VERSION 5.8 ;
BUSBITCHARS "[]" ;
DIVIDERCHAR "/" ;
UNITS
    DATABASE MICRONS 1000 ;
END UNITS

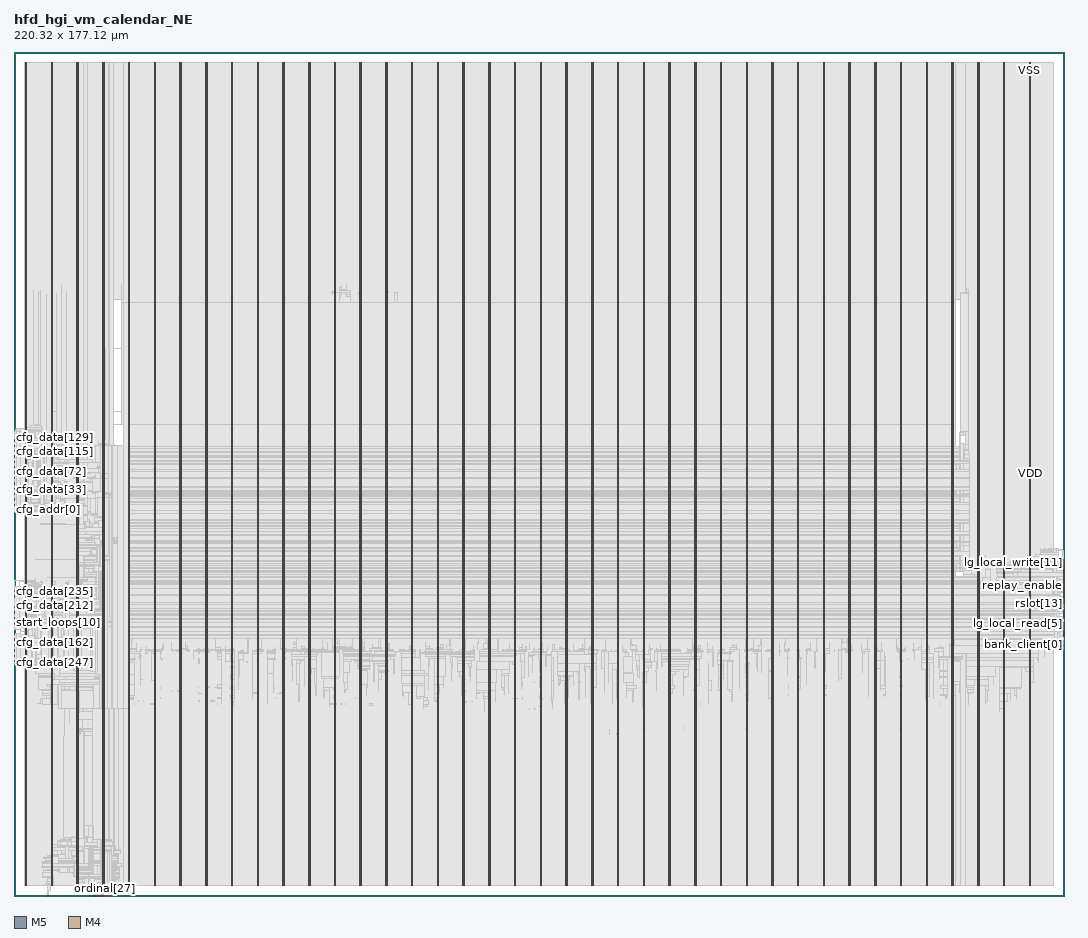
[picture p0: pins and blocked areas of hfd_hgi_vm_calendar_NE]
MACRO hfd_hgi_vm_calendar_NE
  FOREIGN hfd_hgi_vm_calendar_NE 0 0 ;
  CLASS BLOCK ;
  SIZE 220.32 BY 177.12 ;
  PIN active
    DIRECTION OUTPUT ;
    USE SIGNAL ;
    PORT
      LAYER M5 ;
        RECT  16.08 0 16.104 0.084 ;
    END
  END active
  PIN bank_client[0]
    DIRECTION OUTPUT ;
    USE SIGNAL ;
    PORT
      LAYER M4 ;
        RECT  220.236 54.48 220.32 54.504 ;
    END
  END bank_client[0]
  PIN bank_client[1]
    DIRECTION OUTPUT ;
    USE SIGNAL ;
    PORT
      LAYER M4 ;
        RECT  220.236 54.576 220.32 54.6 ;
    END
  END bank_client[1]
  PIN bank_client[2]
    DIRECTION OUTPUT ;
    USE SIGNAL ;
    PORT
      LAYER M4 ;
        RECT  220.236 54.672 220.32 54.696 ;
    END
  END bank_client[2]
  PIN bank_client[3]
    DIRECTION OUTPUT ;
    USE SIGNAL ;
    PORT
      LAYER M4 ;
        RECT  220.236 54.768 220.32 54.792 ;
    END
  END bank_client[3]
  PIN bank_client[4]
    DIRECTION OUTPUT ;
    USE SIGNAL ;
    PORT
      LAYER M4 ;
        RECT  220.236 54.864 220.32 54.888 ;
    END
  END bank_client[4]
  PIN bank_client[5]
    DIRECTION OUTPUT ;
    USE SIGNAL ;
    PORT
      LAYER M4 ;
        RECT  220.236 54.96 220.32 54.984 ;
    END
  END bank_client[5]
  PIN bank_client[6]
    DIRECTION OUTPUT ;
    USE SIGNAL ;
    PORT
      LAYER M4 ;
        RECT  220.236 55.056 220.32 55.08 ;
    END
  END bank_client[6]
  PIN bank_client[7]
    DIRECTION OUTPUT ;
    USE SIGNAL ;
    PORT
      LAYER M4 ;
        RECT  220.236 55.152 220.32 55.176 ;
    END
  END bank_client[7]
  PIN bank_enable[0]
    DIRECTION OUTPUT ;
    USE SIGNAL ;
    PORT
      LAYER M4 ;
        RECT  220.236 55.248 220.32 55.272 ;
    END
  END bank_enable[0]
  PIN bank_enable[1]
    DIRECTION OUTPUT ;
    USE SIGNAL ;
    PORT
      LAYER M4 ;
        RECT  220.236 55.344 220.32 55.368 ;
    END
  END bank_enable[1]
  PIN bank_enable[2]
    DIRECTION OUTPUT ;
    USE SIGNAL ;
    PORT
      LAYER M4 ;
        RECT  220.236 55.44 220.32 55.464 ;
    END
  END bank_enable[2]
  PIN bank_enable[3]
    DIRECTION OUTPUT ;
    USE SIGNAL ;
    PORT
      LAYER M4 ;
        RECT  220.236 55.536 220.32 55.56 ;
    END
  END bank_enable[3]
  PIN bank_enable[4]
    DIRECTION OUTPUT ;
    USE SIGNAL ;
    PORT
      LAYER M4 ;
        RECT  220.236 55.632 220.32 55.656 ;
    END
  END bank_enable[4]
  PIN bank_enable[5]
    DIRECTION OUTPUT ;
    USE SIGNAL ;
    PORT
      LAYER M4 ;
        RECT  220.236 55.728 220.32 55.752 ;
    END
  END bank_enable[5]
  PIN bank_enable[6]
    DIRECTION OUTPUT ;
    USE SIGNAL ;
    PORT
      LAYER M4 ;
        RECT  220.236 55.824 220.32 55.848 ;
    END
  END bank_enable[6]
  PIN bank_enable[7]
    DIRECTION OUTPUT ;
    USE SIGNAL ;
    PORT
      LAYER M4 ;
        RECT  220.236 55.92 220.32 55.944 ;
    END
  END bank_enable[7]
  PIN calendar_v
    DIRECTION OUTPUT ;
    USE SIGNAL ;
    PORT
      LAYER M5 ;
        RECT  16.176 0 16.2 0.084 ;
    END
  END calendar_v
  PIN cfg_addr[0]
    DIRECTION INPUT ;
    USE SIGNAL ;
    PORT
      LAYER M4 ;
        RECT  0 81.168 0.084 81.192 ;
    END
  END cfg_addr[0]
  PIN cfg_addr[1]
    DIRECTION INPUT ;
    USE SIGNAL ;
    PORT
      LAYER M4 ;
        RECT  0 81.264 0.084 81.288 ;
    END
  END cfg_addr[1]
  PIN cfg_addr[2]
    DIRECTION INPUT ;
    USE SIGNAL ;
    PORT
      LAYER M4 ;
        RECT  0 81.36 0.084 81.384 ;
    END
  END cfg_addr[2]
  PIN cfg_addr[3]
    DIRECTION INPUT ;
    USE SIGNAL ;
    PORT
      LAYER M4 ;
        RECT  0 81.456 0.084 81.48 ;
    END
  END cfg_addr[3]
  PIN cfg_addr[4]
    DIRECTION INPUT ;
    USE SIGNAL ;
    PORT
      LAYER M4 ;
        RECT  0 81.552 0.084 81.576 ;
    END
  END cfg_addr[4]
  PIN cfg_addr[5]
    DIRECTION INPUT ;
    USE SIGNAL ;
    PORT
      LAYER M4 ;
        RECT  0 81.648 0.084 81.672 ;
    END
  END cfg_addr[5]
  PIN cfg_addr[6]
    DIRECTION INPUT ;
    USE SIGNAL ;
    PORT
      LAYER M4 ;
        RECT  0 81.744 0.084 81.768 ;
    END
  END cfg_addr[6]
  PIN cfg_addr[7]
    DIRECTION INPUT ;
    USE SIGNAL ;
    PORT
      LAYER M4 ;
        RECT  0 81.84 0.084 81.864 ;
    END
  END cfg_addr[7]
  PIN cfg_addr[8]
    DIRECTION INPUT ;
    USE SIGNAL ;
    PORT
      LAYER M4 ;
        RECT  0 81.936 0.084 81.96 ;
    END
  END cfg_addr[8]
  PIN cfg_addr[9]
    DIRECTION INPUT ;
    USE SIGNAL ;
    PORT
      LAYER M4 ;
        RECT  0 82.032 0.084 82.056 ;
    END
  END cfg_addr[9]
  PIN cfg_data[0]
    DIRECTION INPUT ;
    USE SIGNAL ;
    PORT
      LAYER M4 ;
        RECT  0 82.128 0.084 82.152 ;
    END
  END cfg_data[0]
  PIN cfg_data[100]
    DIRECTION INPUT ;
    USE SIGNAL ;
    PORT
      LAYER M4 ;
        RECT  0 91.728 0.084 91.752 ;
    END
  END cfg_data[100]
  PIN cfg_data[101]
    DIRECTION INPUT ;
    USE SIGNAL ;
    PORT
      LAYER M4 ;
        RECT  0 91.824 0.084 91.848 ;
    END
  END cfg_data[101]
  PIN cfg_data[102]
    DIRECTION INPUT ;
    USE SIGNAL ;
    PORT
      LAYER M4 ;
        RECT  0 91.92 0.084 91.944 ;
    END
  END cfg_data[102]
  PIN cfg_data[103]
    DIRECTION INPUT ;
    USE SIGNAL ;
    PORT
      LAYER M4 ;
        RECT  0 92.016 0.084 92.04 ;
    END
  END cfg_data[103]
  PIN cfg_data[104]
    DIRECTION INPUT ;
    USE SIGNAL ;
    PORT
      LAYER M4 ;
        RECT  0 92.112 0.084 92.136 ;
    END
  END cfg_data[104]
  PIN cfg_data[105]
    DIRECTION INPUT ;
    USE SIGNAL ;
    PORT
      LAYER M4 ;
        RECT  0 92.208 0.084 92.232 ;
    END
  END cfg_data[105]
  PIN cfg_data[106]
    DIRECTION INPUT ;
    USE SIGNAL ;
    PORT
      LAYER M4 ;
        RECT  0 92.304 0.084 92.328 ;
    END
  END cfg_data[106]
  PIN cfg_data[107]
    DIRECTION INPUT ;
    USE SIGNAL ;
    PORT
      LAYER M4 ;
        RECT  0 92.4 0.084 92.424 ;
    END
  END cfg_data[107]
  PIN cfg_data[108]
    DIRECTION INPUT ;
    USE SIGNAL ;
    PORT
      LAYER M4 ;
        RECT  0 92.496 0.084 92.52 ;
    END
  END cfg_data[108]
  PIN cfg_data[109]
    DIRECTION INPUT ;
    USE SIGNAL ;
    PORT
      LAYER M4 ;
        RECT  0 92.592 0.084 92.616 ;
    END
  END cfg_data[109]
  PIN cfg_data[10]
    DIRECTION INPUT ;
    USE SIGNAL ;
    PORT
      LAYER M4 ;
        RECT  0 83.088 0.084 83.112 ;
    END
  END cfg_data[10]
  PIN cfg_data[110]
    DIRECTION INPUT ;
    USE SIGNAL ;
    PORT
      LAYER M4 ;
        RECT  0 92.688 0.084 92.712 ;
    END
  END cfg_data[110]
  PIN cfg_data[111]
    DIRECTION INPUT ;
    USE SIGNAL ;
    PORT
      LAYER M4 ;
        RECT  0 92.784 0.084 92.808 ;
    END
  END cfg_data[111]
  PIN cfg_data[112]
    DIRECTION INPUT ;
    USE SIGNAL ;
    PORT
      LAYER M4 ;
        RECT  0 92.88 0.084 92.904 ;
    END
  END cfg_data[112]
  PIN cfg_data[113]
    DIRECTION INPUT ;
    USE SIGNAL ;
    PORT
      LAYER M4 ;
        RECT  0 92.976 0.084 93 ;
    END
  END cfg_data[113]
  PIN cfg_data[114]
    DIRECTION INPUT ;
    USE SIGNAL ;
    PORT
      LAYER M4 ;
        RECT  0 93.072 0.084 93.096 ;
    END
  END cfg_data[114]
  PIN cfg_data[115]
    DIRECTION INPUT ;
    USE SIGNAL ;
    PORT
      LAYER M4 ;
        RECT  0 93.168 0.084 93.192 ;
    END
  END cfg_data[115]
  PIN cfg_data[116]
    DIRECTION INPUT ;
    USE SIGNAL ;
    PORT
      LAYER M4 ;
        RECT  0 93.264 0.084 93.288 ;
    END
  END cfg_data[116]
  PIN cfg_data[117]
    DIRECTION INPUT ;
    USE SIGNAL ;
    PORT
      LAYER M4 ;
        RECT  0 93.36 0.084 93.384 ;
    END
  END cfg_data[117]
  PIN cfg_data[118]
    DIRECTION INPUT ;
    USE SIGNAL ;
    PORT
      LAYER M4 ;
        RECT  0 93.456 0.084 93.48 ;
    END
  END cfg_data[118]
  PIN cfg_data[119]
    DIRECTION INPUT ;
    USE SIGNAL ;
    PORT
      LAYER M4 ;
        RECT  0 93.552 0.084 93.576 ;
    END
  END cfg_data[119]
  PIN cfg_data[11]
    DIRECTION INPUT ;
    USE SIGNAL ;
    PORT
      LAYER M4 ;
        RECT  0 83.184 0.084 83.208 ;
    END
  END cfg_data[11]
  PIN cfg_data[120]
    DIRECTION INPUT ;
    USE SIGNAL ;
    PORT
      LAYER M4 ;
        RECT  0 93.648 0.084 93.672 ;
    END
  END cfg_data[120]
  PIN cfg_data[121]
    DIRECTION INPUT ;
    USE SIGNAL ;
    PORT
      LAYER M4 ;
        RECT  0 93.744 0.084 93.768 ;
    END
  END cfg_data[121]
  PIN cfg_data[122]
    DIRECTION INPUT ;
    USE SIGNAL ;
    PORT
      LAYER M4 ;
        RECT  0 93.84 0.084 93.864 ;
    END
  END cfg_data[122]
  PIN cfg_data[123]
    DIRECTION INPUT ;
    USE SIGNAL ;
    PORT
      LAYER M4 ;
        RECT  0 93.936 0.084 93.96 ;
    END
  END cfg_data[123]
  PIN cfg_data[124]
    DIRECTION INPUT ;
    USE SIGNAL ;
    PORT
      LAYER M4 ;
        RECT  0 94.032 0.084 94.056 ;
    END
  END cfg_data[124]
  PIN cfg_data[125]
    DIRECTION INPUT ;
    USE SIGNAL ;
    PORT
      LAYER M4 ;
        RECT  0 94.128 0.084 94.152 ;
    END
  END cfg_data[125]
  PIN cfg_data[126]
    DIRECTION INPUT ;
    USE SIGNAL ;
    PORT
      LAYER M4 ;
        RECT  0 94.224 0.084 94.248 ;
    END
  END cfg_data[126]
  PIN cfg_data[127]
    DIRECTION INPUT ;
    USE SIGNAL ;
    PORT
      LAYER M4 ;
        RECT  0 94.32 0.084 94.344 ;
    END
  END cfg_data[127]
  PIN cfg_data[128]
    DIRECTION INPUT ;
    USE SIGNAL ;
    PORT
      LAYER M4 ;
        RECT  0 94.416 0.084 94.44 ;
    END
  END cfg_data[128]
  PIN cfg_data[129]
    DIRECTION INPUT ;
    USE SIGNAL ;
    PORT
      LAYER M4 ;
        RECT  0 94.512 0.084 94.536 ;
    END
  END cfg_data[129]
  PIN cfg_data[12]
    DIRECTION INPUT ;
    USE SIGNAL ;
    PORT
      LAYER M4 ;
        RECT  0 83.28 0.084 83.304 ;
    END
  END cfg_data[12]
  PIN cfg_data[130]
    DIRECTION INPUT ;
    USE SIGNAL ;
    PORT
      LAYER M4 ;
        RECT  0 94.608 0.084 94.632 ;
    END
  END cfg_data[130]
  PIN cfg_data[131]
    DIRECTION INPUT ;
    USE SIGNAL ;
    PORT
      LAYER M4 ;
        RECT  0 94.704 0.084 94.728 ;
    END
  END cfg_data[131]
  PIN cfg_data[132]
    DIRECTION INPUT ;
    USE SIGNAL ;
    PORT
      LAYER M4 ;
        RECT  0 94.8 0.084 94.824 ;
    END
  END cfg_data[132]
  PIN cfg_data[133]
    DIRECTION INPUT ;
    USE SIGNAL ;
    PORT
      LAYER M4 ;
        RECT  0 94.896 0.084 94.92 ;
    END
  END cfg_data[133]
  PIN cfg_data[134]
    DIRECTION INPUT ;
    USE SIGNAL ;
    PORT
      LAYER M4 ;
        RECT  0 94.992 0.084 95.016 ;
    END
  END cfg_data[134]
  PIN cfg_data[135]
    DIRECTION INPUT ;
    USE SIGNAL ;
    PORT
      LAYER M4 ;
        RECT  0 95.088 0.084 95.112 ;
    END
  END cfg_data[135]
  PIN cfg_data[136]
    DIRECTION INPUT ;
    USE SIGNAL ;
    PORT
      LAYER M4 ;
        RECT  0 95.184 0.084 95.208 ;
    END
  END cfg_data[136]
  PIN cfg_data[137]
    DIRECTION INPUT ;
    USE SIGNAL ;
    PORT
      LAYER M4 ;
        RECT  0 95.28 0.084 95.304 ;
    END
  END cfg_data[137]
  PIN cfg_data[138]
    DIRECTION INPUT ;
    USE SIGNAL ;
    PORT
      LAYER M4 ;
        RECT  0 95.376 0.084 95.4 ;
    END
  END cfg_data[138]
  PIN cfg_data[139]
    DIRECTION INPUT ;
    USE SIGNAL ;
    PORT
      LAYER M4 ;
        RECT  0 95.472 0.084 95.496 ;
    END
  END cfg_data[139]
  PIN cfg_data[13]
    DIRECTION INPUT ;
    USE SIGNAL ;
    PORT
      LAYER M4 ;
        RECT  0 83.376 0.084 83.4 ;
    END
  END cfg_data[13]
  PIN cfg_data[140]
    DIRECTION INPUT ;
    USE SIGNAL ;
    PORT
      LAYER M4 ;
        RECT  0 95.568 0.084 95.592 ;
    END
  END cfg_data[140]
  PIN cfg_data[141]
    DIRECTION INPUT ;
    USE SIGNAL ;
    PORT
      LAYER M4 ;
        RECT  0 95.664 0.084 95.688 ;
    END
  END cfg_data[141]
  PIN cfg_data[142]
    DIRECTION INPUT ;
    USE SIGNAL ;
    PORT
      LAYER M4 ;
        RECT  0 95.76 0.084 95.784 ;
    END
  END cfg_data[142]
  PIN cfg_data[143]
    DIRECTION INPUT ;
    USE SIGNAL ;
    PORT
      LAYER M4 ;
        RECT  0 95.856 0.084 95.88 ;
    END
  END cfg_data[143]
  PIN cfg_data[144]
    DIRECTION INPUT ;
    USE SIGNAL ;
    PORT
      LAYER M4 ;
        RECT  0 95.952 0.084 95.976 ;
    END
  END cfg_data[144]
  PIN cfg_data[145]
    DIRECTION INPUT ;
    USE SIGNAL ;
    PORT
      LAYER M4 ;
        RECT  0 96.048 0.084 96.072 ;
    END
  END cfg_data[145]
  PIN cfg_data[146]
    DIRECTION INPUT ;
    USE SIGNAL ;
    PORT
      LAYER M4 ;
        RECT  0 96.144 0.084 96.168 ;
    END
  END cfg_data[146]
  PIN cfg_data[147]
    DIRECTION INPUT ;
    USE SIGNAL ;
    PORT
      LAYER M4 ;
        RECT  0 96.24 0.084 96.264 ;
    END
  END cfg_data[147]
  PIN cfg_data[148]
    DIRECTION INPUT ;
    USE SIGNAL ;
    PORT
      LAYER M4 ;
        RECT  0 96.336 0.084 96.36 ;
    END
  END cfg_data[148]
  PIN cfg_data[149]
    DIRECTION INPUT ;
    USE SIGNAL ;
    PORT
      LAYER M4 ;
        RECT  0 96.432 0.084 96.456 ;
    END
  END cfg_data[149]
  PIN cfg_data[14]
    DIRECTION INPUT ;
    USE SIGNAL ;
    PORT
      LAYER M4 ;
        RECT  0 83.472 0.084 83.496 ;
    END
  END cfg_data[14]
  PIN cfg_data[150]
    DIRECTION INPUT ;
    USE SIGNAL ;
    PORT
      LAYER M4 ;
        RECT  0 51.984 0.084 52.008 ;
    END
  END cfg_data[150]
  PIN cfg_data[151]
    DIRECTION INPUT ;
    USE SIGNAL ;
    PORT
      LAYER M4 ;
        RECT  0 52.08 0.084 52.104 ;
    END
  END cfg_data[151]
  PIN cfg_data[152]
    DIRECTION INPUT ;
    USE SIGNAL ;
    PORT
      LAYER M4 ;
        RECT  0 52.176 0.084 52.2 ;
    END
  END cfg_data[152]
  PIN cfg_data[153]
    DIRECTION INPUT ;
    USE SIGNAL ;
    PORT
      LAYER M4 ;
        RECT  0 52.272 0.084 52.296 ;
    END
  END cfg_data[153]
  PIN cfg_data[154]
    DIRECTION INPUT ;
    USE SIGNAL ;
    PORT
      LAYER M4 ;
        RECT  0 52.368 0.084 52.392 ;
    END
  END cfg_data[154]
  PIN cfg_data[155]
    DIRECTION INPUT ;
    USE SIGNAL ;
    PORT
      LAYER M4 ;
        RECT  0 52.464 0.084 52.488 ;
    END
  END cfg_data[155]
  PIN cfg_data[156]
    DIRECTION INPUT ;
    USE SIGNAL ;
    PORT
      LAYER M4 ;
        RECT  0 52.56 0.084 52.584 ;
    END
  END cfg_data[156]
  PIN cfg_data[157]
    DIRECTION INPUT ;
    USE SIGNAL ;
    PORT
      LAYER M4 ;
        RECT  0 52.656 0.084 52.68 ;
    END
  END cfg_data[157]
  PIN cfg_data[158]
    DIRECTION INPUT ;
    USE SIGNAL ;
    PORT
      LAYER M4 ;
        RECT  0 52.752 0.084 52.776 ;
    END
  END cfg_data[158]
  PIN cfg_data[159]
    DIRECTION INPUT ;
    USE SIGNAL ;
    PORT
      LAYER M4 ;
        RECT  0 52.848 0.084 52.872 ;
    END
  END cfg_data[159]
  PIN cfg_data[15]
    DIRECTION INPUT ;
    USE SIGNAL ;
    PORT
      LAYER M4 ;
        RECT  0 83.568 0.084 83.592 ;
    END
  END cfg_data[15]
  PIN cfg_data[160]
    DIRECTION INPUT ;
    USE SIGNAL ;
    PORT
      LAYER M4 ;
        RECT  0 52.944 0.084 52.968 ;
    END
  END cfg_data[160]
  PIN cfg_data[161]
    DIRECTION INPUT ;
    USE SIGNAL ;
    PORT
      LAYER M4 ;
        RECT  0 53.04 0.084 53.064 ;
    END
  END cfg_data[161]
  PIN cfg_data[162]
    DIRECTION INPUT ;
    USE SIGNAL ;
    PORT
      LAYER M4 ;
        RECT  0 53.136 0.084 53.16 ;
    END
  END cfg_data[162]
  PIN cfg_data[163]
    DIRECTION INPUT ;
    USE SIGNAL ;
    PORT
      LAYER M4 ;
        RECT  0 53.232 0.084 53.256 ;
    END
  END cfg_data[163]
  PIN cfg_data[164]
    DIRECTION INPUT ;
    USE SIGNAL ;
    PORT
      LAYER M4 ;
        RECT  0 53.328 0.084 53.352 ;
    END
  END cfg_data[164]
  PIN cfg_data[165]
    DIRECTION INPUT ;
    USE SIGNAL ;
    PORT
      LAYER M4 ;
        RECT  0 53.424 0.084 53.448 ;
    END
  END cfg_data[165]
  PIN cfg_data[166]
    DIRECTION INPUT ;
    USE SIGNAL ;
    PORT
      LAYER M4 ;
        RECT  0 53.52 0.084 53.544 ;
    END
  END cfg_data[166]
  PIN cfg_data[167]
    DIRECTION INPUT ;
    USE SIGNAL ;
    PORT
      LAYER M4 ;
        RECT  0 53.616 0.084 53.64 ;
    END
  END cfg_data[167]
  PIN cfg_data[168]
    DIRECTION INPUT ;
    USE SIGNAL ;
    PORT
      LAYER M4 ;
        RECT  0 53.712 0.084 53.736 ;
    END
  END cfg_data[168]
  PIN cfg_data[169]
    DIRECTION INPUT ;
    USE SIGNAL ;
    PORT
      LAYER M4 ;
        RECT  0 53.808 0.084 53.832 ;
    END
  END cfg_data[169]
  PIN cfg_data[16]
    DIRECTION INPUT ;
    USE SIGNAL ;
    PORT
      LAYER M4 ;
        RECT  0 83.664 0.084 83.688 ;
    END
  END cfg_data[16]
  PIN cfg_data[170]
    DIRECTION INPUT ;
    USE SIGNAL ;
    PORT
      LAYER M4 ;
        RECT  0 53.904 0.084 53.928 ;
    END
  END cfg_data[170]
  PIN cfg_data[171]
    DIRECTION INPUT ;
    USE SIGNAL ;
    PORT
      LAYER M4 ;
        RECT  0 54 0.084 54.024 ;
    END
  END cfg_data[171]
  PIN cfg_data[172]
    DIRECTION INPUT ;
    USE SIGNAL ;
    PORT
      LAYER M4 ;
        RECT  0 54.096 0.084 54.12 ;
    END
  END cfg_data[172]
  PIN cfg_data[173]
    DIRECTION INPUT ;
    USE SIGNAL ;
    PORT
      LAYER M4 ;
        RECT  0 54.192 0.084 54.216 ;
    END
  END cfg_data[173]
  PIN cfg_data[174]
    DIRECTION INPUT ;
    USE SIGNAL ;
    PORT
      LAYER M4 ;
        RECT  0 54.288 0.084 54.312 ;
    END
  END cfg_data[174]
  PIN cfg_data[175]
    DIRECTION INPUT ;
    USE SIGNAL ;
    PORT
      LAYER M4 ;
        RECT  0 54.384 0.084 54.408 ;
    END
  END cfg_data[175]
  PIN cfg_data[176]
    DIRECTION INPUT ;
    USE SIGNAL ;
    PORT
      LAYER M4 ;
        RECT  0 54.48 0.084 54.504 ;
    END
  END cfg_data[176]
  PIN cfg_data[177]
    DIRECTION INPUT ;
    USE SIGNAL ;
    PORT
      LAYER M4 ;
        RECT  0 54.576 0.084 54.6 ;
    END
  END cfg_data[177]
  PIN cfg_data[178]
    DIRECTION INPUT ;
    USE SIGNAL ;
    PORT
      LAYER M4 ;
        RECT  0 54.672 0.084 54.696 ;
    END
  END cfg_data[178]
  PIN cfg_data[179]
    DIRECTION INPUT ;
    USE SIGNAL ;
    PORT
      LAYER M4 ;
        RECT  0 54.768 0.084 54.792 ;
    END
  END cfg_data[179]
  PIN cfg_data[17]
    DIRECTION INPUT ;
    USE SIGNAL ;
    PORT
      LAYER M4 ;
        RECT  0 83.76 0.084 83.784 ;
    END
  END cfg_data[17]
  PIN cfg_data[180]
    DIRECTION INPUT ;
    USE SIGNAL ;
    PORT
      LAYER M4 ;
        RECT  0 54.864 0.084 54.888 ;
    END
  END cfg_data[180]
  PIN cfg_data[181]
    DIRECTION INPUT ;
    USE SIGNAL ;
    PORT
      LAYER M4 ;
        RECT  0 54.96 0.084 54.984 ;
    END
  END cfg_data[181]
  PIN cfg_data[182]
    DIRECTION INPUT ;
    USE SIGNAL ;
    PORT
      LAYER M4 ;
        RECT  0 58.128 0.084 58.152 ;
    END
  END cfg_data[182]
  PIN cfg_data[183]
    DIRECTION INPUT ;
    USE SIGNAL ;
    PORT
      LAYER M4 ;
        RECT  0 58.224 0.084 58.248 ;
    END
  END cfg_data[183]
  PIN cfg_data[184]
    DIRECTION INPUT ;
    USE SIGNAL ;
    PORT
      LAYER M4 ;
        RECT  0 58.32 0.084 58.344 ;
    END
  END cfg_data[184]
  PIN cfg_data[185]
    DIRECTION INPUT ;
    USE SIGNAL ;
    PORT
      LAYER M4 ;
        RECT  0 58.416 0.084 58.44 ;
    END
  END cfg_data[185]
  PIN cfg_data[186]
    DIRECTION INPUT ;
    USE SIGNAL ;
    PORT
      LAYER M4 ;
        RECT  0 58.512 0.084 58.536 ;
    END
  END cfg_data[186]
  PIN cfg_data[187]
    DIRECTION INPUT ;
    USE SIGNAL ;
    PORT
      LAYER M4 ;
        RECT  0 58.608 0.084 58.632 ;
    END
  END cfg_data[187]
  PIN cfg_data[188]
    DIRECTION INPUT ;
    USE SIGNAL ;
    PORT
      LAYER M4 ;
        RECT  0 58.704 0.084 58.728 ;
    END
  END cfg_data[188]
  PIN cfg_data[189]
    DIRECTION INPUT ;
    USE SIGNAL ;
    PORT
      LAYER M4 ;
        RECT  0 58.8 0.084 58.824 ;
    END
  END cfg_data[189]
  PIN cfg_data[18]
    DIRECTION INPUT ;
    USE SIGNAL ;
    PORT
      LAYER M4 ;
        RECT  0 83.856 0.084 83.88 ;
    END
  END cfg_data[18]
  PIN cfg_data[190]
    DIRECTION INPUT ;
    USE SIGNAL ;
    PORT
      LAYER M4 ;
        RECT  0 58.896 0.084 58.92 ;
    END
  END cfg_data[190]
  PIN cfg_data[191]
    DIRECTION INPUT ;
    USE SIGNAL ;
    PORT
      LAYER M4 ;
        RECT  0 58.992 0.084 59.016 ;
    END
  END cfg_data[191]
  PIN cfg_data[192]
    DIRECTION INPUT ;
    USE SIGNAL ;
    PORT
      LAYER M4 ;
        RECT  0 59.088 0.084 59.112 ;
    END
  END cfg_data[192]
  PIN cfg_data[193]
    DIRECTION INPUT ;
    USE SIGNAL ;
    PORT
      LAYER M4 ;
        RECT  0 59.184 0.084 59.208 ;
    END
  END cfg_data[193]
  PIN cfg_data[194]
    DIRECTION INPUT ;
    USE SIGNAL ;
    PORT
      LAYER M4 ;
        RECT  0 59.28 0.084 59.304 ;
    END
  END cfg_data[194]
  PIN cfg_data[195]
    DIRECTION INPUT ;
    USE SIGNAL ;
    PORT
      LAYER M4 ;
        RECT  0 59.376 0.084 59.4 ;
    END
  END cfg_data[195]
  PIN cfg_data[196]
    DIRECTION INPUT ;
    USE SIGNAL ;
    PORT
      LAYER M4 ;
        RECT  0 59.472 0.084 59.496 ;
    END
  END cfg_data[196]
  PIN cfg_data[197]
    DIRECTION INPUT ;
    USE SIGNAL ;
    PORT
      LAYER M4 ;
        RECT  0 59.568 0.084 59.592 ;
    END
  END cfg_data[197]
  PIN cfg_data[198]
    DIRECTION INPUT ;
    USE SIGNAL ;
    PORT
      LAYER M4 ;
        RECT  0 59.664 0.084 59.688 ;
    END
  END cfg_data[198]
  PIN cfg_data[199]
    DIRECTION INPUT ;
    USE SIGNAL ;
    PORT
      LAYER M4 ;
        RECT  0 59.76 0.084 59.784 ;
    END
  END cfg_data[199]
  PIN cfg_data[19]
    DIRECTION INPUT ;
    USE SIGNAL ;
    PORT
      LAYER M4 ;
        RECT  0 83.952 0.084 83.976 ;
    END
  END cfg_data[19]
  PIN cfg_data[1]
    DIRECTION INPUT ;
    USE SIGNAL ;
    PORT
      LAYER M4 ;
        RECT  0 82.224 0.084 82.248 ;
    END
  END cfg_data[1]
  PIN cfg_data[200]
    DIRECTION INPUT ;
    USE SIGNAL ;
    PORT
      LAYER M4 ;
        RECT  0 59.856 0.084 59.88 ;
    END
  END cfg_data[200]
  PIN cfg_data[201]
    DIRECTION INPUT ;
    USE SIGNAL ;
    PORT
      LAYER M4 ;
        RECT  0 59.952 0.084 59.976 ;
    END
  END cfg_data[201]
  PIN cfg_data[202]
    DIRECTION INPUT ;
    USE SIGNAL ;
    PORT
      LAYER M4 ;
        RECT  0 60.048 0.084 60.072 ;
    END
  END cfg_data[202]
  PIN cfg_data[203]
    DIRECTION INPUT ;
    USE SIGNAL ;
    PORT
      LAYER M4 ;
        RECT  0 60.144 0.084 60.168 ;
    END
  END cfg_data[203]
  PIN cfg_data[204]
    DIRECTION INPUT ;
    USE SIGNAL ;
    PORT
      LAYER M4 ;
        RECT  0 60.24 0.084 60.264 ;
    END
  END cfg_data[204]
  PIN cfg_data[205]
    DIRECTION INPUT ;
    USE SIGNAL ;
    PORT
      LAYER M4 ;
        RECT  0 60.336 0.084 60.36 ;
    END
  END cfg_data[205]
  PIN cfg_data[206]
    DIRECTION INPUT ;
    USE SIGNAL ;
    PORT
      LAYER M4 ;
        RECT  0 60.432 0.084 60.456 ;
    END
  END cfg_data[206]
  PIN cfg_data[207]
    DIRECTION INPUT ;
    USE SIGNAL ;
    PORT
      LAYER M4 ;
        RECT  0 60.528 0.084 60.552 ;
    END
  END cfg_data[207]
  PIN cfg_data[208]
    DIRECTION INPUT ;
    USE SIGNAL ;
    PORT
      LAYER M4 ;
        RECT  0 60.624 0.084 60.648 ;
    END
  END cfg_data[208]
  PIN cfg_data[209]
    DIRECTION INPUT ;
    USE SIGNAL ;
    PORT
      LAYER M4 ;
        RECT  0 60.72 0.084 60.744 ;
    END
  END cfg_data[209]
  PIN cfg_data[20]
    DIRECTION INPUT ;
    USE SIGNAL ;
    PORT
      LAYER M4 ;
        RECT  0 84.048 0.084 84.072 ;
    END
  END cfg_data[20]
  PIN cfg_data[210]
    DIRECTION INPUT ;
    USE SIGNAL ;
    PORT
      LAYER M4 ;
        RECT  0 60.816 0.084 60.84 ;
    END
  END cfg_data[210]
  PIN cfg_data[211]
    DIRECTION INPUT ;
    USE SIGNAL ;
    PORT
      LAYER M4 ;
        RECT  0 60.912 0.084 60.936 ;
    END
  END cfg_data[211]
  PIN cfg_data[212]
    DIRECTION INPUT ;
    USE SIGNAL ;
    PORT
      LAYER M4 ;
        RECT  0 61.008 0.084 61.032 ;
    END
  END cfg_data[212]
  PIN cfg_data[213]
    DIRECTION INPUT ;
    USE SIGNAL ;
    PORT
      LAYER M4 ;
        RECT  0 61.104 0.084 61.128 ;
    END
  END cfg_data[213]
  PIN cfg_data[214]
    DIRECTION INPUT ;
    USE SIGNAL ;
    PORT
      LAYER M4 ;
        RECT  0 61.968 0.084 61.992 ;
    END
  END cfg_data[214]
  PIN cfg_data[215]
    DIRECTION INPUT ;
    USE SIGNAL ;
    PORT
      LAYER M4 ;
        RECT  0 62.064 0.084 62.088 ;
    END
  END cfg_data[215]
  PIN cfg_data[216]
    DIRECTION INPUT ;
    USE SIGNAL ;
    PORT
      LAYER M4 ;
        RECT  0 62.16 0.084 62.184 ;
    END
  END cfg_data[216]
  PIN cfg_data[217]
    DIRECTION INPUT ;
    USE SIGNAL ;
    PORT
      LAYER M4 ;
        RECT  0 62.256 0.084 62.28 ;
    END
  END cfg_data[217]
  PIN cfg_data[218]
    DIRECTION INPUT ;
    USE SIGNAL ;
    PORT
      LAYER M4 ;
        RECT  0 62.352 0.084 62.376 ;
    END
  END cfg_data[218]
  PIN cfg_data[219]
    DIRECTION INPUT ;
    USE SIGNAL ;
    PORT
      LAYER M4 ;
        RECT  0 62.448 0.084 62.472 ;
    END
  END cfg_data[219]
  PIN cfg_data[21]
    DIRECTION INPUT ;
    USE SIGNAL ;
    PORT
      LAYER M4 ;
        RECT  0 84.144 0.084 84.168 ;
    END
  END cfg_data[21]
  PIN cfg_data[220]
    DIRECTION INPUT ;
    USE SIGNAL ;
    PORT
      LAYER M4 ;
        RECT  0 62.544 0.084 62.568 ;
    END
  END cfg_data[220]
  PIN cfg_data[221]
    DIRECTION INPUT ;
    USE SIGNAL ;
    PORT
      LAYER M4 ;
        RECT  0 62.64 0.084 62.664 ;
    END
  END cfg_data[221]
  PIN cfg_data[222]
    DIRECTION INPUT ;
    USE SIGNAL ;
    PORT
      LAYER M4 ;
        RECT  0 62.736 0.084 62.76 ;
    END
  END cfg_data[222]
  PIN cfg_data[223]
    DIRECTION INPUT ;
    USE SIGNAL ;
    PORT
      LAYER M4 ;
        RECT  0 62.832 0.084 62.856 ;
    END
  END cfg_data[223]
  PIN cfg_data[224]
    DIRECTION INPUT ;
    USE SIGNAL ;
    PORT
      LAYER M4 ;
        RECT  0 62.928 0.084 62.952 ;
    END
  END cfg_data[224]
  PIN cfg_data[225]
    DIRECTION INPUT ;
    USE SIGNAL ;
    PORT
      LAYER M4 ;
        RECT  0 63.024 0.084 63.048 ;
    END
  END cfg_data[225]
  PIN cfg_data[226]
    DIRECTION INPUT ;
    USE SIGNAL ;
    PORT
      LAYER M4 ;
        RECT  0 63.12 0.084 63.144 ;
    END
  END cfg_data[226]
  PIN cfg_data[227]
    DIRECTION INPUT ;
    USE SIGNAL ;
    PORT
      LAYER M4 ;
        RECT  0 63.216 0.084 63.24 ;
    END
  END cfg_data[227]
  PIN cfg_data[228]
    DIRECTION INPUT ;
    USE SIGNAL ;
    PORT
      LAYER M4 ;
        RECT  0 63.312 0.084 63.336 ;
    END
  END cfg_data[228]
  PIN cfg_data[229]
    DIRECTION INPUT ;
    USE SIGNAL ;
    PORT
      LAYER M4 ;
        RECT  0 63.408 0.084 63.432 ;
    END
  END cfg_data[229]
  PIN cfg_data[22]
    DIRECTION INPUT ;
    USE SIGNAL ;
    PORT
      LAYER M4 ;
        RECT  0 84.24 0.084 84.264 ;
    END
  END cfg_data[22]
  PIN cfg_data[230]
    DIRECTION INPUT ;
    USE SIGNAL ;
    PORT
      LAYER M4 ;
        RECT  0 63.504 0.084 63.528 ;
    END
  END cfg_data[230]
  PIN cfg_data[231]
    DIRECTION INPUT ;
    USE SIGNAL ;
    PORT
      LAYER M4 ;
        RECT  0 63.6 0.084 63.624 ;
    END
  END cfg_data[231]
  PIN cfg_data[232]
    DIRECTION INPUT ;
    USE SIGNAL ;
    PORT
      LAYER M4 ;
        RECT  0 63.696 0.084 63.72 ;
    END
  END cfg_data[232]
  PIN cfg_data[233]
    DIRECTION INPUT ;
    USE SIGNAL ;
    PORT
      LAYER M4 ;
        RECT  0 63.792 0.084 63.816 ;
    END
  END cfg_data[233]
  PIN cfg_data[234]
    DIRECTION INPUT ;
    USE SIGNAL ;
    PORT
      LAYER M4 ;
        RECT  0 63.888 0.084 63.912 ;
    END
  END cfg_data[234]
  PIN cfg_data[235]
    DIRECTION INPUT ;
    USE SIGNAL ;
    PORT
      LAYER M4 ;
        RECT  0 63.984 0.084 64.008 ;
    END
  END cfg_data[235]
  PIN cfg_data[236]
    DIRECTION INPUT ;
    USE SIGNAL ;
    PORT
      LAYER M4 ;
        RECT  0 64.08 0.084 64.104 ;
    END
  END cfg_data[236]
  PIN cfg_data[237]
    DIRECTION INPUT ;
    USE SIGNAL ;
    PORT
      LAYER M4 ;
        RECT  0 64.176 0.084 64.2 ;
    END
  END cfg_data[237]
  PIN cfg_data[238]
    DIRECTION INPUT ;
    USE SIGNAL ;
    PORT
      LAYER M4 ;
        RECT  0 64.272 0.084 64.296 ;
    END
  END cfg_data[238]
  PIN cfg_data[239]
    DIRECTION INPUT ;
    USE SIGNAL ;
    PORT
      LAYER M4 ;
        RECT  0 64.368 0.084 64.392 ;
    END
  END cfg_data[239]
  PIN cfg_data[23]
    DIRECTION INPUT ;
    USE SIGNAL ;
    PORT
      LAYER M4 ;
        RECT  0 84.336 0.084 84.36 ;
    END
  END cfg_data[23]
  PIN cfg_data[240]
    DIRECTION INPUT ;
    USE SIGNAL ;
    PORT
      LAYER M4 ;
        RECT  0 64.464 0.084 64.488 ;
    END
  END cfg_data[240]
  PIN cfg_data[241]
    DIRECTION INPUT ;
    USE SIGNAL ;
    PORT
      LAYER M4 ;
        RECT  0 64.56 0.084 64.584 ;
    END
  END cfg_data[241]
  PIN cfg_data[242]
    DIRECTION INPUT ;
    USE SIGNAL ;
    PORT
      LAYER M4 ;
        RECT  0 64.656 0.084 64.68 ;
    END
  END cfg_data[242]
  PIN cfg_data[243]
    DIRECTION INPUT ;
    USE SIGNAL ;
    PORT
      LAYER M4 ;
        RECT  0 64.752 0.084 64.776 ;
    END
  END cfg_data[243]
  PIN cfg_data[244]
    DIRECTION INPUT ;
    USE SIGNAL ;
    PORT
      LAYER M4 ;
        RECT  0 64.848 0.084 64.872 ;
    END
  END cfg_data[244]
  PIN cfg_data[245]
    DIRECTION INPUT ;
    USE SIGNAL ;
    PORT
      LAYER M4 ;
        RECT  0 64.944 0.084 64.968 ;
    END
  END cfg_data[245]
  PIN cfg_data[246]
    DIRECTION INPUT ;
    USE SIGNAL ;
    PORT
      LAYER M4 ;
        RECT  0 48.912 0.084 48.936 ;
    END
  END cfg_data[246]
  PIN cfg_data[247]
    DIRECTION INPUT ;
    USE SIGNAL ;
    PORT
      LAYER M4 ;
        RECT  0 49.008 0.084 49.032 ;
    END
  END cfg_data[247]
  PIN cfg_data[248]
    DIRECTION INPUT ;
    USE SIGNAL ;
    PORT
      LAYER M4 ;
        RECT  0 49.104 0.084 49.128 ;
    END
  END cfg_data[248]
  PIN cfg_data[249]
    DIRECTION INPUT ;
    USE SIGNAL ;
    PORT
      LAYER M4 ;
        RECT  0 49.2 0.084 49.224 ;
    END
  END cfg_data[249]
  PIN cfg_data[24]
    DIRECTION INPUT ;
    USE SIGNAL ;
    PORT
      LAYER M4 ;
        RECT  0 84.432 0.084 84.456 ;
    END
  END cfg_data[24]
  PIN cfg_data[250]
    DIRECTION INPUT ;
    USE SIGNAL ;
    PORT
      LAYER M4 ;
        RECT  0 49.296 0.084 49.32 ;
    END
  END cfg_data[250]
  PIN cfg_data[251]
    DIRECTION INPUT ;
    USE SIGNAL ;
    PORT
      LAYER M4 ;
        RECT  0 49.392 0.084 49.416 ;
    END
  END cfg_data[251]
  PIN cfg_data[252]
    DIRECTION INPUT ;
    USE SIGNAL ;
    PORT
      LAYER M4 ;
        RECT  0 49.488 0.084 49.512 ;
    END
  END cfg_data[252]
  PIN cfg_data[253]
    DIRECTION INPUT ;
    USE SIGNAL ;
    PORT
      LAYER M4 ;
        RECT  0 49.584 0.084 49.608 ;
    END
  END cfg_data[253]
  PIN cfg_data[254]
    DIRECTION INPUT ;
    USE SIGNAL ;
    PORT
      LAYER M4 ;
        RECT  0 49.68 0.084 49.704 ;
    END
  END cfg_data[254]
  PIN cfg_data[255]
    DIRECTION INPUT ;
    USE SIGNAL ;
    PORT
      LAYER M4 ;
        RECT  0 49.776 0.084 49.8 ;
    END
  END cfg_data[255]
  PIN cfg_data[25]
    DIRECTION INPUT ;
    USE SIGNAL ;
    PORT
      LAYER M4 ;
        RECT  0 84.528 0.084 84.552 ;
    END
  END cfg_data[25]
  PIN cfg_data[26]
    DIRECTION INPUT ;
    USE SIGNAL ;
    PORT
      LAYER M4 ;
        RECT  0 84.624 0.084 84.648 ;
    END
  END cfg_data[26]
  PIN cfg_data[27]
    DIRECTION INPUT ;
    USE SIGNAL ;
    PORT
      LAYER M4 ;
        RECT  0 84.72 0.084 84.744 ;
    END
  END cfg_data[27]
  PIN cfg_data[28]
    DIRECTION INPUT ;
    USE SIGNAL ;
    PORT
      LAYER M4 ;
        RECT  0 84.816 0.084 84.84 ;
    END
  END cfg_data[28]
  PIN cfg_data[29]
    DIRECTION INPUT ;
    USE SIGNAL ;
    PORT
      LAYER M4 ;
        RECT  0 84.912 0.084 84.936 ;
    END
  END cfg_data[29]
  PIN cfg_data[2]
    DIRECTION INPUT ;
    USE SIGNAL ;
    PORT
      LAYER M4 ;
        RECT  0 82.32 0.084 82.344 ;
    END
  END cfg_data[2]
  PIN cfg_data[30]
    DIRECTION INPUT ;
    USE SIGNAL ;
    PORT
      LAYER M4 ;
        RECT  0 85.008 0.084 85.032 ;
    END
  END cfg_data[30]
  PIN cfg_data[31]
    DIRECTION INPUT ;
    USE SIGNAL ;
    PORT
      LAYER M4 ;
        RECT  0 85.104 0.084 85.128 ;
    END
  END cfg_data[31]
  PIN cfg_data[32]
    DIRECTION INPUT ;
    USE SIGNAL ;
    PORT
      LAYER M4 ;
        RECT  0 85.2 0.084 85.224 ;
    END
  END cfg_data[32]
  PIN cfg_data[33]
    DIRECTION INPUT ;
    USE SIGNAL ;
    PORT
      LAYER M4 ;
        RECT  0 85.296 0.084 85.32 ;
    END
  END cfg_data[33]
  PIN cfg_data[34]
    DIRECTION INPUT ;
    USE SIGNAL ;
    PORT
      LAYER M4 ;
        RECT  0 85.392 0.084 85.416 ;
    END
  END cfg_data[34]
  PIN cfg_data[35]
    DIRECTION INPUT ;
    USE SIGNAL ;
    PORT
      LAYER M4 ;
        RECT  0 85.488 0.084 85.512 ;
    END
  END cfg_data[35]
  PIN cfg_data[36]
    DIRECTION INPUT ;
    USE SIGNAL ;
    PORT
      LAYER M4 ;
        RECT  0 85.584 0.084 85.608 ;
    END
  END cfg_data[36]
  PIN cfg_data[37]
    DIRECTION INPUT ;
    USE SIGNAL ;
    PORT
      LAYER M4 ;
        RECT  0 85.68 0.084 85.704 ;
    END
  END cfg_data[37]
  PIN cfg_data[38]
    DIRECTION INPUT ;
    USE SIGNAL ;
    PORT
      LAYER M4 ;
        RECT  0 85.776 0.084 85.8 ;
    END
  END cfg_data[38]
  PIN cfg_data[39]
    DIRECTION INPUT ;
    USE SIGNAL ;
    PORT
      LAYER M4 ;
        RECT  0 85.872 0.084 85.896 ;
    END
  END cfg_data[39]
  PIN cfg_data[3]
    DIRECTION INPUT ;
    USE SIGNAL ;
    PORT
      LAYER M4 ;
        RECT  0 82.416 0.084 82.44 ;
    END
  END cfg_data[3]
  PIN cfg_data[40]
    DIRECTION INPUT ;
    USE SIGNAL ;
    PORT
      LAYER M4 ;
        RECT  0 85.968 0.084 85.992 ;
    END
  END cfg_data[40]
  PIN cfg_data[41]
    DIRECTION INPUT ;
    USE SIGNAL ;
    PORT
      LAYER M4 ;
        RECT  0 86.064 0.084 86.088 ;
    END
  END cfg_data[41]
  PIN cfg_data[42]
    DIRECTION INPUT ;
    USE SIGNAL ;
    PORT
      LAYER M4 ;
        RECT  0 86.16 0.084 86.184 ;
    END
  END cfg_data[42]
  PIN cfg_data[43]
    DIRECTION INPUT ;
    USE SIGNAL ;
    PORT
      LAYER M4 ;
        RECT  0 86.256 0.084 86.28 ;
    END
  END cfg_data[43]
  PIN cfg_data[44]
    DIRECTION INPUT ;
    USE SIGNAL ;
    PORT
      LAYER M4 ;
        RECT  0 86.352 0.084 86.376 ;
    END
  END cfg_data[44]
  PIN cfg_data[45]
    DIRECTION INPUT ;
    USE SIGNAL ;
    PORT
      LAYER M4 ;
        RECT  0 86.448 0.084 86.472 ;
    END
  END cfg_data[45]
  PIN cfg_data[46]
    DIRECTION INPUT ;
    USE SIGNAL ;
    PORT
      LAYER M4 ;
        RECT  0 86.544 0.084 86.568 ;
    END
  END cfg_data[46]
  PIN cfg_data[47]
    DIRECTION INPUT ;
    USE SIGNAL ;
    PORT
      LAYER M4 ;
        RECT  0 86.64 0.084 86.664 ;
    END
  END cfg_data[47]
  PIN cfg_data[48]
    DIRECTION INPUT ;
    USE SIGNAL ;
    PORT
      LAYER M4 ;
        RECT  0 86.736 0.084 86.76 ;
    END
  END cfg_data[48]
  PIN cfg_data[49]
    DIRECTION INPUT ;
    USE SIGNAL ;
    PORT
      LAYER M4 ;
        RECT  0 86.832 0.084 86.856 ;
    END
  END cfg_data[49]
  PIN cfg_data[4]
    DIRECTION INPUT ;
    USE SIGNAL ;
    PORT
      LAYER M4 ;
        RECT  0 82.512 0.084 82.536 ;
    END
  END cfg_data[4]
  PIN cfg_data[50]
    DIRECTION INPUT ;
    USE SIGNAL ;
    PORT
      LAYER M4 ;
        RECT  0 86.928 0.084 86.952 ;
    END
  END cfg_data[50]
  PIN cfg_data[51]
    DIRECTION INPUT ;
    USE SIGNAL ;
    PORT
      LAYER M4 ;
        RECT  0 87.024 0.084 87.048 ;
    END
  END cfg_data[51]
  PIN cfg_data[52]
    DIRECTION INPUT ;
    USE SIGNAL ;
    PORT
      LAYER M4 ;
        RECT  0 87.12 0.084 87.144 ;
    END
  END cfg_data[52]
  PIN cfg_data[53]
    DIRECTION INPUT ;
    USE SIGNAL ;
    PORT
      LAYER M4 ;
        RECT  0 87.216 0.084 87.24 ;
    END
  END cfg_data[53]
  PIN cfg_data[54]
    DIRECTION INPUT ;
    USE SIGNAL ;
    PORT
      LAYER M4 ;
        RECT  0 87.312 0.084 87.336 ;
    END
  END cfg_data[54]
  PIN cfg_data[55]
    DIRECTION INPUT ;
    USE SIGNAL ;
    PORT
      LAYER M4 ;
        RECT  0 87.408 0.084 87.432 ;
    END
  END cfg_data[55]
  PIN cfg_data[56]
    DIRECTION INPUT ;
    USE SIGNAL ;
    PORT
      LAYER M4 ;
        RECT  0 87.504 0.084 87.528 ;
    END
  END cfg_data[56]
  PIN cfg_data[57]
    DIRECTION INPUT ;
    USE SIGNAL ;
    PORT
      LAYER M4 ;
        RECT  0 87.6 0.084 87.624 ;
    END
  END cfg_data[57]
  PIN cfg_data[58]
    DIRECTION INPUT ;
    USE SIGNAL ;
    PORT
      LAYER M4 ;
        RECT  0 87.696 0.084 87.72 ;
    END
  END cfg_data[58]
  PIN cfg_data[59]
    DIRECTION INPUT ;
    USE SIGNAL ;
    PORT
      LAYER M4 ;
        RECT  0 87.792 0.084 87.816 ;
    END
  END cfg_data[59]
  PIN cfg_data[5]
    DIRECTION INPUT ;
    USE SIGNAL ;
    PORT
      LAYER M4 ;
        RECT  0 82.608 0.084 82.632 ;
    END
  END cfg_data[5]
  PIN cfg_data[60]
    DIRECTION INPUT ;
    USE SIGNAL ;
    PORT
      LAYER M4 ;
        RECT  0 87.888 0.084 87.912 ;
    END
  END cfg_data[60]
  PIN cfg_data[61]
    DIRECTION INPUT ;
    USE SIGNAL ;
    PORT
      LAYER M4 ;
        RECT  0 87.984 0.084 88.008 ;
    END
  END cfg_data[61]
  PIN cfg_data[62]
    DIRECTION INPUT ;
    USE SIGNAL ;
    PORT
      LAYER M4 ;
        RECT  0 88.08 0.084 88.104 ;
    END
  END cfg_data[62]
  PIN cfg_data[63]
    DIRECTION INPUT ;
    USE SIGNAL ;
    PORT
      LAYER M4 ;
        RECT  0 88.176 0.084 88.2 ;
    END
  END cfg_data[63]
  PIN cfg_data[64]
    DIRECTION INPUT ;
    USE SIGNAL ;
    PORT
      LAYER M4 ;
        RECT  0 88.272 0.084 88.296 ;
    END
  END cfg_data[64]
  PIN cfg_data[65]
    DIRECTION INPUT ;
    USE SIGNAL ;
    PORT
      LAYER M4 ;
        RECT  0 88.368 0.084 88.392 ;
    END
  END cfg_data[65]
  PIN cfg_data[66]
    DIRECTION INPUT ;
    USE SIGNAL ;
    PORT
      LAYER M4 ;
        RECT  0 88.464 0.084 88.488 ;
    END
  END cfg_data[66]
  PIN cfg_data[67]
    DIRECTION INPUT ;
    USE SIGNAL ;
    PORT
      LAYER M4 ;
        RECT  0 88.56 0.084 88.584 ;
    END
  END cfg_data[67]
  PIN cfg_data[68]
    DIRECTION INPUT ;
    USE SIGNAL ;
    PORT
      LAYER M4 ;
        RECT  0 88.656 0.084 88.68 ;
    END
  END cfg_data[68]
  PIN cfg_data[69]
    DIRECTION INPUT ;
    USE SIGNAL ;
    PORT
      LAYER M4 ;
        RECT  0 88.752 0.084 88.776 ;
    END
  END cfg_data[69]
  PIN cfg_data[6]
    DIRECTION INPUT ;
    USE SIGNAL ;
    PORT
      LAYER M4 ;
        RECT  0 82.704 0.084 82.728 ;
    END
  END cfg_data[6]
  PIN cfg_data[70]
    DIRECTION INPUT ;
    USE SIGNAL ;
    PORT
      LAYER M4 ;
        RECT  0 88.848 0.084 88.872 ;
    END
  END cfg_data[70]
  PIN cfg_data[71]
    DIRECTION INPUT ;
    USE SIGNAL ;
    PORT
      LAYER M4 ;
        RECT  0 88.944 0.084 88.968 ;
    END
  END cfg_data[71]
  PIN cfg_data[72]
    DIRECTION INPUT ;
    USE SIGNAL ;
    PORT
      LAYER M4 ;
        RECT  0 89.04 0.084 89.064 ;
    END
  END cfg_data[72]
  PIN cfg_data[73]
    DIRECTION INPUT ;
    USE SIGNAL ;
    PORT
      LAYER M4 ;
        RECT  0 89.136 0.084 89.16 ;
    END
  END cfg_data[73]
  PIN cfg_data[74]
    DIRECTION INPUT ;
    USE SIGNAL ;
    PORT
      LAYER M4 ;
        RECT  0 89.232 0.084 89.256 ;
    END
  END cfg_data[74]
  PIN cfg_data[75]
    DIRECTION INPUT ;
    USE SIGNAL ;
    PORT
      LAYER M4 ;
        RECT  0 89.328 0.084 89.352 ;
    END
  END cfg_data[75]
  PIN cfg_data[76]
    DIRECTION INPUT ;
    USE SIGNAL ;
    PORT
      LAYER M4 ;
        RECT  0 89.424 0.084 89.448 ;
    END
  END cfg_data[76]
  PIN cfg_data[77]
    DIRECTION INPUT ;
    USE SIGNAL ;
    PORT
      LAYER M4 ;
        RECT  0 89.52 0.084 89.544 ;
    END
  END cfg_data[77]
  PIN cfg_data[78]
    DIRECTION INPUT ;
    USE SIGNAL ;
    PORT
      LAYER M4 ;
        RECT  0 89.616 0.084 89.64 ;
    END
  END cfg_data[78]
  PIN cfg_data[79]
    DIRECTION INPUT ;
    USE SIGNAL ;
    PORT
      LAYER M4 ;
        RECT  0 89.712 0.084 89.736 ;
    END
  END cfg_data[79]
  PIN cfg_data[7]
    DIRECTION INPUT ;
    USE SIGNAL ;
    PORT
      LAYER M4 ;
        RECT  0 82.8 0.084 82.824 ;
    END
  END cfg_data[7]
  PIN cfg_data[80]
    DIRECTION INPUT ;
    USE SIGNAL ;
    PORT
      LAYER M4 ;
        RECT  0 89.808 0.084 89.832 ;
    END
  END cfg_data[80]
  PIN cfg_data[81]
    DIRECTION INPUT ;
    USE SIGNAL ;
    PORT
      LAYER M4 ;
        RECT  0 89.904 0.084 89.928 ;
    END
  END cfg_data[81]
  PIN cfg_data[82]
    DIRECTION INPUT ;
    USE SIGNAL ;
    PORT
      LAYER M4 ;
        RECT  0 90 0.084 90.024 ;
    END
  END cfg_data[82]
  PIN cfg_data[83]
    DIRECTION INPUT ;
    USE SIGNAL ;
    PORT
      LAYER M4 ;
        RECT  0 90.096 0.084 90.12 ;
    END
  END cfg_data[83]
  PIN cfg_data[84]
    DIRECTION INPUT ;
    USE SIGNAL ;
    PORT
      LAYER M4 ;
        RECT  0 90.192 0.084 90.216 ;
    END
  END cfg_data[84]
  PIN cfg_data[85]
    DIRECTION INPUT ;
    USE SIGNAL ;
    PORT
      LAYER M4 ;
        RECT  0 90.288 0.084 90.312 ;
    END
  END cfg_data[85]
  PIN cfg_data[86]
    DIRECTION INPUT ;
    USE SIGNAL ;
    PORT
      LAYER M4 ;
        RECT  0 90.384 0.084 90.408 ;
    END
  END cfg_data[86]
  PIN cfg_data[87]
    DIRECTION INPUT ;
    USE SIGNAL ;
    PORT
      LAYER M4 ;
        RECT  0 90.48 0.084 90.504 ;
    END
  END cfg_data[87]
  PIN cfg_data[88]
    DIRECTION INPUT ;
    USE SIGNAL ;
    PORT
      LAYER M4 ;
        RECT  0 90.576 0.084 90.6 ;
    END
  END cfg_data[88]
  PIN cfg_data[89]
    DIRECTION INPUT ;
    USE SIGNAL ;
    PORT
      LAYER M4 ;
        RECT  0 90.672 0.084 90.696 ;
    END
  END cfg_data[89]
  PIN cfg_data[8]
    DIRECTION INPUT ;
    USE SIGNAL ;
    PORT
      LAYER M4 ;
        RECT  0 82.896 0.084 82.92 ;
    END
  END cfg_data[8]
  PIN cfg_data[90]
    DIRECTION INPUT ;
    USE SIGNAL ;
    PORT
      LAYER M4 ;
        RECT  0 90.768 0.084 90.792 ;
    END
  END cfg_data[90]
  PIN cfg_data[91]
    DIRECTION INPUT ;
    USE SIGNAL ;
    PORT
      LAYER M4 ;
        RECT  0 90.864 0.084 90.888 ;
    END
  END cfg_data[91]
  PIN cfg_data[92]
    DIRECTION INPUT ;
    USE SIGNAL ;
    PORT
      LAYER M4 ;
        RECT  0 90.96 0.084 90.984 ;
    END
  END cfg_data[92]
  PIN cfg_data[93]
    DIRECTION INPUT ;
    USE SIGNAL ;
    PORT
      LAYER M4 ;
        RECT  0 91.056 0.084 91.08 ;
    END
  END cfg_data[93]
  PIN cfg_data[94]
    DIRECTION INPUT ;
    USE SIGNAL ;
    PORT
      LAYER M4 ;
        RECT  0 91.152 0.084 91.176 ;
    END
  END cfg_data[94]
  PIN cfg_data[95]
    DIRECTION INPUT ;
    USE SIGNAL ;
    PORT
      LAYER M4 ;
        RECT  0 91.248 0.084 91.272 ;
    END
  END cfg_data[95]
  PIN cfg_data[96]
    DIRECTION INPUT ;
    USE SIGNAL ;
    PORT
      LAYER M4 ;
        RECT  0 91.344 0.084 91.368 ;
    END
  END cfg_data[96]
  PIN cfg_data[97]
    DIRECTION INPUT ;
    USE SIGNAL ;
    PORT
      LAYER M4 ;
        RECT  0 91.44 0.084 91.464 ;
    END
  END cfg_data[97]
  PIN cfg_data[98]
    DIRECTION INPUT ;
    USE SIGNAL ;
    PORT
      LAYER M4 ;
        RECT  0 91.536 0.084 91.56 ;
    END
  END cfg_data[98]
  PIN cfg_data[99]
    DIRECTION INPUT ;
    USE SIGNAL ;
    PORT
      LAYER M4 ;
        RECT  0 91.632 0.084 91.656 ;
    END
  END cfg_data[99]
  PIN cfg_data[9]
    DIRECTION INPUT ;
    USE SIGNAL ;
    PORT
      LAYER M4 ;
        RECT  0 82.992 0.084 83.016 ;
    END
  END cfg_data[9]
  PIN cfg_we
    DIRECTION INPUT ;
    USE SIGNAL ;
    PORT
      LAYER M4 ;
        RECT  0 49.872 0.084 49.896 ;
    END
  END cfg_we
  PIN client_seq[0]
    DIRECTION OUTPUT ;
    USE SIGNAL ;
    PORT
      LAYER M4 ;
        RECT  220.236 56.016 220.32 56.04 ;
    END
  END client_seq[0]
  PIN client_seq[1]
    DIRECTION OUTPUT ;
    USE SIGNAL ;
    PORT
      LAYER M4 ;
        RECT  220.236 56.112 220.32 56.136 ;
    END
  END client_seq[1]
  PIN clk
    DIRECTION INPUT ;
    USE SIGNAL ;
    PORT
      LAYER M4 ;
        RECT  0 49.968 0.084 49.992 ;
    END
  END clk
  PIN done
    DIRECTION OUTPUT ;
    USE SIGNAL ;
    PORT
      LAYER M5 ;
        RECT  16.272 0 16.296 0.084 ;
    END
  END done
  PIN fault
    DIRECTION OUTPUT ;
    USE SIGNAL ;
    PORT
      LAYER M5 ;
        RECT  16.368 0 16.392 0.084 ;
    END
  END fault
  PIN hub_ring_client[0]
    DIRECTION OUTPUT ;
    USE SIGNAL ;
    PORT
      LAYER M4 ;
        RECT  220.236 56.208 220.32 56.232 ;
    END
  END hub_ring_client[0]
  PIN hub_ring_client[1]
    DIRECTION OUTPUT ;
    USE SIGNAL ;
    PORT
      LAYER M4 ;
        RECT  220.236 56.304 220.32 56.328 ;
    END
  END hub_ring_client[1]
  PIN hub_ring_enable[0]
    DIRECTION OUTPUT ;
    USE SIGNAL ;
    PORT
      LAYER M4 ;
        RECT  220.236 56.4 220.32 56.424 ;
    END
  END hub_ring_enable[0]
  PIN hub_ring_enable[1]
    DIRECTION OUTPUT ;
    USE SIGNAL ;
    PORT
      LAYER M4 ;
        RECT  220.236 56.496 220.32 56.52 ;
    END
  END hub_ring_enable[1]
  PIN lg_local_read[0]
    DIRECTION OUTPUT ;
    USE SIGNAL ;
    PORT
      LAYER M4 ;
        RECT  220.236 56.592 220.32 56.616 ;
    END
  END lg_local_read[0]
  PIN lg_local_read[10]
    DIRECTION OUTPUT ;
    USE SIGNAL ;
    PORT
      LAYER M4 ;
        RECT  220.236 67.536 220.32 67.56 ;
    END
  END lg_local_read[10]
  PIN lg_local_read[11]
    DIRECTION OUTPUT ;
    USE SIGNAL ;
    PORT
      LAYER M4 ;
        RECT  220.236 67.632 220.32 67.656 ;
    END
  END lg_local_read[11]
  PIN lg_local_read[12]
    DIRECTION OUTPUT ;
    USE SIGNAL ;
    PORT
      LAYER M4 ;
        RECT  220.236 67.728 220.32 67.752 ;
    END
  END lg_local_read[12]
  PIN lg_local_read[13]
    DIRECTION OUTPUT ;
    USE SIGNAL ;
    PORT
      LAYER M4 ;
        RECT  220.236 67.824 220.32 67.848 ;
    END
  END lg_local_read[13]
  PIN lg_local_read[14]
    DIRECTION OUTPUT ;
    USE SIGNAL ;
    PORT
      LAYER M4 ;
        RECT  220.236 67.92 220.32 67.944 ;
    END
  END lg_local_read[14]
  PIN lg_local_read[15]
    DIRECTION OUTPUT ;
    USE SIGNAL ;
    PORT
      LAYER M4 ;
        RECT  220.236 68.016 220.32 68.04 ;
    END
  END lg_local_read[15]
  PIN lg_local_read[16]
    DIRECTION OUTPUT ;
    USE SIGNAL ;
    PORT
      LAYER M4 ;
        RECT  220.236 68.112 220.32 68.136 ;
    END
  END lg_local_read[16]
  PIN lg_local_read[17]
    DIRECTION OUTPUT ;
    USE SIGNAL ;
    PORT
      LAYER M4 ;
        RECT  220.236 68.208 220.32 68.232 ;
    END
  END lg_local_read[17]
  PIN lg_local_read[18]
    DIRECTION OUTPUT ;
    USE SIGNAL ;
    PORT
      LAYER M4 ;
        RECT  220.236 68.304 220.32 68.328 ;
    END
  END lg_local_read[18]
  PIN lg_local_read[19]
    DIRECTION OUTPUT ;
    USE SIGNAL ;
    PORT
      LAYER M4 ;
        RECT  220.236 68.4 220.32 68.424 ;
    END
  END lg_local_read[19]
  PIN lg_local_read[1]
    DIRECTION OUTPUT ;
    USE SIGNAL ;
    PORT
      LAYER M4 ;
        RECT  220.236 56.688 220.32 56.712 ;
    END
  END lg_local_read[1]
  PIN lg_local_read[20]
    DIRECTION OUTPUT ;
    USE SIGNAL ;
    PORT
      LAYER M4 ;
        RECT  220.236 68.496 220.32 68.52 ;
    END
  END lg_local_read[20]
  PIN lg_local_read[21]
    DIRECTION OUTPUT ;
    USE SIGNAL ;
    PORT
      LAYER M4 ;
        RECT  220.236 68.592 220.32 68.616 ;
    END
  END lg_local_read[21]
  PIN lg_local_read[22]
    DIRECTION OUTPUT ;
    USE SIGNAL ;
    PORT
      LAYER M4 ;
        RECT  220.236 68.688 220.32 68.712 ;
    END
  END lg_local_read[22]
  PIN lg_local_read[23]
    DIRECTION OUTPUT ;
    USE SIGNAL ;
    PORT
      LAYER M4 ;
        RECT  220.236 68.784 220.32 68.808 ;
    END
  END lg_local_read[23]
  PIN lg_local_read[2]
    DIRECTION OUTPUT ;
    USE SIGNAL ;
    PORT
      LAYER M4 ;
        RECT  220.236 56.784 220.32 56.808 ;
    END
  END lg_local_read[2]
  PIN lg_local_read[3]
    DIRECTION OUTPUT ;
    USE SIGNAL ;
    PORT
      LAYER M4 ;
        RECT  220.236 56.88 220.32 56.904 ;
    END
  END lg_local_read[3]
  PIN lg_local_read[4]
    DIRECTION OUTPUT ;
    USE SIGNAL ;
    PORT
      LAYER M4 ;
        RECT  220.236 56.976 220.32 57 ;
    END
  END lg_local_read[4]
  PIN lg_local_read[5]
    DIRECTION OUTPUT ;
    USE SIGNAL ;
    PORT
      LAYER M4 ;
        RECT  220.236 57.072 220.32 57.096 ;
    END
  END lg_local_read[5]
  PIN lg_local_read[6]
    DIRECTION OUTPUT ;
    USE SIGNAL ;
    PORT
      LAYER M4 ;
        RECT  220.236 57.168 220.32 57.192 ;
    END
  END lg_local_read[6]
  PIN lg_local_read[7]
    DIRECTION OUTPUT ;
    USE SIGNAL ;
    PORT
      LAYER M4 ;
        RECT  220.236 57.264 220.32 57.288 ;
    END
  END lg_local_read[7]
  PIN lg_local_read[8]
    DIRECTION OUTPUT ;
    USE SIGNAL ;
    PORT
      LAYER M4 ;
        RECT  220.236 57.36 220.32 57.384 ;
    END
  END lg_local_read[8]
  PIN lg_local_read[9]
    DIRECTION OUTPUT ;
    USE SIGNAL ;
    PORT
      LAYER M4 ;
        RECT  220.236 57.456 220.32 57.48 ;
    END
  END lg_local_read[9]
  PIN lg_local_write[0]
    DIRECTION OUTPUT ;
    USE SIGNAL ;
    PORT
      LAYER M4 ;
        RECT  220.236 68.88 220.32 68.904 ;
    END
  END lg_local_write[0]
  PIN lg_local_write[10]
    DIRECTION OUTPUT ;
    USE SIGNAL ;
    PORT
      LAYER M4 ;
        RECT  220.236 69.84 220.32 69.864 ;
    END
  END lg_local_write[10]
  PIN lg_local_write[11]
    DIRECTION OUTPUT ;
    USE SIGNAL ;
    PORT
      LAYER M4 ;
        RECT  220.236 69.936 220.32 69.96 ;
    END
  END lg_local_write[11]
  PIN lg_local_write[12]
    DIRECTION OUTPUT ;
    USE SIGNAL ;
    PORT
      LAYER M4 ;
        RECT  220.236 70.032 220.32 70.056 ;
    END
  END lg_local_write[12]
  PIN lg_local_write[13]
    DIRECTION OUTPUT ;
    USE SIGNAL ;
    PORT
      LAYER M4 ;
        RECT  220.236 70.128 220.32 70.152 ;
    END
  END lg_local_write[13]
  PIN lg_local_write[14]
    DIRECTION OUTPUT ;
    USE SIGNAL ;
    PORT
      LAYER M4 ;
        RECT  220.236 70.224 220.32 70.248 ;
    END
  END lg_local_write[14]
  PIN lg_local_write[15]
    DIRECTION OUTPUT ;
    USE SIGNAL ;
    PORT
      LAYER M4 ;
        RECT  220.236 70.32 220.32 70.344 ;
    END
  END lg_local_write[15]
  PIN lg_local_write[16]
    DIRECTION OUTPUT ;
    USE SIGNAL ;
    PORT
      LAYER M4 ;
        RECT  220.236 70.416 220.32 70.44 ;
    END
  END lg_local_write[16]
  PIN lg_local_write[17]
    DIRECTION OUTPUT ;
    USE SIGNAL ;
    PORT
      LAYER M4 ;
        RECT  220.236 70.512 220.32 70.536 ;
    END
  END lg_local_write[17]
  PIN lg_local_write[18]
    DIRECTION OUTPUT ;
    USE SIGNAL ;
    PORT
      LAYER M4 ;
        RECT  220.236 64.464 220.32 64.488 ;
    END
  END lg_local_write[18]
  PIN lg_local_write[19]
    DIRECTION OUTPUT ;
    USE SIGNAL ;
    PORT
      LAYER M4 ;
        RECT  220.236 64.56 220.32 64.584 ;
    END
  END lg_local_write[19]
  PIN lg_local_write[1]
    DIRECTION OUTPUT ;
    USE SIGNAL ;
    PORT
      LAYER M4 ;
        RECT  220.236 68.976 220.32 69 ;
    END
  END lg_local_write[1]
  PIN lg_local_write[20]
    DIRECTION OUTPUT ;
    USE SIGNAL ;
    PORT
      LAYER M4 ;
        RECT  220.236 64.656 220.32 64.68 ;
    END
  END lg_local_write[20]
  PIN lg_local_write[21]
    DIRECTION OUTPUT ;
    USE SIGNAL ;
    PORT
      LAYER M4 ;
        RECT  220.236 64.752 220.32 64.776 ;
    END
  END lg_local_write[21]
  PIN lg_local_write[22]
    DIRECTION OUTPUT ;
    USE SIGNAL ;
    PORT
      LAYER M4 ;
        RECT  220.236 64.848 220.32 64.872 ;
    END
  END lg_local_write[22]
  PIN lg_local_write[23]
    DIRECTION OUTPUT ;
    USE SIGNAL ;
    PORT
      LAYER M4 ;
        RECT  220.236 64.944 220.32 64.968 ;
    END
  END lg_local_write[23]
  PIN lg_local_write[2]
    DIRECTION OUTPUT ;
    USE SIGNAL ;
    PORT
      LAYER M4 ;
        RECT  220.236 69.072 220.32 69.096 ;
    END
  END lg_local_write[2]
  PIN lg_local_write[3]
    DIRECTION OUTPUT ;
    USE SIGNAL ;
    PORT
      LAYER M4 ;
        RECT  220.236 69.168 220.32 69.192 ;
    END
  END lg_local_write[3]
  PIN lg_local_write[4]
    DIRECTION OUTPUT ;
    USE SIGNAL ;
    PORT
      LAYER M4 ;
        RECT  220.236 69.264 220.32 69.288 ;
    END
  END lg_local_write[4]
  PIN lg_local_write[5]
    DIRECTION OUTPUT ;
    USE SIGNAL ;
    PORT
      LAYER M4 ;
        RECT  220.236 69.36 220.32 69.384 ;
    END
  END lg_local_write[5]
  PIN lg_local_write[6]
    DIRECTION OUTPUT ;
    USE SIGNAL ;
    PORT
      LAYER M4 ;
        RECT  220.236 69.456 220.32 69.48 ;
    END
  END lg_local_write[6]
  PIN lg_local_write[7]
    DIRECTION OUTPUT ;
    USE SIGNAL ;
    PORT
      LAYER M4 ;
        RECT  220.236 69.552 220.32 69.576 ;
    END
  END lg_local_write[7]
  PIN lg_local_write[8]
    DIRECTION OUTPUT ;
    USE SIGNAL ;
    PORT
      LAYER M4 ;
        RECT  220.236 69.648 220.32 69.672 ;
    END
  END lg_local_write[8]
  PIN lg_local_write[9]
    DIRECTION OUTPUT ;
    USE SIGNAL ;
    PORT
      LAYER M4 ;
        RECT  220.236 69.744 220.32 69.768 ;
    END
  END lg_local_write[9]
  PIN ordinal[0]
    DIRECTION OUTPUT ;
    USE SIGNAL ;
    PORT
      LAYER M5 ;
        RECT  16.464 0 16.488 0.084 ;
    END
  END ordinal[0]
  PIN ordinal[10]
    DIRECTION OUTPUT ;
    USE SIGNAL ;
    PORT
      LAYER M5 ;
        RECT  17.424 0 17.448 0.084 ;
    END
  END ordinal[10]
  PIN ordinal[11]
    DIRECTION OUTPUT ;
    USE SIGNAL ;
    PORT
      LAYER M5 ;
        RECT  17.52 0 17.544 0.084 ;
    END
  END ordinal[11]
  PIN ordinal[12]
    DIRECTION OUTPUT ;
    USE SIGNAL ;
    PORT
      LAYER M5 ;
        RECT  17.616 0 17.64 0.084 ;
    END
  END ordinal[12]
  PIN ordinal[13]
    DIRECTION OUTPUT ;
    USE SIGNAL ;
    PORT
      LAYER M5 ;
        RECT  17.712 0 17.736 0.084 ;
    END
  END ordinal[13]
  PIN ordinal[14]
    DIRECTION OUTPUT ;
    USE SIGNAL ;
    PORT
      LAYER M5 ;
        RECT  17.808 0 17.832 0.084 ;
    END
  END ordinal[14]
  PIN ordinal[15]
    DIRECTION OUTPUT ;
    USE SIGNAL ;
    PORT
      LAYER M5 ;
        RECT  17.904 0 17.928 0.084 ;
    END
  END ordinal[15]
  PIN ordinal[16]
    DIRECTION OUTPUT ;
    USE SIGNAL ;
    PORT
      LAYER M5 ;
        RECT  18 0 18.024 0.084 ;
    END
  END ordinal[16]
  PIN ordinal[17]
    DIRECTION OUTPUT ;
    USE SIGNAL ;
    PORT
      LAYER M5 ;
        RECT  18.096 0 18.12 0.084 ;
    END
  END ordinal[17]
  PIN ordinal[18]
    DIRECTION OUTPUT ;
    USE SIGNAL ;
    PORT
      LAYER M5 ;
        RECT  18.192 0 18.216 0.084 ;
    END
  END ordinal[18]
  PIN ordinal[19]
    DIRECTION OUTPUT ;
    USE SIGNAL ;
    PORT
      LAYER M5 ;
        RECT  18.288 0 18.312 0.084 ;
    END
  END ordinal[19]
  PIN ordinal[1]
    DIRECTION OUTPUT ;
    USE SIGNAL ;
    PORT
      LAYER M5 ;
        RECT  16.56 0 16.584 0.084 ;
    END
  END ordinal[1]
  PIN ordinal[20]
    DIRECTION OUTPUT ;
    USE SIGNAL ;
    PORT
      LAYER M5 ;
        RECT  18.384 0 18.408 0.084 ;
    END
  END ordinal[20]
  PIN ordinal[21]
    DIRECTION OUTPUT ;
    USE SIGNAL ;
    PORT
      LAYER M5 ;
        RECT  18.48 0 18.504 0.084 ;
    END
  END ordinal[21]
  PIN ordinal[22]
    DIRECTION OUTPUT ;
    USE SIGNAL ;
    PORT
      LAYER M5 ;
        RECT  18.576 0 18.6 0.084 ;
    END
  END ordinal[22]
  PIN ordinal[23]
    DIRECTION OUTPUT ;
    USE SIGNAL ;
    PORT
      LAYER M5 ;
        RECT  18.672 0 18.696 0.084 ;
    END
  END ordinal[23]
  PIN ordinal[24]
    DIRECTION OUTPUT ;
    USE SIGNAL ;
    PORT
      LAYER M5 ;
        RECT  18.768 0 18.792 0.084 ;
    END
  END ordinal[24]
  PIN ordinal[25]
    DIRECTION OUTPUT ;
    USE SIGNAL ;
    PORT
      LAYER M5 ;
        RECT  18.864 0 18.888 0.084 ;
    END
  END ordinal[25]
  PIN ordinal[26]
    DIRECTION OUTPUT ;
    USE SIGNAL ;
    PORT
      LAYER M5 ;
        RECT  18.96 0 18.984 0.084 ;
    END
  END ordinal[26]
  PIN ordinal[27]
    DIRECTION OUTPUT ;
    USE SIGNAL ;
    PORT
      LAYER M5 ;
        RECT  19.056 0 19.08 0.084 ;
    END
  END ordinal[27]
  PIN ordinal[28]
    DIRECTION OUTPUT ;
    USE SIGNAL ;
    PORT
      LAYER M5 ;
        RECT  6.864 0 6.888 0.084 ;
    END
  END ordinal[28]
  PIN ordinal[29]
    DIRECTION OUTPUT ;
    USE SIGNAL ;
    PORT
      LAYER M5 ;
        RECT  6.96 0 6.984 0.084 ;
    END
  END ordinal[29]
  PIN ordinal[2]
    DIRECTION OUTPUT ;
    USE SIGNAL ;
    PORT
      LAYER M5 ;
        RECT  16.656 0 16.68 0.084 ;
    END
  END ordinal[2]
  PIN ordinal[30]
    DIRECTION OUTPUT ;
    USE SIGNAL ;
    PORT
      LAYER M5 ;
        RECT  7.056 0 7.08 0.084 ;
    END
  END ordinal[30]
  PIN ordinal[31]
    DIRECTION OUTPUT ;
    USE SIGNAL ;
    PORT
      LAYER M5 ;
        RECT  7.152 0 7.176 0.084 ;
    END
  END ordinal[31]
  PIN ordinal[3]
    DIRECTION OUTPUT ;
    USE SIGNAL ;
    PORT
      LAYER M5 ;
        RECT  16.752 0 16.776 0.084 ;
    END
  END ordinal[3]
  PIN ordinal[4]
    DIRECTION OUTPUT ;
    USE SIGNAL ;
    PORT
      LAYER M5 ;
        RECT  16.848 0 16.872 0.084 ;
    END
  END ordinal[4]
  PIN ordinal[5]
    DIRECTION OUTPUT ;
    USE SIGNAL ;
    PORT
      LAYER M5 ;
        RECT  16.944 0 16.968 0.084 ;
    END
  END ordinal[5]
  PIN ordinal[6]
    DIRECTION OUTPUT ;
    USE SIGNAL ;
    PORT
      LAYER M5 ;
        RECT  17.04 0 17.064 0.084 ;
    END
  END ordinal[6]
  PIN ordinal[7]
    DIRECTION OUTPUT ;
    USE SIGNAL ;
    PORT
      LAYER M5 ;
        RECT  17.136 0 17.16 0.084 ;
    END
  END ordinal[7]
  PIN ordinal[8]
    DIRECTION OUTPUT ;
    USE SIGNAL ;
    PORT
      LAYER M5 ;
        RECT  17.232 0 17.256 0.084 ;
    END
  END ordinal[8]
  PIN ordinal[9]
    DIRECTION OUTPUT ;
    USE SIGNAL ;
    PORT
      LAYER M5 ;
        RECT  17.328 0 17.352 0.084 ;
    END
  END ordinal[9]
  PIN replay_enable
    DIRECTION OUTPUT ;
    USE SIGNAL ;
    PORT
      LAYER M4 ;
        RECT  220.236 65.04 220.32 65.064 ;
    END
  END replay_enable
  PIN replay_source
    DIRECTION OUTPUT ;
    USE SIGNAL ;
    PORT
      LAYER M4 ;
        RECT  220.236 65.136 220.32 65.16 ;
    END
  END replay_source
  PIN response_enable
    DIRECTION OUTPUT ;
    USE SIGNAL ;
    PORT
      LAYER M4 ;
        RECT  220.236 65.232 220.32 65.256 ;
    END
  END response_enable
  PIN response_seq[0]
    DIRECTION OUTPUT ;
    USE SIGNAL ;
    PORT
      LAYER M4 ;
        RECT  220.236 65.328 220.32 65.352 ;
    END
  END response_seq[0]
  PIN response_seq[1]
    DIRECTION OUTPUT ;
    USE SIGNAL ;
    PORT
      LAYER M4 ;
        RECT  220.236 65.424 220.32 65.448 ;
    END
  END response_seq[1]
  PIN ring_tx_enable[0]
    DIRECTION OUTPUT ;
    USE SIGNAL ;
    PORT
      LAYER M4 ;
        RECT  220.236 65.52 220.32 65.544 ;
    END
  END ring_tx_enable[0]
  PIN ring_tx_enable[1]
    DIRECTION OUTPUT ;
    USE SIGNAL ;
    PORT
      LAYER M4 ;
        RECT  220.236 65.616 220.32 65.64 ;
    END
  END ring_tx_enable[1]
  PIN ring_tx_source[0]
    DIRECTION OUTPUT ;
    USE SIGNAL ;
    PORT
      LAYER M4 ;
        RECT  220.236 65.712 220.32 65.736 ;
    END
  END ring_tx_source[0]
  PIN ring_tx_source[1]
    DIRECTION OUTPUT ;
    USE SIGNAL ;
    PORT
      LAYER M4 ;
        RECT  220.236 65.808 220.32 65.832 ;
    END
  END ring_tx_source[1]
  PIN ring_tx_source[2]
    DIRECTION OUTPUT ;
    USE SIGNAL ;
    PORT
      LAYER M4 ;
        RECT  220.236 65.904 220.32 65.928 ;
    END
  END ring_tx_source[2]
  PIN ring_tx_source[3]
    DIRECTION OUTPUT ;
    USE SIGNAL ;
    PORT
      LAYER M4 ;
        RECT  220.236 66 220.32 66.024 ;
    END
  END ring_tx_source[3]
  PIN ring_tx_source[4]
    DIRECTION OUTPUT ;
    USE SIGNAL ;
    PORT
      LAYER M4 ;
        RECT  220.236 66.096 220.32 66.12 ;
    END
  END ring_tx_source[4]
  PIN ring_tx_source[5]
    DIRECTION OUTPUT ;
    USE SIGNAL ;
    PORT
      LAYER M4 ;
        RECT  220.236 66.192 220.32 66.216 ;
    END
  END ring_tx_source[5]
  PIN rslot[0]
    DIRECTION OUTPUT ;
    USE SIGNAL ;
    PORT
      LAYER M4 ;
        RECT  220.236 66.288 220.32 66.312 ;
    END
  END rslot[0]
  PIN rslot[10]
    DIRECTION OUTPUT ;
    USE SIGNAL ;
    PORT
      LAYER M4 ;
        RECT  220.236 67.248 220.32 67.272 ;
    END
  END rslot[10]
  PIN rslot[11]
    DIRECTION OUTPUT ;
    USE SIGNAL ;
    PORT
      LAYER M4 ;
        RECT  220.236 67.344 220.32 67.368 ;
    END
  END rslot[11]
  PIN rslot[12]
    DIRECTION OUTPUT ;
    USE SIGNAL ;
    PORT
      LAYER M4 ;
        RECT  220.236 67.44 220.32 67.464 ;
    END
  END rslot[12]
  PIN rslot[13]
    DIRECTION OUTPUT ;
    USE SIGNAL ;
    PORT
      LAYER M4 ;
        RECT  220.236 61.392 220.32 61.416 ;
    END
  END rslot[13]
  PIN rslot[14]
    DIRECTION OUTPUT ;
    USE SIGNAL ;
    PORT
      LAYER M4 ;
        RECT  220.236 61.488 220.32 61.512 ;
    END
  END rslot[14]
  PIN rslot[15]
    DIRECTION OUTPUT ;
    USE SIGNAL ;
    PORT
      LAYER M4 ;
        RECT  220.236 61.584 220.32 61.608 ;
    END
  END rslot[15]
  PIN rslot[16]
    DIRECTION OUTPUT ;
    USE SIGNAL ;
    PORT
      LAYER M4 ;
        RECT  220.236 61.68 220.32 61.704 ;
    END
  END rslot[16]
  PIN rslot[17]
    DIRECTION OUTPUT ;
    USE SIGNAL ;
    PORT
      LAYER M4 ;
        RECT  220.236 61.776 220.32 61.8 ;
    END
  END rslot[17]
  PIN rslot[18]
    DIRECTION OUTPUT ;
    USE SIGNAL ;
    PORT
      LAYER M4 ;
        RECT  220.236 61.872 220.32 61.896 ;
    END
  END rslot[18]
  PIN rslot[19]
    DIRECTION OUTPUT ;
    USE SIGNAL ;
    PORT
      LAYER M4 ;
        RECT  220.236 61.968 220.32 61.992 ;
    END
  END rslot[19]
  PIN rslot[1]
    DIRECTION OUTPUT ;
    USE SIGNAL ;
    PORT
      LAYER M4 ;
        RECT  220.236 66.384 220.32 66.408 ;
    END
  END rslot[1]
  PIN rslot[20]
    DIRECTION OUTPUT ;
    USE SIGNAL ;
    PORT
      LAYER M4 ;
        RECT  220.236 62.064 220.32 62.088 ;
    END
  END rslot[20]
  PIN rslot[21]
    DIRECTION OUTPUT ;
    USE SIGNAL ;
    PORT
      LAYER M4 ;
        RECT  220.236 62.16 220.32 62.184 ;
    END
  END rslot[21]
  PIN rslot[22]
    DIRECTION OUTPUT ;
    USE SIGNAL ;
    PORT
      LAYER M4 ;
        RECT  220.236 62.256 220.32 62.28 ;
    END
  END rslot[22]
  PIN rslot[23]
    DIRECTION OUTPUT ;
    USE SIGNAL ;
    PORT
      LAYER M4 ;
        RECT  220.236 62.352 220.32 62.376 ;
    END
  END rslot[23]
  PIN rslot[2]
    DIRECTION OUTPUT ;
    USE SIGNAL ;
    PORT
      LAYER M4 ;
        RECT  220.236 66.48 220.32 66.504 ;
    END
  END rslot[2]
  PIN rslot[3]
    DIRECTION OUTPUT ;
    USE SIGNAL ;
    PORT
      LAYER M4 ;
        RECT  220.236 66.576 220.32 66.6 ;
    END
  END rslot[3]
  PIN rslot[4]
    DIRECTION OUTPUT ;
    USE SIGNAL ;
    PORT
      LAYER M4 ;
        RECT  220.236 66.672 220.32 66.696 ;
    END
  END rslot[4]
  PIN rslot[5]
    DIRECTION OUTPUT ;
    USE SIGNAL ;
    PORT
      LAYER M4 ;
        RECT  220.236 66.768 220.32 66.792 ;
    END
  END rslot[5]
  PIN rslot[6]
    DIRECTION OUTPUT ;
    USE SIGNAL ;
    PORT
      LAYER M4 ;
        RECT  220.236 66.864 220.32 66.888 ;
    END
  END rslot[6]
  PIN rslot[7]
    DIRECTION OUTPUT ;
    USE SIGNAL ;
    PORT
      LAYER M4 ;
        RECT  220.236 66.96 220.32 66.984 ;
    END
  END rslot[7]
  PIN rslot[8]
    DIRECTION OUTPUT ;
    USE SIGNAL ;
    PORT
      LAYER M4 ;
        RECT  220.236 67.056 220.32 67.08 ;
    END
  END rslot[8]
  PIN rslot[9]
    DIRECTION OUTPUT ;
    USE SIGNAL ;
    PORT
      LAYER M4 ;
        RECT  220.236 67.152 220.32 67.176 ;
    END
  END rslot[9]
  PIN rslot_v[0]
    DIRECTION OUTPUT ;
    USE SIGNAL ;
    PORT
      LAYER M4 ;
        RECT  220.236 62.448 220.32 62.472 ;
    END
  END rslot_v[0]
  PIN rslot_v[1]
    DIRECTION OUTPUT ;
    USE SIGNAL ;
    PORT
      LAYER M4 ;
        RECT  220.236 62.544 220.32 62.568 ;
    END
  END rslot_v[1]
  PIN rslot_v[2]
    DIRECTION OUTPUT ;
    USE SIGNAL ;
    PORT
      LAYER M4 ;
        RECT  220.236 62.64 220.32 62.664 ;
    END
  END rslot_v[2]
  PIN rslot_v[3]
    DIRECTION OUTPUT ;
    USE SIGNAL ;
    PORT
      LAYER M4 ;
        RECT  220.236 62.736 220.32 62.76 ;
    END
  END rslot_v[3]
  PIN rslot_v[4]
    DIRECTION OUTPUT ;
    USE SIGNAL ;
    PORT
      LAYER M4 ;
        RECT  220.236 62.832 220.32 62.856 ;
    END
  END rslot_v[4]
  PIN rslot_v[5]
    DIRECTION OUTPUT ;
    USE SIGNAL ;
    PORT
      LAYER M4 ;
        RECT  220.236 62.928 220.32 62.952 ;
    END
  END rslot_v[5]
  PIN rslot_v[6]
    DIRECTION OUTPUT ;
    USE SIGNAL ;
    PORT
      LAYER M4 ;
        RECT  220.236 63.024 220.32 63.048 ;
    END
  END rslot_v[6]
  PIN rslot_v[7]
    DIRECTION OUTPUT ;
    USE SIGNAL ;
    PORT
      LAYER M4 ;
        RECT  220.236 63.12 220.32 63.144 ;
    END
  END rslot_v[7]
  PIN rst_n
    DIRECTION INPUT ;
    USE SIGNAL ;
    PORT
      LAYER M4 ;
        RECT  0 50.064 0.084 50.088 ;
    END
  END rst_n
  PIN start_base[0]
    DIRECTION INPUT ;
    USE SIGNAL ;
    PORT
      LAYER M4 ;
        RECT  0 50.16 0.084 50.184 ;
    END
  END start_base[0]
  PIN start_base[1]
    DIRECTION INPUT ;
    USE SIGNAL ;
    PORT
      LAYER M4 ;
        RECT  0 50.256 0.084 50.28 ;
    END
  END start_base[1]
  PIN start_base[2]
    DIRECTION INPUT ;
    USE SIGNAL ;
    PORT
      LAYER M4 ;
        RECT  0 50.352 0.084 50.376 ;
    END
  END start_base[2]
  PIN start_base[3]
    DIRECTION INPUT ;
    USE SIGNAL ;
    PORT
      LAYER M4 ;
        RECT  0 50.448 0.084 50.472 ;
    END
  END start_base[3]
  PIN start_base[4]
    DIRECTION INPUT ;
    USE SIGNAL ;
    PORT
      LAYER M4 ;
        RECT  0 50.544 0.084 50.568 ;
    END
  END start_base[4]
  PIN start_base[5]
    DIRECTION INPUT ;
    USE SIGNAL ;
    PORT
      LAYER M4 ;
        RECT  0 50.64 0.084 50.664 ;
    END
  END start_base[5]
  PIN start_base[6]
    DIRECTION INPUT ;
    USE SIGNAL ;
    PORT
      LAYER M4 ;
        RECT  0 50.736 0.084 50.76 ;
    END
  END start_base[6]
  PIN start_base[7]
    DIRECTION INPUT ;
    USE SIGNAL ;
    PORT
      LAYER M4 ;
        RECT  0 50.832 0.084 50.856 ;
    END
  END start_base[7]
  PIN start_base[8]
    DIRECTION INPUT ;
    USE SIGNAL ;
    PORT
      LAYER M4 ;
        RECT  0 50.928 0.084 50.952 ;
    END
  END start_base[8]
  PIN start_base[9]
    DIRECTION INPUT ;
    USE SIGNAL ;
    PORT
      LAYER M4 ;
        RECT  0 51.024 0.084 51.048 ;
    END
  END start_base[9]
  PIN start_limit[0]
    DIRECTION INPUT ;
    USE SIGNAL ;
    PORT
      LAYER M4 ;
        RECT  0 51.12 0.084 51.144 ;
    END
  END start_limit[0]
  PIN start_limit[10]
    DIRECTION INPUT ;
    USE SIGNAL ;
    PORT
      LAYER M4 ;
        RECT  0 56.4 0.084 56.424 ;
    END
  END start_limit[10]
  PIN start_limit[1]
    DIRECTION INPUT ;
    USE SIGNAL ;
    PORT
      LAYER M4 ;
        RECT  0 51.216 0.084 51.24 ;
    END
  END start_limit[1]
  PIN start_limit[2]
    DIRECTION INPUT ;
    USE SIGNAL ;
    PORT
      LAYER M4 ;
        RECT  0 51.312 0.084 51.336 ;
    END
  END start_limit[2]
  PIN start_limit[3]
    DIRECTION INPUT ;
    USE SIGNAL ;
    PORT
      LAYER M4 ;
        RECT  0 51.408 0.084 51.432 ;
    END
  END start_limit[3]
  PIN start_limit[4]
    DIRECTION INPUT ;
    USE SIGNAL ;
    PORT
      LAYER M4 ;
        RECT  0 51.504 0.084 51.528 ;
    END
  END start_limit[4]
  PIN start_limit[5]
    DIRECTION INPUT ;
    USE SIGNAL ;
    PORT
      LAYER M4 ;
        RECT  0 51.6 0.084 51.624 ;
    END
  END start_limit[5]
  PIN start_limit[6]
    DIRECTION INPUT ;
    USE SIGNAL ;
    PORT
      LAYER M4 ;
        RECT  0 51.696 0.084 51.72 ;
    END
  END start_limit[6]
  PIN start_limit[7]
    DIRECTION INPUT ;
    USE SIGNAL ;
    PORT
      LAYER M4 ;
        RECT  0 51.792 0.084 51.816 ;
    END
  END start_limit[7]
  PIN start_limit[8]
    DIRECTION INPUT ;
    USE SIGNAL ;
    PORT
      LAYER M4 ;
        RECT  0 51.888 0.084 51.912 ;
    END
  END start_limit[8]
  PIN start_limit[9]
    DIRECTION INPUT ;
    USE SIGNAL ;
    PORT
      LAYER M4 ;
        RECT  0 56.304 0.084 56.328 ;
    END
  END start_limit[9]
  PIN start_loops[0]
    DIRECTION INPUT ;
    USE SIGNAL ;
    PORT
      LAYER M4 ;
        RECT  0 56.496 0.084 56.52 ;
    END
  END start_loops[0]
  PIN start_loops[10]
    DIRECTION INPUT ;
    USE SIGNAL ;
    PORT
      LAYER M4 ;
        RECT  0 57.456 0.084 57.48 ;
    END
  END start_loops[10]
  PIN start_loops[11]
    DIRECTION INPUT ;
    USE SIGNAL ;
    PORT
      LAYER M4 ;
        RECT  0 57.552 0.084 57.576 ;
    END
  END start_loops[11]
  PIN start_loops[12]
    DIRECTION INPUT ;
    USE SIGNAL ;
    PORT
      LAYER M4 ;
        RECT  0 57.648 0.084 57.672 ;
    END
  END start_loops[12]
  PIN start_loops[13]
    DIRECTION INPUT ;
    USE SIGNAL ;
    PORT
      LAYER M4 ;
        RECT  0 57.744 0.084 57.768 ;
    END
  END start_loops[13]
  PIN start_loops[14]
    DIRECTION INPUT ;
    USE SIGNAL ;
    PORT
      LAYER M4 ;
        RECT  0 57.84 0.084 57.864 ;
    END
  END start_loops[14]
  PIN start_loops[15]
    DIRECTION INPUT ;
    USE SIGNAL ;
    PORT
      LAYER M4 ;
        RECT  0 57.936 0.084 57.96 ;
    END
  END start_loops[15]
  PIN start_loops[1]
    DIRECTION INPUT ;
    USE SIGNAL ;
    PORT
      LAYER M4 ;
        RECT  0 56.592 0.084 56.616 ;
    END
  END start_loops[1]
  PIN start_loops[2]
    DIRECTION INPUT ;
    USE SIGNAL ;
    PORT
      LAYER M4 ;
        RECT  0 56.688 0.084 56.712 ;
    END
  END start_loops[2]
  PIN start_loops[3]
    DIRECTION INPUT ;
    USE SIGNAL ;
    PORT
      LAYER M4 ;
        RECT  0 56.784 0.084 56.808 ;
    END
  END start_loops[3]
  PIN start_loops[4]
    DIRECTION INPUT ;
    USE SIGNAL ;
    PORT
      LAYER M4 ;
        RECT  0 56.88 0.084 56.904 ;
    END
  END start_loops[4]
  PIN start_loops[5]
    DIRECTION INPUT ;
    USE SIGNAL ;
    PORT
      LAYER M4 ;
        RECT  0 56.976 0.084 57 ;
    END
  END start_loops[5]
  PIN start_loops[6]
    DIRECTION INPUT ;
    USE SIGNAL ;
    PORT
      LAYER M4 ;
        RECT  0 57.072 0.084 57.096 ;
    END
  END start_loops[6]
  PIN start_loops[7]
    DIRECTION INPUT ;
    USE SIGNAL ;
    PORT
      LAYER M4 ;
        RECT  0 57.168 0.084 57.192 ;
    END
  END start_loops[7]
  PIN start_loops[8]
    DIRECTION INPUT ;
    USE SIGNAL ;
    PORT
      LAYER M4 ;
        RECT  0 57.264 0.084 57.288 ;
    END
  END start_loops[8]
  PIN start_loops[9]
    DIRECTION INPUT ;
    USE SIGNAL ;
    PORT
      LAYER M4 ;
        RECT  0 57.36 0.084 57.384 ;
    END
  END start_loops[9]
  PIN start_v
    DIRECTION INPUT ;
    USE SIGNAL ;
    PORT
      LAYER M4 ;
        RECT  0 58.032 0.084 58.056 ;
    END
  END start_v
  PIN wslot[0]
    DIRECTION OUTPUT ;
    USE SIGNAL ;
    PORT
      LAYER M4 ;
        RECT  220.236 63.216 220.32 63.24 ;
    END
  END wslot[0]
  PIN wslot[10]
    DIRECTION OUTPUT ;
    USE SIGNAL ;
    PORT
      LAYER M4 ;
        RECT  220.236 64.176 220.32 64.2 ;
    END
  END wslot[10]
  PIN wslot[11]
    DIRECTION OUTPUT ;
    USE SIGNAL ;
    PORT
      LAYER M4 ;
        RECT  220.236 64.272 220.32 64.296 ;
    END
  END wslot[11]
  PIN wslot[12]
    DIRECTION OUTPUT ;
    USE SIGNAL ;
    PORT
      LAYER M4 ;
        RECT  220.236 64.368 220.32 64.392 ;
    END
  END wslot[12]
  PIN wslot[13]
    DIRECTION OUTPUT ;
    USE SIGNAL ;
    PORT
      LAYER M4 ;
        RECT  220.236 58.32 220.32 58.344 ;
    END
  END wslot[13]
  PIN wslot[14]
    DIRECTION OUTPUT ;
    USE SIGNAL ;
    PORT
      LAYER M4 ;
        RECT  220.236 58.416 220.32 58.44 ;
    END
  END wslot[14]
  PIN wslot[15]
    DIRECTION OUTPUT ;
    USE SIGNAL ;
    PORT
      LAYER M4 ;
        RECT  220.236 58.512 220.32 58.536 ;
    END
  END wslot[15]
  PIN wslot[16]
    DIRECTION OUTPUT ;
    USE SIGNAL ;
    PORT
      LAYER M4 ;
        RECT  220.236 58.608 220.32 58.632 ;
    END
  END wslot[16]
  PIN wslot[17]
    DIRECTION OUTPUT ;
    USE SIGNAL ;
    PORT
      LAYER M4 ;
        RECT  220.236 58.704 220.32 58.728 ;
    END
  END wslot[17]
  PIN wslot[18]
    DIRECTION OUTPUT ;
    USE SIGNAL ;
    PORT
      LAYER M4 ;
        RECT  220.236 58.8 220.32 58.824 ;
    END
  END wslot[18]
  PIN wslot[19]
    DIRECTION OUTPUT ;
    USE SIGNAL ;
    PORT
      LAYER M4 ;
        RECT  220.236 58.896 220.32 58.92 ;
    END
  END wslot[19]
  PIN wslot[1]
    DIRECTION OUTPUT ;
    USE SIGNAL ;
    PORT
      LAYER M4 ;
        RECT  220.236 63.312 220.32 63.336 ;
    END
  END wslot[1]
  PIN wslot[20]
    DIRECTION OUTPUT ;
    USE SIGNAL ;
    PORT
      LAYER M4 ;
        RECT  220.236 58.992 220.32 59.016 ;
    END
  END wslot[20]
  PIN wslot[21]
    DIRECTION OUTPUT ;
    USE SIGNAL ;
    PORT
      LAYER M4 ;
        RECT  220.236 59.088 220.32 59.112 ;
    END
  END wslot[21]
  PIN wslot[22]
    DIRECTION OUTPUT ;
    USE SIGNAL ;
    PORT
      LAYER M4 ;
        RECT  220.236 59.184 220.32 59.208 ;
    END
  END wslot[22]
  PIN wslot[23]
    DIRECTION OUTPUT ;
    USE SIGNAL ;
    PORT
      LAYER M4 ;
        RECT  220.236 59.28 220.32 59.304 ;
    END
  END wslot[23]
  PIN wslot[2]
    DIRECTION OUTPUT ;
    USE SIGNAL ;
    PORT
      LAYER M4 ;
        RECT  220.236 63.408 220.32 63.432 ;
    END
  END wslot[2]
  PIN wslot[3]
    DIRECTION OUTPUT ;
    USE SIGNAL ;
    PORT
      LAYER M4 ;
        RECT  220.236 63.504 220.32 63.528 ;
    END
  END wslot[3]
  PIN wslot[4]
    DIRECTION OUTPUT ;
    USE SIGNAL ;
    PORT
      LAYER M4 ;
        RECT  220.236 63.6 220.32 63.624 ;
    END
  END wslot[4]
  PIN wslot[5]
    DIRECTION OUTPUT ;
    USE SIGNAL ;
    PORT
      LAYER M4 ;
        RECT  220.236 63.696 220.32 63.72 ;
    END
  END wslot[5]
  PIN wslot[6]
    DIRECTION OUTPUT ;
    USE SIGNAL ;
    PORT
      LAYER M4 ;
        RECT  220.236 63.792 220.32 63.816 ;
    END
  END wslot[6]
  PIN wslot[7]
    DIRECTION OUTPUT ;
    USE SIGNAL ;
    PORT
      LAYER M4 ;
        RECT  220.236 63.888 220.32 63.912 ;
    END
  END wslot[7]
  PIN wslot[8]
    DIRECTION OUTPUT ;
    USE SIGNAL ;
    PORT
      LAYER M4 ;
        RECT  220.236 63.984 220.32 64.008 ;
    END
  END wslot[8]
  PIN wslot[9]
    DIRECTION OUTPUT ;
    USE SIGNAL ;
    PORT
      LAYER M4 ;
        RECT  220.236 64.08 220.32 64.104 ;
    END
  END wslot[9]
  PIN wslot_v[0]
    DIRECTION OUTPUT ;
    USE SIGNAL ;
    PORT
      LAYER M4 ;
        RECT  220.236 59.376 220.32 59.4 ;
    END
  END wslot_v[0]
  PIN wslot_v[1]
    DIRECTION OUTPUT ;
    USE SIGNAL ;
    PORT
      LAYER M4 ;
        RECT  220.236 59.472 220.32 59.496 ;
    END
  END wslot_v[1]
  PIN wslot_v[2]
    DIRECTION OUTPUT ;
    USE SIGNAL ;
    PORT
      LAYER M4 ;
        RECT  220.236 59.568 220.32 59.592 ;
    END
  END wslot_v[2]
  PIN wslot_v[3]
    DIRECTION OUTPUT ;
    USE SIGNAL ;
    PORT
      LAYER M4 ;
        RECT  220.236 59.664 220.32 59.688 ;
    END
  END wslot_v[3]
  PIN wslot_v[4]
    DIRECTION OUTPUT ;
    USE SIGNAL ;
    PORT
      LAYER M4 ;
        RECT  220.236 59.76 220.32 59.784 ;
    END
  END wslot_v[4]
  PIN wslot_v[5]
    DIRECTION OUTPUT ;
    USE SIGNAL ;
    PORT
      LAYER M4 ;
        RECT  220.236 59.856 220.32 59.88 ;
    END
  END wslot_v[5]
  PIN wslot_v[6]
    DIRECTION OUTPUT ;
    USE SIGNAL ;
    PORT
      LAYER M4 ;
        RECT  220.236 59.952 220.32 59.976 ;
    END
  END wslot_v[6]
  PIN wslot_v[7]
    DIRECTION OUTPUT ;
    USE SIGNAL ;
    PORT
      LAYER M4 ;
        RECT  220.236 60.048 220.32 60.072 ;
    END
  END wslot_v[7]
  PIN VDD
    DIRECTION INOUT ;
    USE POWER ;
    PORT
      LAYER M5 ;
        RECT  213.192 2.151 213.312 174.969 ;
        RECT  207.792 2.151 207.912 174.969 ;
        RECT  202.392 2.151 202.512 174.969 ;
        RECT  196.992 2.151 197.112 174.969 ;
        RECT  191.592 2.151 191.712 174.969 ;
        RECT  186.192 2.151 186.312 174.969 ;
        RECT  180.792 2.151 180.912 174.969 ;
        RECT  175.392 2.151 175.512 174.969 ;
        RECT  169.992 2.151 170.112 174.969 ;
        RECT  164.592 2.151 164.712 174.969 ;
        RECT  159.192 2.151 159.312 174.969 ;
        RECT  153.792 2.151 153.912 174.969 ;
        RECT  148.392 2.151 148.512 174.969 ;
        RECT  142.992 2.151 143.112 174.969 ;
        RECT  137.592 2.151 137.712 174.969 ;
        RECT  132.192 2.151 132.312 174.969 ;
        RECT  126.792 2.151 126.912 174.969 ;
        RECT  121.392 2.151 121.512 174.969 ;
        RECT  115.992 2.151 116.112 174.969 ;
        RECT  110.592 2.151 110.712 174.969 ;
        RECT  105.192 2.151 105.312 174.969 ;
        RECT  99.792 2.151 99.912 174.969 ;
        RECT  94.392 2.151 94.512 174.969 ;
        RECT  88.992 2.151 89.112 174.969 ;
        RECT  83.592 2.151 83.712 174.969 ;
        RECT  78.192 2.151 78.312 174.969 ;
        RECT  72.792 2.151 72.912 174.969 ;
        RECT  67.392 2.151 67.512 174.969 ;
        RECT  61.992 2.151 62.112 174.969 ;
        RECT  56.592 2.151 56.712 174.969 ;
        RECT  51.192 2.151 51.312 174.969 ;
        RECT  45.792 2.151 45.912 174.969 ;
        RECT  40.392 2.151 40.512 174.969 ;
        RECT  34.992 2.151 35.112 174.969 ;
        RECT  29.592 2.151 29.712 174.969 ;
        RECT  24.192 2.151 24.312 174.969 ;
        RECT  18.792 2.151 18.912 174.969 ;
        RECT  13.392 2.151 13.512 174.969 ;
        RECT  7.992 2.151 8.112 174.969 ;
        RECT  2.592 2.151 2.712 174.969 ;
    END
  END VDD
  PIN VSS
    DIRECTION INOUT ;
    USE GROUND ;
    PORT
      LAYER M5 ;
        RECT  213 2.137 213.12 174.983 ;
        RECT  207.6 2.137 207.72 174.983 ;
        RECT  202.2 2.137 202.32 174.983 ;
        RECT  196.8 2.137 196.92 174.983 ;
        RECT  191.4 2.137 191.52 174.983 ;
        RECT  186 2.137 186.12 174.983 ;
        RECT  180.6 2.137 180.72 174.983 ;
        RECT  175.2 2.137 175.32 174.983 ;
        RECT  169.8 2.137 169.92 174.983 ;
        RECT  164.4 2.137 164.52 174.983 ;
        RECT  159 2.137 159.12 174.983 ;
        RECT  153.6 2.137 153.72 174.983 ;
        RECT  148.2 2.137 148.32 174.983 ;
        RECT  142.8 2.137 142.92 174.983 ;
        RECT  137.4 2.137 137.52 174.983 ;
        RECT  132 2.137 132.12 174.983 ;
        RECT  126.6 2.137 126.72 174.983 ;
        RECT  121.2 2.137 121.32 174.983 ;
        RECT  115.8 2.137 115.92 174.983 ;
        RECT  110.4 2.137 110.52 174.983 ;
        RECT  105 2.137 105.12 174.983 ;
        RECT  99.6 2.137 99.72 174.983 ;
        RECT  94.2 2.137 94.32 174.983 ;
        RECT  88.8 2.137 88.92 174.983 ;
        RECT  83.4 2.137 83.52 174.983 ;
        RECT  78 2.137 78.12 174.983 ;
        RECT  72.6 2.137 72.72 174.983 ;
        RECT  67.2 2.137 67.32 174.983 ;
        RECT  61.8 2.137 61.92 174.983 ;
        RECT  56.4 2.137 56.52 174.983 ;
        RECT  51 2.137 51.12 174.983 ;
        RECT  45.6 2.137 45.72 174.983 ;
        RECT  40.2 2.137 40.32 174.983 ;
        RECT  34.8 2.137 34.92 174.983 ;
        RECT  29.4 2.137 29.52 174.983 ;
        RECT  24 2.137 24.12 174.983 ;
        RECT  18.6 2.137 18.72 174.983 ;
        RECT  13.2 2.137 13.32 174.983 ;
        RECT  7.8 2.137 7.92 174.983 ;
        RECT  2.4 2.137 2.52 174.983 ;
    END
  END VSS
  # OT_OBS_CLOSED layer=M5 d_um=1.536 added=114
  OBS
    LAYER RVTN ;
     RECT  2.16 2.16 218.16 2.295 ;
     RECT  2.16 2.565 218.16 2.835 ;
     RECT  2.16 3.105 218.16 3.375 ;
     RECT  2.16 3.645 218.16 3.915 ;
     RECT  2.16 4.185 218.16 4.455 ;
     RECT  2.16 4.725 218.16 4.995 ;
     RECT  2.16 5.265 218.16 5.535 ;
     RECT  2.16 5.805 218.16 6.075 ;
     RECT  2.16 6.345 218.16 6.615 ;
     RECT  2.16 6.885 218.16 7.155 ;
     RECT  2.16 7.425 218.16 7.695 ;
     RECT  2.16 7.965 218.16 8.235 ;
     RECT  2.16 8.505 218.16 8.775 ;
     RECT  2.16 9.045 218.16 9.315 ;
     RECT  2.16 9.585 218.16 9.855 ;
     RECT  2.16 10.125 218.16 10.395 ;
     RECT  2.16 10.665 218.16 10.935 ;
     RECT  2.16 11.205 218.16 11.475 ;
     RECT  2.16 11.745 218.16 12.015 ;
     RECT  2.16 12.285 218.16 12.555 ;
     RECT  2.16 12.825 218.16 13.095 ;
     RECT  2.16 13.365 218.16 13.635 ;
     RECT  2.16 13.905 218.16 14.175 ;
     RECT  2.16 14.445 218.16 14.715 ;
     RECT  2.16 14.985 218.16 15.255 ;
     RECT  2.16 15.525 218.16 15.795 ;
     RECT  2.16 16.065 218.16 16.335 ;
     RECT  2.16 16.605 218.16 16.875 ;
     RECT  2.16 17.145 218.16 17.415 ;
     RECT  2.16 17.685 218.16 17.955 ;
     RECT  2.16 18.225 218.16 18.495 ;
     RECT  2.16 18.765 218.16 19.035 ;
     RECT  2.16 19.305 218.16 19.575 ;
     RECT  2.16 19.845 218.16 20.115 ;
     RECT  2.16 20.385 218.16 20.655 ;
     RECT  2.16 20.925 218.16 21.195 ;
     RECT  2.16 21.465 218.16 21.735 ;
     RECT  2.16 22.005 218.16 22.275 ;
     RECT  2.16 22.545 218.16 22.815 ;
     RECT  2.16 23.085 218.16 23.355 ;
     RECT  2.16 23.625 218.16 23.895 ;
     RECT  2.16 24.165 218.16 24.435 ;
     RECT  2.16 24.705 218.16 24.975 ;
     RECT  2.16 25.245 218.16 25.515 ;
     RECT  2.16 25.785 218.16 26.055 ;
     RECT  2.16 26.325 218.16 26.595 ;
     RECT  2.16 26.865 218.16 27.135 ;
     RECT  2.16 27.405 218.16 27.675 ;
     RECT  2.16 27.945 218.16 28.215 ;
     RECT  2.16 28.485 218.16 28.755 ;
     RECT  2.16 29.025 218.16 29.295 ;
     RECT  2.16 29.565 218.16 29.835 ;
     RECT  2.16 30.105 218.16 30.375 ;
     RECT  2.16 30.645 218.16 30.915 ;
     RECT  2.16 31.185 218.16 31.455 ;
     RECT  2.16 31.725 218.16 31.995 ;
     RECT  2.16 32.265 218.16 32.535 ;
     RECT  2.16 32.805 218.16 33.075 ;
     RECT  2.16 33.345 218.16 33.615 ;
     RECT  2.16 33.885 218.16 34.155 ;
     RECT  2.16 34.425 218.16 34.695 ;
     RECT  2.16 34.965 218.16 35.235 ;
     RECT  2.16 35.505 218.16 35.775 ;
     RECT  2.16 36.045 218.16 36.315 ;
     RECT  2.16 36.585 218.16 36.855 ;
     RECT  2.16 37.125 218.16 37.395 ;
     RECT  2.16 37.665 218.16 37.935 ;
     RECT  2.16 38.205 218.16 38.475 ;
     RECT  2.16 38.745 218.16 39.015 ;
     RECT  2.16 39.285 218.16 39.555 ;
     RECT  2.16 39.825 218.16 40.095 ;
     RECT  2.16 40.365 218.16 40.635 ;
     RECT  2.16 40.905 218.16 41.175 ;
     RECT  2.16 41.445 218.16 41.715 ;
     RECT  2.16 41.985 218.16 42.255 ;
     RECT  2.16 42.525 218.16 42.795 ;
     RECT  2.16 43.065 218.16 43.335 ;
     RECT  2.16 43.605 218.16 43.875 ;
     RECT  2.16 44.145 218.16 44.415 ;
     RECT  2.16 44.685 218.16 44.955 ;
     RECT  2.16 45.225 218.16 45.495 ;
     RECT  2.16 45.765 218.16 46.035 ;
     RECT  2.16 46.305 218.16 46.575 ;
     RECT  2.16 46.845 218.16 47.115 ;
     RECT  2.16 47.385 218.16 47.655 ;
     RECT  2.16 47.925 218.16 48.195 ;
     RECT  2.16 48.465 218.16 48.735 ;
     RECT  2.16 49.005 218.16 49.275 ;
     RECT  2.16 49.545 218.16 49.815 ;
     RECT  2.16 50.085 218.16 50.355 ;
     RECT  2.16 50.625 218.16 50.895 ;
     RECT  2.16 51.165 218.16 51.435 ;
     RECT  2.16 51.705 218.16 51.84 ;
     RECT  2.16 51.84 20.844 51.975 ;
     RECT  199.692 51.84 218.16 51.975 ;
     RECT  2.16 52.245 20.844 52.515 ;
     RECT  199.692 52.245 218.16 52.515 ;
     RECT  2.16 52.785 20.844 53.055 ;
     RECT  199.692 52.785 218.16 53.055 ;
     RECT  2.16 53.325 20.844 53.595 ;
     RECT  199.692 53.325 218.16 53.595 ;
     RECT  2.16 53.865 20.844 54.135 ;
     RECT  199.692 53.865 218.16 54.135 ;
     RECT  2.16 54.405 20.844 54.675 ;
     RECT  199.692 54.405 218.16 54.675 ;
     RECT  2.16 54.945 20.844 55.215 ;
     RECT  199.692 54.945 218.16 55.215 ;
     RECT  2.16 55.485 20.844 55.755 ;
     RECT  199.692 55.485 218.16 55.755 ;
     RECT  2.16 56.025 20.844 56.295 ;
     RECT  199.692 56.025 218.16 56.295 ;
     RECT  2.16 56.565 20.844 56.835 ;
     RECT  199.692 56.565 218.16 56.835 ;
     RECT  2.16 57.105 20.844 57.375 ;
     RECT  199.692 57.105 218.16 57.375 ;
     RECT  2.16 57.645 20.844 57.915 ;
     RECT  199.692 57.645 218.16 57.915 ;
     RECT  2.16 58.185 20.844 58.455 ;
     RECT  199.692 58.185 218.16 58.455 ;
     RECT  2.16 58.725 20.844 58.995 ;
     RECT  199.692 58.725 218.16 58.995 ;
     RECT  2.16 59.265 20.844 59.535 ;
     RECT  199.692 59.265 218.16 59.535 ;
     RECT  2.16 59.805 20.844 60.075 ;
     RECT  199.692 59.805 218.16 60.075 ;
     RECT  2.16 60.345 20.844 60.615 ;
     RECT  199.692 60.345 218.16 60.615 ;
     RECT  2.16 60.885 20.844 61.155 ;
     RECT  199.692 60.885 218.16 61.155 ;
     RECT  2.16 61.425 20.844 61.695 ;
     RECT  199.692 61.425 218.16 61.695 ;
     RECT  2.16 61.965 20.844 62.235 ;
     RECT  199.692 61.965 218.16 62.235 ;
     RECT  2.16 62.505 20.844 62.775 ;
     RECT  199.692 62.505 218.16 62.775 ;
     RECT  2.16 63.045 20.844 63.315 ;
     RECT  199.692 63.045 218.16 63.315 ;
     RECT  2.16 63.585 20.844 63.855 ;
     RECT  199.692 63.585 218.16 63.855 ;
     RECT  2.16 64.125 20.844 64.395 ;
     RECT  199.692 64.125 218.16 64.395 ;
     RECT  2.16 64.665 20.844 64.935 ;
     RECT  199.692 64.665 218.16 64.935 ;
     RECT  2.16 65.205 20.844 65.475 ;
     RECT  199.692 65.205 218.16 65.475 ;
     RECT  2.16 65.745 20.844 66.015 ;
     RECT  199.692 65.745 218.16 66.015 ;
     RECT  2.16 66.285 20.844 66.555 ;
     RECT  199.692 66.285 218.16 66.555 ;
     RECT  2.16 66.825 20.844 67.095 ;
     RECT  199.692 66.825 218.16 67.095 ;
     RECT  2.16 67.365 20.844 67.635 ;
     RECT  199.692 67.365 218.16 67.635 ;
     RECT  2.16 67.905 20.844 68.175 ;
     RECT  199.692 67.905 218.16 68.175 ;
     RECT  2.16 68.445 20.844 68.715 ;
     RECT  199.692 68.445 218.16 68.715 ;
     RECT  2.16 68.985 20.844 69.255 ;
     RECT  199.692 68.985 218.16 69.255 ;
     RECT  2.16 69.525 20.844 69.795 ;
     RECT  199.692 69.525 218.16 69.795 ;
     RECT  2.16 70.065 20.844 70.335 ;
     RECT  199.692 70.065 218.16 70.335 ;
     RECT  2.16 70.605 20.844 70.875 ;
     RECT  199.692 70.605 218.16 70.875 ;
     RECT  2.16 71.145 20.844 71.415 ;
     RECT  199.692 71.145 218.16 71.415 ;
     RECT  2.16 71.685 20.844 71.955 ;
     RECT  199.692 71.685 218.16 71.955 ;
     RECT  2.16 72.225 20.844 72.495 ;
     RECT  199.692 72.225 218.16 72.495 ;
     RECT  2.16 72.765 20.844 73.035 ;
     RECT  199.692 72.765 218.16 73.035 ;
     RECT  2.16 73.305 20.844 73.575 ;
     RECT  199.692 73.305 218.16 73.575 ;
     RECT  2.16 73.845 20.844 74.115 ;
     RECT  199.692 73.845 218.16 74.115 ;
     RECT  2.16 74.385 20.844 74.655 ;
     RECT  199.692 74.385 218.16 74.655 ;
     RECT  2.16 74.925 20.844 75.195 ;
     RECT  199.692 74.925 218.16 75.195 ;
     RECT  2.16 75.465 20.844 75.735 ;
     RECT  199.692 75.465 218.16 75.735 ;
     RECT  2.16 76.005 20.844 76.275 ;
     RECT  199.692 76.005 218.16 76.275 ;
     RECT  2.16 76.545 20.844 76.815 ;
     RECT  199.692 76.545 218.16 76.815 ;
     RECT  2.16 77.085 20.844 77.355 ;
     RECT  199.692 77.085 218.16 77.355 ;
     RECT  2.16 77.625 20.844 77.895 ;
     RECT  199.692 77.625 218.16 77.895 ;
     RECT  2.16 78.165 20.844 78.435 ;
     RECT  199.692 78.165 218.16 78.435 ;
     RECT  2.16 78.705 20.844 78.975 ;
     RECT  199.692 78.705 218.16 78.975 ;
     RECT  2.16 79.245 20.844 79.515 ;
     RECT  199.692 79.245 218.16 79.515 ;
     RECT  2.16 79.785 20.844 80.055 ;
     RECT  199.692 79.785 218.16 80.055 ;
     RECT  2.16 80.325 20.844 80.595 ;
     RECT  199.692 80.325 218.16 80.595 ;
     RECT  2.16 80.865 20.844 81.135 ;
     RECT  199.692 80.865 218.16 81.135 ;
     RECT  2.16 81.405 20.844 81.675 ;
     RECT  199.692 81.405 218.16 81.675 ;
     RECT  2.16 81.945 20.844 82.215 ;
     RECT  199.692 81.945 218.16 82.215 ;
     RECT  2.16 82.485 20.844 82.755 ;
     RECT  199.692 82.485 218.16 82.755 ;
     RECT  2.16 83.025 20.844 83.295 ;
     RECT  199.692 83.025 218.16 83.295 ;
     RECT  2.16 83.565 20.844 83.835 ;
     RECT  199.692 83.565 218.16 83.835 ;
     RECT  2.16 84.105 20.844 84.375 ;
     RECT  199.692 84.105 218.16 84.375 ;
     RECT  2.16 84.645 20.844 84.915 ;
     RECT  199.692 84.645 218.16 84.915 ;
     RECT  2.16 85.185 20.844 85.455 ;
     RECT  199.692 85.185 218.16 85.455 ;
     RECT  2.16 85.725 20.844 85.995 ;
     RECT  199.692 85.725 218.16 85.995 ;
     RECT  2.16 86.265 20.844 86.535 ;
     RECT  199.692 86.265 218.16 86.535 ;
     RECT  2.16 86.805 20.844 87.075 ;
     RECT  199.692 86.805 218.16 87.075 ;
     RECT  2.16 87.345 20.844 87.615 ;
     RECT  199.692 87.345 218.16 87.615 ;
     RECT  2.16 87.885 20.844 88.155 ;
     RECT  199.692 87.885 218.16 88.155 ;
     RECT  2.16 88.425 20.844 88.695 ;
     RECT  199.692 88.425 218.16 88.695 ;
     RECT  2.16 88.965 20.844 89.235 ;
     RECT  199.692 88.965 218.16 89.235 ;
     RECT  2.16 89.505 20.844 89.775 ;
     RECT  199.692 89.505 218.16 89.775 ;
     RECT  2.16 90.045 20.844 90.315 ;
     RECT  199.692 90.045 218.16 90.315 ;
     RECT  2.16 90.585 20.844 90.855 ;
     RECT  199.692 90.585 218.16 90.855 ;
     RECT  2.16 91.125 20.844 91.395 ;
     RECT  199.692 91.125 218.16 91.395 ;
     RECT  2.16 91.665 20.844 91.935 ;
     RECT  199.692 91.665 218.16 91.935 ;
     RECT  2.16 92.205 20.844 92.475 ;
     RECT  199.692 92.205 218.16 92.475 ;
     RECT  2.16 92.745 20.844 93.015 ;
     RECT  199.692 92.745 218.16 93.015 ;
     RECT  2.16 93.285 20.844 93.555 ;
     RECT  199.692 93.285 218.16 93.555 ;
     RECT  2.16 93.825 20.844 94.095 ;
     RECT  199.692 93.825 218.16 94.095 ;
     RECT  2.16 94.365 20.844 94.635 ;
     RECT  199.692 94.365 218.16 94.635 ;
     RECT  2.16 94.905 20.844 95.175 ;
     RECT  199.692 94.905 218.16 95.175 ;
     RECT  2.16 95.445 20.844 95.715 ;
     RECT  199.692 95.445 218.16 95.715 ;
     RECT  2.16 95.985 20.844 96.255 ;
     RECT  199.692 95.985 218.16 96.255 ;
     RECT  2.16 96.525 20.844 96.795 ;
     RECT  199.692 96.525 218.16 96.795 ;
     RECT  2.16 97.065 20.844 97.335 ;
     RECT  199.692 97.065 218.16 97.335 ;
     RECT  2.16 97.605 20.844 97.875 ;
     RECT  199.692 97.605 218.16 97.875 ;
     RECT  2.16 98.145 20.844 98.415 ;
     RECT  199.692 98.145 218.16 98.415 ;
     RECT  2.16 98.685 20.844 98.955 ;
     RECT  199.692 98.685 218.16 98.955 ;
     RECT  2.16 99.225 20.844 99.495 ;
     RECT  199.692 99.225 218.16 99.495 ;
     RECT  2.16 99.765 20.844 100.035 ;
     RECT  199.692 99.765 218.16 100.035 ;
     RECT  2.16 100.305 20.844 100.575 ;
     RECT  199.692 100.305 218.16 100.575 ;
     RECT  2.16 100.845 20.844 101.115 ;
     RECT  199.692 100.845 218.16 101.115 ;
     RECT  2.16 101.385 20.844 101.655 ;
     RECT  199.692 101.385 218.16 101.655 ;
     RECT  2.16 101.925 20.844 102.195 ;
     RECT  199.692 101.925 218.16 102.195 ;
     RECT  2.16 102.465 20.844 102.735 ;
     RECT  199.692 102.465 218.16 102.735 ;
     RECT  2.16 103.005 20.844 103.275 ;
     RECT  199.692 103.005 218.16 103.275 ;
     RECT  2.16 103.545 20.844 103.815 ;
     RECT  199.692 103.545 218.16 103.815 ;
     RECT  2.16 104.085 20.844 104.355 ;
     RECT  199.692 104.085 218.16 104.355 ;
     RECT  2.16 104.625 20.844 104.895 ;
     RECT  199.692 104.625 218.16 104.895 ;
     RECT  2.16 105.165 20.844 105.435 ;
     RECT  199.692 105.165 218.16 105.435 ;
     RECT  2.16 105.705 20.844 105.975 ;
     RECT  199.692 105.705 218.16 105.975 ;
     RECT  2.16 106.245 20.844 106.515 ;
     RECT  199.692 106.245 218.16 106.515 ;
     RECT  2.16 106.785 20.844 107.055 ;
     RECT  199.692 106.785 218.16 107.055 ;
     RECT  2.16 107.325 20.844 107.595 ;
     RECT  199.692 107.325 218.16 107.595 ;
     RECT  2.16 107.865 20.844 108.135 ;
     RECT  199.692 107.865 218.16 108.135 ;
     RECT  2.16 108.405 20.844 108.675 ;
     RECT  199.692 108.405 218.16 108.675 ;
     RECT  2.16 108.945 20.844 109.215 ;
     RECT  199.692 108.945 218.16 109.215 ;
     RECT  2.16 109.485 20.844 109.755 ;
     RECT  199.692 109.485 218.16 109.755 ;
     RECT  2.16 110.025 20.844 110.295 ;
     RECT  199.692 110.025 218.16 110.295 ;
     RECT  2.16 110.565 20.844 110.835 ;
     RECT  199.692 110.565 218.16 110.835 ;
     RECT  2.16 111.105 20.844 111.375 ;
     RECT  199.692 111.105 218.16 111.375 ;
     RECT  2.16 111.645 20.844 111.915 ;
     RECT  199.692 111.645 218.16 111.915 ;
     RECT  2.16 112.185 20.844 112.455 ;
     RECT  199.692 112.185 218.16 112.455 ;
     RECT  2.16 112.725 20.844 112.995 ;
     RECT  199.692 112.725 218.16 112.995 ;
     RECT  2.16 113.265 20.844 113.535 ;
     RECT  199.692 113.265 218.16 113.535 ;
     RECT  2.16 113.805 20.844 114.075 ;
     RECT  199.692 113.805 218.16 114.075 ;
     RECT  2.16 114.345 20.844 114.615 ;
     RECT  199.692 114.345 218.16 114.615 ;
     RECT  2.16 114.885 20.844 115.155 ;
     RECT  199.692 114.885 218.16 115.155 ;
     RECT  2.16 115.425 20.844 115.695 ;
     RECT  199.692 115.425 218.16 115.695 ;
     RECT  2.16 115.965 20.844 116.235 ;
     RECT  199.692 115.965 218.16 116.235 ;
     RECT  2.16 116.505 20.844 116.775 ;
     RECT  199.692 116.505 218.16 116.775 ;
     RECT  2.16 117.045 20.844 117.315 ;
     RECT  199.692 117.045 218.16 117.315 ;
     RECT  2.16 117.585 20.844 117.855 ;
     RECT  199.692 117.585 218.16 117.855 ;
     RECT  2.16 118.125 20.844 118.395 ;
     RECT  199.692 118.125 218.16 118.395 ;
     RECT  2.16 118.665 20.844 118.935 ;
     RECT  199.692 118.665 218.16 118.935 ;
     RECT  2.16 119.205 20.844 119.475 ;
     RECT  199.692 119.205 218.16 119.475 ;
     RECT  2.16 119.745 20.844 120.015 ;
     RECT  199.692 119.745 218.16 120.015 ;
     RECT  2.16 120.285 20.844 120.555 ;
     RECT  199.692 120.285 218.16 120.555 ;
     RECT  2.16 120.825 20.844 121.095 ;
     RECT  199.692 120.825 218.16 121.095 ;
     RECT  2.16 121.365 20.844 121.635 ;
     RECT  199.692 121.365 218.16 121.635 ;
     RECT  2.16 121.905 20.844 122.175 ;
     RECT  199.692 121.905 218.16 122.175 ;
     RECT  2.16 122.445 20.844 122.715 ;
     RECT  199.692 122.445 218.16 122.715 ;
     RECT  2.16 122.985 20.844 123.255 ;
     RECT  199.692 122.985 218.16 123.255 ;
     RECT  2.16 123.525 20.844 123.795 ;
     RECT  199.692 123.525 218.16 123.795 ;
     RECT  2.16 124.065 20.844 124.335 ;
     RECT  199.692 124.065 218.16 124.335 ;
     RECT  2.16 124.605 20.844 124.875 ;
     RECT  199.692 124.605 218.16 124.875 ;
     RECT  2.16 125.145 20.844 125.415 ;
     RECT  199.692 125.145 218.16 125.415 ;
     RECT  2.16 125.685 20.844 125.955 ;
     RECT  199.692 125.685 218.16 125.955 ;
     RECT  2.16 126.225 20.844 126.495 ;
     RECT  199.692 126.225 218.16 126.495 ;
     RECT  2.16 126.765 218.16 127.035 ;
     RECT  2.16 127.305 218.16 127.575 ;
     RECT  2.16 127.845 218.16 128.115 ;
     RECT  2.16 128.385 218.16 128.655 ;
     RECT  2.16 128.925 218.16 129.195 ;
     RECT  2.16 129.465 218.16 129.735 ;
     RECT  2.16 130.005 218.16 130.275 ;
     RECT  2.16 130.545 218.16 130.815 ;
     RECT  2.16 131.085 218.16 131.355 ;
     RECT  2.16 131.625 218.16 131.895 ;
     RECT  2.16 132.165 218.16 132.435 ;
     RECT  2.16 132.705 218.16 132.975 ;
     RECT  2.16 133.245 218.16 133.515 ;
     RECT  2.16 133.785 218.16 134.055 ;
     RECT  2.16 134.325 218.16 134.595 ;
     RECT  2.16 134.865 218.16 135.135 ;
     RECT  2.16 135.405 218.16 135.675 ;
     RECT  2.16 135.945 218.16 136.215 ;
     RECT  2.16 136.485 218.16 136.755 ;
     RECT  2.16 137.025 218.16 137.295 ;
     RECT  2.16 137.565 218.16 137.835 ;
     RECT  2.16 138.105 218.16 138.375 ;
     RECT  2.16 138.645 218.16 138.915 ;
     RECT  2.16 139.185 218.16 139.455 ;
     RECT  2.16 139.725 218.16 139.995 ;
     RECT  2.16 140.265 218.16 140.535 ;
     RECT  2.16 140.805 218.16 141.075 ;
     RECT  2.16 141.345 218.16 141.615 ;
     RECT  2.16 141.885 218.16 142.155 ;
     RECT  2.16 142.425 218.16 142.695 ;
     RECT  2.16 142.965 218.16 143.235 ;
     RECT  2.16 143.505 218.16 143.775 ;
     RECT  2.16 144.045 218.16 144.315 ;
     RECT  2.16 144.585 218.16 144.855 ;
     RECT  2.16 145.125 218.16 145.395 ;
     RECT  2.16 145.665 218.16 145.935 ;
     RECT  2.16 146.205 218.16 146.475 ;
     RECT  2.16 146.745 218.16 147.015 ;
     RECT  2.16 147.285 218.16 147.555 ;
     RECT  2.16 147.825 218.16 148.095 ;
     RECT  2.16 148.365 218.16 148.635 ;
     RECT  2.16 148.905 218.16 149.175 ;
     RECT  2.16 149.445 218.16 149.715 ;
     RECT  2.16 149.985 218.16 150.255 ;
     RECT  2.16 150.525 218.16 150.795 ;
     RECT  2.16 151.065 218.16 151.335 ;
     RECT  2.16 151.605 218.16 151.875 ;
     RECT  2.16 152.145 218.16 152.415 ;
     RECT  2.16 152.685 218.16 152.955 ;
     RECT  2.16 153.225 218.16 153.495 ;
     RECT  2.16 153.765 218.16 154.035 ;
     RECT  2.16 154.305 218.16 154.575 ;
     RECT  2.16 154.845 218.16 155.115 ;
     RECT  2.16 155.385 218.16 155.655 ;
     RECT  2.16 155.925 218.16 156.195 ;
     RECT  2.16 156.465 218.16 156.735 ;
     RECT  2.16 157.005 218.16 157.275 ;
     RECT  2.16 157.545 218.16 157.815 ;
     RECT  2.16 158.085 218.16 158.355 ;
     RECT  2.16 158.625 218.16 158.895 ;
     RECT  2.16 159.165 218.16 159.435 ;
     RECT  2.16 159.705 218.16 159.975 ;
     RECT  2.16 160.245 218.16 160.515 ;
     RECT  2.16 160.785 218.16 161.055 ;
     RECT  2.16 161.325 218.16 161.595 ;
     RECT  2.16 161.865 218.16 162.135 ;
     RECT  2.16 162.405 218.16 162.675 ;
     RECT  2.16 162.945 218.16 163.215 ;
     RECT  2.16 163.485 218.16 163.755 ;
     RECT  2.16 164.025 218.16 164.295 ;
     RECT  2.16 164.565 218.16 164.835 ;
     RECT  2.16 165.105 218.16 165.375 ;
     RECT  2.16 165.645 218.16 165.915 ;
     RECT  2.16 166.185 218.16 166.455 ;
     RECT  2.16 166.725 218.16 166.995 ;
     RECT  2.16 167.265 218.16 167.535 ;
     RECT  2.16 167.805 218.16 168.075 ;
     RECT  2.16 168.345 218.16 168.615 ;
     RECT  2.16 168.885 218.16 169.155 ;
     RECT  2.16 169.425 218.16 169.695 ;
     RECT  2.16 169.965 218.16 170.235 ;
     RECT  2.16 170.505 218.16 170.775 ;
     RECT  2.16 171.045 218.16 171.315 ;
     RECT  2.16 171.585 218.16 171.855 ;
     RECT  2.16 172.125 218.16 172.395 ;
     RECT  2.16 172.665 218.16 172.935 ;
     RECT  2.16 173.205 218.16 173.475 ;
     RECT  2.16 173.745 218.16 174.015 ;
     RECT  2.16 174.285 218.16 174.555 ;
     RECT  2.16 174.825 218.16 174.96 ;
    LAYER RVTP ;
     RECT  2.16 2.295 218.16 2.565 ;
     RECT  2.16 2.835 218.16 3.105 ;
     RECT  2.16 3.375 218.16 3.645 ;
     RECT  2.16 3.915 218.16 4.185 ;
     RECT  2.16 4.455 218.16 4.725 ;
     RECT  2.16 4.995 218.16 5.265 ;
     RECT  2.16 5.535 218.16 5.805 ;
     RECT  2.16 6.075 218.16 6.345 ;
     RECT  2.16 6.615 218.16 6.885 ;
     RECT  2.16 7.155 218.16 7.425 ;
     RECT  2.16 7.695 218.16 7.965 ;
     RECT  2.16 8.235 218.16 8.505 ;
     RECT  2.16 8.775 218.16 9.045 ;
     RECT  2.16 9.315 218.16 9.585 ;
     RECT  2.16 9.855 218.16 10.125 ;
     RECT  2.16 10.395 218.16 10.665 ;
     RECT  2.16 10.935 218.16 11.205 ;
     RECT  2.16 11.475 218.16 11.745 ;
     RECT  2.16 12.015 218.16 12.285 ;
     RECT  2.16 12.555 218.16 12.825 ;
     RECT  2.16 13.095 218.16 13.365 ;
     RECT  2.16 13.635 218.16 13.905 ;
     RECT  2.16 14.175 218.16 14.445 ;
     RECT  2.16 14.715 218.16 14.985 ;
     RECT  2.16 15.255 218.16 15.525 ;
     RECT  2.16 15.795 218.16 16.065 ;
     RECT  2.16 16.335 218.16 16.605 ;
     RECT  2.16 16.875 218.16 17.145 ;
     RECT  2.16 17.415 218.16 17.685 ;
     RECT  2.16 17.955 218.16 18.225 ;
     RECT  2.16 18.495 218.16 18.765 ;
     RECT  2.16 19.035 218.16 19.305 ;
     RECT  2.16 19.575 218.16 19.845 ;
     RECT  2.16 20.115 218.16 20.385 ;
     RECT  2.16 20.655 218.16 20.925 ;
     RECT  2.16 21.195 218.16 21.465 ;
     RECT  2.16 21.735 218.16 22.005 ;
     RECT  2.16 22.275 218.16 22.545 ;
     RECT  2.16 22.815 218.16 23.085 ;
     RECT  2.16 23.355 218.16 23.625 ;
     RECT  2.16 23.895 218.16 24.165 ;
     RECT  2.16 24.435 218.16 24.705 ;
     RECT  2.16 24.975 218.16 25.245 ;
     RECT  2.16 25.515 218.16 25.785 ;
     RECT  2.16 26.055 218.16 26.325 ;
     RECT  2.16 26.595 218.16 26.865 ;
     RECT  2.16 27.135 218.16 27.405 ;
     RECT  2.16 27.675 218.16 27.945 ;
     RECT  2.16 28.215 218.16 28.485 ;
     RECT  2.16 28.755 218.16 29.025 ;
     RECT  2.16 29.295 218.16 29.565 ;
     RECT  2.16 29.835 218.16 30.105 ;
     RECT  2.16 30.375 218.16 30.645 ;
     RECT  2.16 30.915 218.16 31.185 ;
     RECT  2.16 31.455 218.16 31.725 ;
     RECT  2.16 31.995 218.16 32.265 ;
     RECT  2.16 32.535 218.16 32.805 ;
     RECT  2.16 33.075 218.16 33.345 ;
     RECT  2.16 33.615 218.16 33.885 ;
     RECT  2.16 34.155 218.16 34.425 ;
     RECT  2.16 34.695 218.16 34.965 ;
     RECT  2.16 35.235 218.16 35.505 ;
     RECT  2.16 35.775 218.16 36.045 ;
     RECT  2.16 36.315 218.16 36.585 ;
     RECT  2.16 36.855 218.16 37.125 ;
     RECT  2.16 37.395 218.16 37.665 ;
     RECT  2.16 37.935 218.16 38.205 ;
     RECT  2.16 38.475 218.16 38.745 ;
     RECT  2.16 39.015 218.16 39.285 ;
     RECT  2.16 39.555 218.16 39.825 ;
     RECT  2.16 40.095 218.16 40.365 ;
     RECT  2.16 40.635 218.16 40.905 ;
     RECT  2.16 41.175 218.16 41.445 ;
     RECT  2.16 41.715 218.16 41.985 ;
     RECT  2.16 42.255 218.16 42.525 ;
     RECT  2.16 42.795 218.16 43.065 ;
     RECT  2.16 43.335 218.16 43.605 ;
     RECT  2.16 43.875 218.16 44.145 ;
     RECT  2.16 44.415 218.16 44.685 ;
     RECT  2.16 44.955 218.16 45.225 ;
     RECT  2.16 45.495 218.16 45.765 ;
     RECT  2.16 46.035 218.16 46.305 ;
     RECT  2.16 46.575 218.16 46.845 ;
     RECT  2.16 47.115 218.16 47.385 ;
     RECT  2.16 47.655 218.16 47.925 ;
     RECT  2.16 48.195 218.16 48.465 ;
     RECT  2.16 48.735 218.16 49.005 ;
     RECT  2.16 49.275 218.16 49.545 ;
     RECT  2.16 49.815 218.16 50.085 ;
     RECT  2.16 50.355 218.16 50.625 ;
     RECT  2.16 50.895 218.16 51.165 ;
     RECT  2.16 51.435 218.16 51.705 ;
     RECT  2.16 51.975 20.844 52.245 ;
     RECT  199.692 51.975 218.16 52.245 ;
     RECT  2.16 52.515 20.844 52.785 ;
     RECT  199.692 52.515 218.16 52.785 ;
     RECT  2.16 53.055 20.844 53.325 ;
     RECT  199.692 53.055 218.16 53.325 ;
     RECT  2.16 53.595 20.844 53.865 ;
     RECT  199.692 53.595 218.16 53.865 ;
     RECT  2.16 54.135 20.844 54.405 ;
     RECT  199.692 54.135 218.16 54.405 ;
     RECT  2.16 54.675 20.844 54.945 ;
     RECT  199.692 54.675 218.16 54.945 ;
     RECT  2.16 55.215 20.844 55.485 ;
     RECT  199.692 55.215 218.16 55.485 ;
     RECT  2.16 55.755 20.844 56.025 ;
     RECT  199.692 55.755 218.16 56.025 ;
     RECT  2.16 56.295 20.844 56.565 ;
     RECT  199.692 56.295 218.16 56.565 ;
     RECT  2.16 56.835 20.844 57.105 ;
     RECT  199.692 56.835 218.16 57.105 ;
     RECT  2.16 57.375 20.844 57.645 ;
     RECT  199.692 57.375 218.16 57.645 ;
     RECT  2.16 57.915 20.844 58.185 ;
     RECT  199.692 57.915 218.16 58.185 ;
     RECT  2.16 58.455 20.844 58.725 ;
     RECT  199.692 58.455 218.16 58.725 ;
     RECT  2.16 58.995 20.844 59.265 ;
     RECT  199.692 58.995 218.16 59.265 ;
     RECT  2.16 59.535 20.844 59.805 ;
     RECT  199.692 59.535 218.16 59.805 ;
     RECT  2.16 60.075 20.844 60.345 ;
     RECT  199.692 60.075 218.16 60.345 ;
     RECT  2.16 60.615 20.844 60.885 ;
     RECT  199.692 60.615 218.16 60.885 ;
     RECT  2.16 61.155 20.844 61.425 ;
     RECT  199.692 61.155 218.16 61.425 ;
     RECT  2.16 61.695 20.844 61.965 ;
     RECT  199.692 61.695 218.16 61.965 ;
     RECT  2.16 62.235 20.844 62.505 ;
     RECT  199.692 62.235 218.16 62.505 ;
     RECT  2.16 62.775 20.844 63.045 ;
     RECT  199.692 62.775 218.16 63.045 ;
     RECT  2.16 63.315 20.844 63.585 ;
     RECT  199.692 63.315 218.16 63.585 ;
     RECT  2.16 63.855 20.844 64.125 ;
     RECT  199.692 63.855 218.16 64.125 ;
     RECT  2.16 64.395 20.844 64.665 ;
     RECT  199.692 64.395 218.16 64.665 ;
     RECT  2.16 64.935 20.844 65.205 ;
     RECT  199.692 64.935 218.16 65.205 ;
     RECT  2.16 65.475 20.844 65.745 ;
     RECT  199.692 65.475 218.16 65.745 ;
     RECT  2.16 66.015 20.844 66.285 ;
     RECT  199.692 66.015 218.16 66.285 ;
     RECT  2.16 66.555 20.844 66.825 ;
     RECT  199.692 66.555 218.16 66.825 ;
     RECT  2.16 67.095 20.844 67.365 ;
     RECT  199.692 67.095 218.16 67.365 ;
     RECT  2.16 67.635 20.844 67.905 ;
     RECT  199.692 67.635 218.16 67.905 ;
     RECT  2.16 68.175 20.844 68.445 ;
     RECT  199.692 68.175 218.16 68.445 ;
     RECT  2.16 68.715 20.844 68.985 ;
     RECT  199.692 68.715 218.16 68.985 ;
     RECT  2.16 69.255 20.844 69.525 ;
     RECT  199.692 69.255 218.16 69.525 ;
     RECT  2.16 69.795 20.844 70.065 ;
     RECT  199.692 69.795 218.16 70.065 ;
     RECT  2.16 70.335 20.844 70.605 ;
     RECT  199.692 70.335 218.16 70.605 ;
     RECT  2.16 70.875 20.844 71.145 ;
     RECT  199.692 70.875 218.16 71.145 ;
     RECT  2.16 71.415 20.844 71.685 ;
     RECT  199.692 71.415 218.16 71.685 ;
     RECT  2.16 71.955 20.844 72.225 ;
     RECT  199.692 71.955 218.16 72.225 ;
     RECT  2.16 72.495 20.844 72.765 ;
     RECT  199.692 72.495 218.16 72.765 ;
     RECT  2.16 73.035 20.844 73.305 ;
     RECT  199.692 73.035 218.16 73.305 ;
     RECT  2.16 73.575 20.844 73.845 ;
     RECT  199.692 73.575 218.16 73.845 ;
     RECT  2.16 74.115 20.844 74.385 ;
     RECT  199.692 74.115 218.16 74.385 ;
     RECT  2.16 74.655 20.844 74.925 ;
     RECT  199.692 74.655 218.16 74.925 ;
     RECT  2.16 75.195 20.844 75.465 ;
     RECT  199.692 75.195 218.16 75.465 ;
     RECT  2.16 75.735 20.844 76.005 ;
     RECT  199.692 75.735 218.16 76.005 ;
     RECT  2.16 76.275 20.844 76.545 ;
     RECT  199.692 76.275 218.16 76.545 ;
     RECT  2.16 76.815 20.844 77.085 ;
     RECT  199.692 76.815 218.16 77.085 ;
     RECT  2.16 77.355 20.844 77.625 ;
     RECT  199.692 77.355 218.16 77.625 ;
     RECT  2.16 77.895 20.844 78.165 ;
     RECT  199.692 77.895 218.16 78.165 ;
     RECT  2.16 78.435 20.844 78.705 ;
     RECT  199.692 78.435 218.16 78.705 ;
     RECT  2.16 78.975 20.844 79.245 ;
     RECT  199.692 78.975 218.16 79.245 ;
     RECT  2.16 79.515 20.844 79.785 ;
     RECT  199.692 79.515 218.16 79.785 ;
     RECT  2.16 80.055 20.844 80.325 ;
     RECT  199.692 80.055 218.16 80.325 ;
     RECT  2.16 80.595 20.844 80.865 ;
     RECT  199.692 80.595 218.16 80.865 ;
     RECT  2.16 81.135 20.844 81.405 ;
     RECT  199.692 81.135 218.16 81.405 ;
     RECT  2.16 81.675 20.844 81.945 ;
     RECT  199.692 81.675 218.16 81.945 ;
     RECT  2.16 82.215 20.844 82.485 ;
     RECT  199.692 82.215 218.16 82.485 ;
     RECT  2.16 82.755 20.844 83.025 ;
     RECT  199.692 82.755 218.16 83.025 ;
     RECT  2.16 83.295 20.844 83.565 ;
     RECT  199.692 83.295 218.16 83.565 ;
     RECT  2.16 83.835 20.844 84.105 ;
     RECT  199.692 83.835 218.16 84.105 ;
     RECT  2.16 84.375 20.844 84.645 ;
     RECT  199.692 84.375 218.16 84.645 ;
     RECT  2.16 84.915 20.844 85.185 ;
     RECT  199.692 84.915 218.16 85.185 ;
     RECT  2.16 85.455 20.844 85.725 ;
     RECT  199.692 85.455 218.16 85.725 ;
     RECT  2.16 85.995 20.844 86.265 ;
     RECT  199.692 85.995 218.16 86.265 ;
     RECT  2.16 86.535 20.844 86.805 ;
     RECT  199.692 86.535 218.16 86.805 ;
     RECT  2.16 87.075 20.844 87.345 ;
     RECT  199.692 87.075 218.16 87.345 ;
     RECT  2.16 87.615 20.844 87.885 ;
     RECT  199.692 87.615 218.16 87.885 ;
     RECT  2.16 88.155 20.844 88.425 ;
     RECT  199.692 88.155 218.16 88.425 ;
     RECT  2.16 88.695 20.844 88.965 ;
     RECT  199.692 88.695 218.16 88.965 ;
     RECT  2.16 89.235 20.844 89.505 ;
     RECT  199.692 89.235 218.16 89.505 ;
     RECT  2.16 89.775 20.844 90.045 ;
     RECT  199.692 89.775 218.16 90.045 ;
     RECT  2.16 90.315 20.844 90.585 ;
     RECT  199.692 90.315 218.16 90.585 ;
     RECT  2.16 90.855 20.844 91.125 ;
     RECT  199.692 90.855 218.16 91.125 ;
     RECT  2.16 91.395 20.844 91.665 ;
     RECT  199.692 91.395 218.16 91.665 ;
     RECT  2.16 91.935 20.844 92.205 ;
     RECT  199.692 91.935 218.16 92.205 ;
     RECT  2.16 92.475 20.844 92.745 ;
     RECT  199.692 92.475 218.16 92.745 ;
     RECT  2.16 93.015 20.844 93.285 ;
     RECT  199.692 93.015 218.16 93.285 ;
     RECT  2.16 93.555 20.844 93.825 ;
     RECT  199.692 93.555 218.16 93.825 ;
     RECT  2.16 94.095 20.844 94.365 ;
     RECT  199.692 94.095 218.16 94.365 ;
     RECT  2.16 94.635 20.844 94.905 ;
     RECT  199.692 94.635 218.16 94.905 ;
     RECT  2.16 95.175 20.844 95.445 ;
     RECT  199.692 95.175 218.16 95.445 ;
     RECT  2.16 95.715 20.844 95.985 ;
     RECT  199.692 95.715 218.16 95.985 ;
     RECT  2.16 96.255 20.844 96.525 ;
     RECT  199.692 96.255 218.16 96.525 ;
     RECT  2.16 96.795 20.844 97.065 ;
     RECT  199.692 96.795 218.16 97.065 ;
     RECT  2.16 97.335 20.844 97.605 ;
     RECT  199.692 97.335 218.16 97.605 ;
     RECT  2.16 97.875 20.844 98.145 ;
     RECT  199.692 97.875 218.16 98.145 ;
     RECT  2.16 98.415 20.844 98.685 ;
     RECT  199.692 98.415 218.16 98.685 ;
     RECT  2.16 98.955 20.844 99.225 ;
     RECT  199.692 98.955 218.16 99.225 ;
     RECT  2.16 99.495 20.844 99.765 ;
     RECT  199.692 99.495 218.16 99.765 ;
     RECT  2.16 100.035 20.844 100.305 ;
     RECT  199.692 100.035 218.16 100.305 ;
     RECT  2.16 100.575 20.844 100.845 ;
     RECT  199.692 100.575 218.16 100.845 ;
     RECT  2.16 101.115 20.844 101.385 ;
     RECT  199.692 101.115 218.16 101.385 ;
     RECT  2.16 101.655 20.844 101.925 ;
     RECT  199.692 101.655 218.16 101.925 ;
     RECT  2.16 102.195 20.844 102.465 ;
     RECT  199.692 102.195 218.16 102.465 ;
     RECT  2.16 102.735 20.844 103.005 ;
     RECT  199.692 102.735 218.16 103.005 ;
     RECT  2.16 103.275 20.844 103.545 ;
     RECT  199.692 103.275 218.16 103.545 ;
     RECT  2.16 103.815 20.844 104.085 ;
     RECT  199.692 103.815 218.16 104.085 ;
     RECT  2.16 104.355 20.844 104.625 ;
     RECT  199.692 104.355 218.16 104.625 ;
     RECT  2.16 104.895 20.844 105.165 ;
     RECT  199.692 104.895 218.16 105.165 ;
     RECT  2.16 105.435 20.844 105.705 ;
     RECT  199.692 105.435 218.16 105.705 ;
     RECT  2.16 105.975 20.844 106.245 ;
     RECT  199.692 105.975 218.16 106.245 ;
     RECT  2.16 106.515 20.844 106.785 ;
     RECT  199.692 106.515 218.16 106.785 ;
     RECT  2.16 107.055 20.844 107.325 ;
     RECT  199.692 107.055 218.16 107.325 ;
     RECT  2.16 107.595 20.844 107.865 ;
     RECT  199.692 107.595 218.16 107.865 ;
     RECT  2.16 108.135 20.844 108.405 ;
     RECT  199.692 108.135 218.16 108.405 ;
     RECT  2.16 108.675 20.844 108.945 ;
     RECT  199.692 108.675 218.16 108.945 ;
     RECT  2.16 109.215 20.844 109.485 ;
     RECT  199.692 109.215 218.16 109.485 ;
     RECT  2.16 109.755 20.844 110.025 ;
     RECT  199.692 109.755 218.16 110.025 ;
     RECT  2.16 110.295 20.844 110.565 ;
     RECT  199.692 110.295 218.16 110.565 ;
     RECT  2.16 110.835 20.844 111.105 ;
     RECT  199.692 110.835 218.16 111.105 ;
     RECT  2.16 111.375 20.844 111.645 ;
     RECT  199.692 111.375 218.16 111.645 ;
     RECT  2.16 111.915 20.844 112.185 ;
     RECT  199.692 111.915 218.16 112.185 ;
     RECT  2.16 112.455 20.844 112.725 ;
     RECT  199.692 112.455 218.16 112.725 ;
     RECT  2.16 112.995 20.844 113.265 ;
     RECT  199.692 112.995 218.16 113.265 ;
     RECT  2.16 113.535 20.844 113.805 ;
     RECT  199.692 113.535 218.16 113.805 ;
     RECT  2.16 114.075 20.844 114.345 ;
     RECT  199.692 114.075 218.16 114.345 ;
     RECT  2.16 114.615 20.844 114.885 ;
     RECT  199.692 114.615 218.16 114.885 ;
     RECT  2.16 115.155 20.844 115.425 ;
     RECT  199.692 115.155 218.16 115.425 ;
     RECT  2.16 115.695 20.844 115.965 ;
     RECT  199.692 115.695 218.16 115.965 ;
     RECT  2.16 116.235 20.844 116.505 ;
     RECT  199.692 116.235 218.16 116.505 ;
     RECT  2.16 116.775 20.844 117.045 ;
     RECT  199.692 116.775 218.16 117.045 ;
     RECT  2.16 117.315 20.844 117.585 ;
     RECT  199.692 117.315 218.16 117.585 ;
     RECT  2.16 117.855 20.844 118.125 ;
     RECT  199.692 117.855 218.16 118.125 ;
     RECT  2.16 118.395 20.844 118.665 ;
     RECT  199.692 118.395 218.16 118.665 ;
     RECT  2.16 118.935 20.844 119.205 ;
     RECT  199.692 118.935 218.16 119.205 ;
     RECT  2.16 119.475 20.844 119.745 ;
     RECT  199.692 119.475 218.16 119.745 ;
     RECT  2.16 120.015 20.844 120.285 ;
     RECT  199.692 120.015 218.16 120.285 ;
     RECT  2.16 120.555 20.844 120.825 ;
     RECT  199.692 120.555 218.16 120.825 ;
     RECT  2.16 121.095 20.844 121.365 ;
     RECT  199.692 121.095 218.16 121.365 ;
     RECT  2.16 121.635 20.844 121.905 ;
     RECT  199.692 121.635 218.16 121.905 ;
     RECT  2.16 122.175 20.844 122.445 ;
     RECT  199.692 122.175 218.16 122.445 ;
     RECT  2.16 122.715 20.844 122.985 ;
     RECT  199.692 122.715 218.16 122.985 ;
     RECT  2.16 123.255 20.844 123.525 ;
     RECT  199.692 123.255 218.16 123.525 ;
     RECT  2.16 123.795 20.844 124.065 ;
     RECT  199.692 123.795 218.16 124.065 ;
     RECT  2.16 124.335 20.844 124.605 ;
     RECT  199.692 124.335 218.16 124.605 ;
     RECT  2.16 124.875 20.844 125.145 ;
     RECT  199.692 124.875 218.16 125.145 ;
     RECT  2.16 125.415 20.844 125.685 ;
     RECT  199.692 125.415 218.16 125.685 ;
     RECT  2.16 125.955 20.844 126.225 ;
     RECT  199.692 125.955 218.16 126.225 ;
     RECT  2.16 126.495 20.844 126.63 ;
     RECT  199.692 126.495 218.16 126.63 ;
     RECT  2.16 126.63 218.16 126.765 ;
     RECT  2.16 127.035 218.16 127.305 ;
     RECT  2.16 127.575 218.16 127.845 ;
     RECT  2.16 128.115 218.16 128.385 ;
     RECT  2.16 128.655 218.16 128.925 ;
     RECT  2.16 129.195 218.16 129.465 ;
     RECT  2.16 129.735 218.16 130.005 ;
     RECT  2.16 130.275 218.16 130.545 ;
     RECT  2.16 130.815 218.16 131.085 ;
     RECT  2.16 131.355 218.16 131.625 ;
     RECT  2.16 131.895 218.16 132.165 ;
     RECT  2.16 132.435 218.16 132.705 ;
     RECT  2.16 132.975 218.16 133.245 ;
     RECT  2.16 133.515 218.16 133.785 ;
     RECT  2.16 134.055 218.16 134.325 ;
     RECT  2.16 134.595 218.16 134.865 ;
     RECT  2.16 135.135 218.16 135.405 ;
     RECT  2.16 135.675 218.16 135.945 ;
     RECT  2.16 136.215 218.16 136.485 ;
     RECT  2.16 136.755 218.16 137.025 ;
     RECT  2.16 137.295 218.16 137.565 ;
     RECT  2.16 137.835 218.16 138.105 ;
     RECT  2.16 138.375 218.16 138.645 ;
     RECT  2.16 138.915 218.16 139.185 ;
     RECT  2.16 139.455 218.16 139.725 ;
     RECT  2.16 139.995 218.16 140.265 ;
     RECT  2.16 140.535 218.16 140.805 ;
     RECT  2.16 141.075 218.16 141.345 ;
     RECT  2.16 141.615 218.16 141.885 ;
     RECT  2.16 142.155 218.16 142.425 ;
     RECT  2.16 142.695 218.16 142.965 ;
     RECT  2.16 143.235 218.16 143.505 ;
     RECT  2.16 143.775 218.16 144.045 ;
     RECT  2.16 144.315 218.16 144.585 ;
     RECT  2.16 144.855 218.16 145.125 ;
     RECT  2.16 145.395 218.16 145.665 ;
     RECT  2.16 145.935 218.16 146.205 ;
     RECT  2.16 146.475 218.16 146.745 ;
     RECT  2.16 147.015 218.16 147.285 ;
     RECT  2.16 147.555 218.16 147.825 ;
     RECT  2.16 148.095 218.16 148.365 ;
     RECT  2.16 148.635 218.16 148.905 ;
     RECT  2.16 149.175 218.16 149.445 ;
     RECT  2.16 149.715 218.16 149.985 ;
     RECT  2.16 150.255 218.16 150.525 ;
     RECT  2.16 150.795 218.16 151.065 ;
     RECT  2.16 151.335 218.16 151.605 ;
     RECT  2.16 151.875 218.16 152.145 ;
     RECT  2.16 152.415 218.16 152.685 ;
     RECT  2.16 152.955 218.16 153.225 ;
     RECT  2.16 153.495 218.16 153.765 ;
     RECT  2.16 154.035 218.16 154.305 ;
     RECT  2.16 154.575 218.16 154.845 ;
     RECT  2.16 155.115 218.16 155.385 ;
     RECT  2.16 155.655 218.16 155.925 ;
     RECT  2.16 156.195 218.16 156.465 ;
     RECT  2.16 156.735 218.16 157.005 ;
     RECT  2.16 157.275 218.16 157.545 ;
     RECT  2.16 157.815 218.16 158.085 ;
     RECT  2.16 158.355 218.16 158.625 ;
     RECT  2.16 158.895 218.16 159.165 ;
     RECT  2.16 159.435 218.16 159.705 ;
     RECT  2.16 159.975 218.16 160.245 ;
     RECT  2.16 160.515 218.16 160.785 ;
     RECT  2.16 161.055 218.16 161.325 ;
     RECT  2.16 161.595 218.16 161.865 ;
     RECT  2.16 162.135 218.16 162.405 ;
     RECT  2.16 162.675 218.16 162.945 ;
     RECT  2.16 163.215 218.16 163.485 ;
     RECT  2.16 163.755 218.16 164.025 ;
     RECT  2.16 164.295 218.16 164.565 ;
     RECT  2.16 164.835 218.16 165.105 ;
     RECT  2.16 165.375 218.16 165.645 ;
     RECT  2.16 165.915 218.16 166.185 ;
     RECT  2.16 166.455 218.16 166.725 ;
     RECT  2.16 166.995 218.16 167.265 ;
     RECT  2.16 167.535 218.16 167.805 ;
     RECT  2.16 168.075 218.16 168.345 ;
     RECT  2.16 168.615 218.16 168.885 ;
     RECT  2.16 169.155 218.16 169.425 ;
     RECT  2.16 169.695 218.16 169.965 ;
     RECT  2.16 170.235 218.16 170.505 ;
     RECT  2.16 170.775 218.16 171.045 ;
     RECT  2.16 171.315 218.16 171.585 ;
     RECT  2.16 171.855 218.16 172.125 ;
     RECT  2.16 172.395 218.16 172.665 ;
     RECT  2.16 172.935 218.16 173.205 ;
     RECT  2.16 173.475 218.16 173.745 ;
     RECT  2.16 174.015 218.16 174.285 ;
     RECT  2.16 174.555 218.16 174.825 ;
    LAYER M1 ;
     RECT  2.16 2.151 218.16 51.849 ;
     RECT  22.896 54 197.64 124.488 ;
     RECT  2.16 51.849 20.844 126.621 ;
     RECT  199.692 51.849 218.16 126.621 ;
     RECT  2.16 126.621 218.16 174.969 ;
    LAYER M2 ;
     RECT  0.103 57.924 0.139 58.41 ;
     RECT  0.103 59.742 0.139 60.84 ;
     RECT  0.103 63.828 0.139 64.08 ;
     RECT  0.103 81.18 0.139 81.738 ;
     RECT  0.103 82.8 0.139 82.818 ;
     RECT  0.103 88.776 0.139 89.766 ;
     RECT  0.103 91.638 0.139 91.656 ;
     RECT  0.103 93.906 0.139 94.59 ;
     RECT  0.103 96.192 0.139 96.21 ;
     RECT  0.139 81.18 0.175 81.9 ;
     RECT  0.103 85.932 0.175 87.138 ;
     RECT  0.139 88.632 0.175 89.766 ;
     RECT  0.139 90.594 0.175 90.612 ;
     RECT  0.139 93.87 0.175 96.21 ;
     RECT  0.103 55.962 0.211 57.06 ;
     RECT  0.139 57.924 0.211 60.84 ;
     RECT  0.139 82.8 0.211 83.016 ;
     RECT  0.175 88.632 0.211 90.612 ;
     RECT  0.139 91.404 0.211 91.656 ;
     RECT  0.139 97.542 0.211 97.56 ;
     RECT  0.175 85.428 0.499 87.138 ;
     RECT  0.211 88.632 0.499 91.656 ;
     RECT  0.103 49.212 0.535 51.768 ;
     RECT  0.103 62.442 0.535 62.874 ;
     RECT  0.139 63.828 0.535 64.386 ;
     RECT  0.175 93.87 0.535 96.246 ;
     RECT  0.211 97.542 0.571 97.83 ;
     RECT  0.103 52.596 1.147 54.63 ;
     RECT  0.535 62.442 1.147 64.764 ;
     RECT  0.103 66.222 1.147 66.24 ;
     RECT  0.211 82.8 1.147 83.628 ;
     RECT  0.103 84.582 1.147 84.6 ;
     RECT  0.103 92.754 1.147 92.772 ;
     RECT  0.535 93.636 1.147 96.246 ;
     RECT  1.147 92.682 1.183 92.772 ;
     RECT  1.147 93.636 1.183 96.318 ;
     RECT  1.183 92.682 1.219 96.318 ;
     RECT  1.219 92.682 1.255 96.588 ;
     RECT  0.571 97.542 1.255 98.1 ;
     RECT  0.211 55.962 1.363 60.84 ;
     RECT  0.175 80.64 1.723 81.9 ;
     RECT  1.147 82.8 1.723 84.6 ;
     RECT  0.499 85.428 1.723 91.656 ;
     RECT  0.535 48.78 2.16 51.768 ;
     RECT  1.147 52.524 2.16 54.63 ;
     RECT  1.363 55.53 2.16 60.84 ;
     RECT  1.147 61.704 2.16 64.764 ;
     RECT  1.147 65.952 2.16 66.24 ;
     RECT  1.723 80.64 2.16 91.656 ;
     RECT  1.255 92.682 2.16 98.1 ;
     RECT  2.16 2.151 14.647 174.969 ;
     RECT  14.647 2.106 15.395 174.969 ;
     RECT  15.395 2.151 19.903 174.969 ;
     RECT  19.903 2.106 19.939 174.969 ;
     RECT  19.939 2.034 20.844 174.969 ;
     RECT  20.844 2.034 20.939 60.948 ;
     RECT  20.939 59.976 20.975 60.948 ;
     RECT  20.975 59.976 21.047 60.174 ;
     RECT  20.939 2.034 21.083 59.184 ;
     RECT  20.844 64.674 21.083 94.734 ;
     RECT  21.047 60.156 21.119 60.174 ;
     RECT  20.844 61.776 21.155 63.81 ;
     RECT  21.083 2.034 21.191 58.284 ;
     RECT  21.083 64.674 21.587 86.994 ;
     RECT  21.083 87.966 21.659 94.284 ;
     RECT  21.083 59.076 21.695 59.184 ;
     RECT  21.155 63.792 21.695 63.81 ;
     RECT  21.587 69.336 21.695 86.994 ;
     RECT  21.695 59.166 21.731 59.184 ;
     RECT  21.191 2.106 21.911 58.284 ;
     RECT  21.911 2.106 21.947 57.564 ;
     RECT  21.947 2.151 22.019 57.564 ;
     RECT  22.019 2.151 22.896 54.819 ;
     RECT  22.019 55.566 22.896 57.564 ;
     RECT  22.531 58.392 22.896 58.41 ;
     RECT  20.975 60.93 22.896 60.948 ;
     RECT  21.155 61.776 22.896 63.036 ;
     RECT  21.587 64.674 22.896 68.544 ;
     RECT  21.695 69.426 22.896 86.994 ;
     RECT  21.659 87.966 22.896 90.27 ;
     RECT  21.659 91.026 22.896 94.284 ;
     RECT  20.844 98.856 22.896 98.874 ;
     RECT  20.844 101.736 22.896 101.754 ;
     RECT  20.844 114.966 22.896 114.984 ;
     RECT  20.844 125.118 22.896 174.969 ;
     RECT  22.896 2.151 197.64 174.969 ;
     RECT  197.64 55.53 198.059 55.746 ;
     RECT  198.059 55.728 198.203 55.746 ;
     RECT  197.64 58.626 198.311 59.634 ;
     RECT  197.64 57.006 198.383 57.474 ;
     RECT  197.64 65.106 198.383 66.042 ;
     RECT  197.64 68.148 198.391 94.392 ;
     RECT  197.64 2.151 198.535 54.666 ;
     RECT  198.383 57.186 198.535 57.474 ;
     RECT  198.391 97.236 198.607 97.254 ;
     RECT  198.391 68.148 198.643 94.428 ;
     RECT  198.535 2.151 198.671 54.738 ;
     RECT  198.535 57.186 198.671 57.564 ;
     RECT  198.311 58.932 198.895 59.634 ;
     RECT  198.383 65.286 198.895 66.042 ;
     RECT  198.895 65.286 198.931 66.114 ;
     RECT  197.64 67.068 198.931 67.086 ;
     RECT  198.607 96.606 199.183 97.254 ;
     RECT  198.931 65.286 199.327 67.086 ;
     RECT  198.643 68.148 199.327 95.004 ;
     RECT  198.895 58.932 199.471 60.372 ;
     RECT  199.183 96.606 199.651 97.434 ;
     RECT  199.363 62.676 199.687 62.694 ;
     RECT  198.671 2.151 199.692 54.666 ;
     RECT  198.671 57.186 199.692 57.438 ;
     RECT  199.471 58.932 199.692 60.984 ;
     RECT  199.687 62.406 199.692 62.694 ;
     RECT  199.327 65.286 199.692 95.004 ;
     RECT  199.651 96.426 199.692 97.434 ;
     RECT  197.64 125.118 199.692 174.969 ;
     RECT  199.692 2.151 218.16 174.969 ;
     RECT  218.16 52.956 218.327 64.152 ;
     RECT  218.16 65.106 218.651 72.864 ;
     RECT  218.651 65.106 218.831 71.604 ;
     RECT  218.327 52.956 218.867 55.584 ;
     RECT  218.327 57.276 218.867 64.152 ;
     RECT  218.831 65.106 218.867 71.244 ;
     RECT  218.867 58.356 218.903 60.444 ;
     RECT  218.867 61.236 218.903 64.152 ;
     RECT  218.867 70.578 218.903 71.244 ;
     RECT  218.903 61.434 218.939 64.152 ;
     RECT  218.651 72.504 219.155 72.864 ;
     RECT  218.867 57.276 219.371 57.564 ;
     RECT  219.371 57.276 219.407 57.474 ;
     RECT  219.407 57.384 219.443 57.474 ;
     RECT  218.903 58.626 219.443 60.444 ;
     RECT  218.867 65.106 219.443 69.822 ;
     RECT  218.903 70.578 219.443 70.974 ;
     RECT  218.867 52.956 219.479 55.206 ;
     RECT  219.443 58.626 219.479 60.264 ;
     RECT  218.939 61.434 219.479 64.044 ;
     RECT  219.443 65.718 219.479 69.714 ;
     RECT  219.479 53.37 219.515 54.774 ;
     RECT  219.515 53.838 219.551 54.774 ;
     RECT  219.479 62.784 219.551 63.918 ;
     RECT  219.551 54.72 219.587 54.774 ;
     RECT  219.551 62.784 219.587 63.846 ;
     RECT  219.551 53.838 219.623 53.928 ;
     RECT  219.155 72.504 220.091 72.684 ;
     RECT  219.479 65.718 220.163 68.778 ;
     RECT  219.479 69.696 220.163 69.714 ;
     RECT  220.091 72.504 220.163 72.594 ;
     RECT  219.479 58.626 220.199 58.644 ;
     RECT  219.479 59.976 220.199 60.264 ;
     RECT  220.163 66.186 220.199 66.312 ;
     RECT  220.163 67.068 220.199 68.778 ;
     RECT  219.443 70.956 220.199 70.974 ;
     RECT  218.327 56.466 220.235 56.484 ;
     RECT  219.443 57.456 220.235 57.474 ;
     RECT  220.199 60.246 220.235 60.264 ;
     RECT  219.587 62.784 220.235 62.802 ;
     RECT  219.587 63.828 220.235 63.846 ;
     RECT  220.199 66.294 220.235 66.312 ;
     RECT  220.199 67.068 220.235 68.706 ;
     RECT  220.163 72.54 220.235 72.594 ;
     RECT  219.623 53.838 220.271 53.856 ;
     RECT  219.587 54.72 220.271 54.738 ;
     RECT  220.235 68.22 220.307 68.238 ;
     RECT  220.235 72.54 220.307 72.558 ;
    LAYER M3 ;
     RECT  7.02 0.091 7.038 0.139 ;
     RECT  7.02 0.139 7.29 0.571 ;
     RECT  15.948 0.571 15.966 0.619 ;
     RECT  15.948 0.619 16.11 0.667 ;
     RECT  16.848 0.091 18.09 0.667 ;
     RECT  15.948 0.667 18.09 0.715 ;
     RECT  6.948 0.571 7.29 1.147 ;
     RECT  15.372 0.715 18.09 1.147 ;
     RECT  19.26 0.571 19.278 1.723 ;
     RECT  19.26 1.723 19.566 1.771 ;
     RECT  19.26 1.771 19.962 1.819 ;
     RECT  19.26 1.819 20.61 2.029 ;
     RECT  15.372 1.147 18.306 2.059 ;
     RECT  19.26 2.029 21.186 2.059 ;
     RECT  15.372 2.059 21.186 2.101 ;
     RECT  6.948 1.147 7.722 2.143 ;
     RECT  6.948 2.143 7.905 2.191 ;
     RECT  14.652 2.101 21.186 2.191 ;
     RECT  21.924 2.101 21.942 2.191 ;
     RECT  6.876 2.191 8.154 2.371 ;
     RECT  2.415 2.143 2.505 2.413 ;
     RECT  13.215 2.143 13.305 2.413 ;
     RECT  24.015 2.143 24.105 2.413 ;
     RECT  29.415 2.143 29.505 2.413 ;
     RECT  34.815 2.143 34.905 2.413 ;
     RECT  40.215 2.143 40.305 2.413 ;
     RECT  45.615 2.143 45.705 2.413 ;
     RECT  51.015 2.143 51.105 2.413 ;
     RECT  56.415 2.143 56.505 2.413 ;
     RECT  61.815 2.143 61.905 2.413 ;
     RECT  67.215 2.143 67.305 2.413 ;
     RECT  72.615 2.143 72.705 2.413 ;
     RECT  78.015 2.143 78.105 2.413 ;
     RECT  83.415 2.143 83.505 2.413 ;
     RECT  88.815 2.143 88.905 2.413 ;
     RECT  94.215 2.143 94.305 2.413 ;
     RECT  99.615 2.143 99.705 2.413 ;
     RECT  105.015 2.143 105.105 2.413 ;
     RECT  110.415 2.143 110.505 2.413 ;
     RECT  115.815 2.143 115.905 2.413 ;
     RECT  121.215 2.143 121.305 2.413 ;
     RECT  126.615 2.143 126.705 2.413 ;
     RECT  132.015 2.143 132.105 2.413 ;
     RECT  137.415 2.143 137.505 2.413 ;
     RECT  142.815 2.143 142.905 2.413 ;
     RECT  148.215 2.143 148.305 2.413 ;
     RECT  153.615 2.143 153.705 2.413 ;
     RECT  159.015 2.143 159.105 2.413 ;
     RECT  164.415 2.143 164.505 2.413 ;
     RECT  169.815 2.143 169.905 2.413 ;
     RECT  175.215 2.143 175.305 2.413 ;
     RECT  180.615 2.143 180.705 2.413 ;
     RECT  186.015 2.143 186.105 2.413 ;
     RECT  191.415 2.143 191.505 2.413 ;
     RECT  196.815 2.143 196.905 2.413 ;
     RECT  202.215 2.143 202.305 2.413 ;
     RECT  207.615 2.143 207.705 2.413 ;
     RECT  213.015 2.143 213.105 2.413 ;
     RECT  6.48 2.371 8.154 2.461 ;
     RECT  14.652 2.191 21.942 2.461 ;
     RECT  6.48 2.461 8.37 2.489 ;
     RECT  6.732 2.489 8.37 2.561 ;
     RECT  14.544 2.461 21.942 2.641 ;
     RECT  14.544 2.641 21.978 2.731 ;
     RECT  14.544 2.731 22.374 2.861 ;
     RECT  14.544 2.861 21.978 2.875 ;
     RECT  6.84 2.561 8.226 3.029 ;
     RECT  14.4 2.875 21.978 3.451 ;
     RECT  13.215 2.413 13.497 3.541 ;
     RECT  14.256 3.451 21.978 3.541 ;
     RECT  6.984 3.029 8.226 3.721 ;
     RECT  13.215 3.541 21.978 3.721 ;
     RECT  6.984 3.721 8.334 3.839 ;
     RECT  13.215 3.721 22.194 3.875 ;
     RECT  6.984 3.839 8.226 3.883 ;
     RECT  6.624 3.883 8.226 3.931 ;
     RECT  6.048 3.931 8.226 4.109 ;
     RECT  13.215 3.875 22.086 4.123 ;
     RECT  12.564 4.123 22.086 4.495 ;
     RECT  12.528 4.495 22.086 4.765 ;
     RECT  6.048 4.109 8.154 4.829 ;
     RECT  12.348 4.765 22.086 4.999 ;
     RECT  9.576 4.891 9.594 5.071 ;
     RECT  6.228 4.829 8.154 5.305 ;
     RECT  9.252 5.071 9.594 5.305 ;
     RECT  12.06 4.999 22.086 5.341 ;
     RECT  11.808 5.341 22.086 5.575 ;
     RECT  11.808 5.575 22.158 5.707 ;
     RECT  6.228 5.305 9.594 5.881 ;
     RECT  5.868 5.881 10.278 5.971 ;
     RECT  11.268 5.707 22.158 5.971 ;
     RECT  5.868 5.971 22.158 6.115 ;
     RECT  5.868 6.115 22.878 6.269 ;
     RECT  6.012 6.269 22.554 6.809 ;
     RECT  6.012 6.809 22.014 7.079 ;
     RECT  6.012 7.079 21.762 7.151 ;
     RECT  6.408 7.151 21.762 7.223 ;
     RECT  6.624 7.223 21.762 7.349 ;
     RECT  6.624 7.349 21.69 7.385 ;
     RECT  13.14 7.385 21.69 7.961 ;
     RECT  6.624 7.385 12.402 7.963 ;
     RECT  6.3 7.963 12.402 8.159 ;
     RECT  7.092 8.159 12.402 8.203 ;
     RECT  13.14 7.961 21.654 8.203 ;
     RECT  6.3 8.159 6.318 8.303 ;
     RECT  7.092 8.203 21.654 8.429 ;
     RECT  7.38 8.429 21.654 8.501 ;
     RECT  7.815 8.501 21.654 8.699 ;
     RECT  7.815 8.699 9.162 8.771 ;
     RECT  9.936 8.699 21.654 8.815 ;
     RECT  9.936 8.815 22.266 9.581 ;
     RECT  7.815 8.771 9.126 9.625 ;
     RECT  9.936 9.581 13.59 9.625 ;
     RECT  14.328 9.581 22.266 9.653 ;
     RECT  14.328 9.653 21.474 9.779 ;
     RECT  22.248 9.653 22.266 9.779 ;
     RECT  7.815 9.625 13.59 10.157 ;
     RECT  14.328 9.779 21.366 10.319 ;
     RECT  8.928 10.157 13.59 10.435 ;
     RECT  14.328 10.319 21.258 10.435 ;
     RECT  8.928 10.435 21.258 10.589 ;
     RECT  9.756 10.589 20.718 10.697 ;
     RECT  8.928 10.589 8.946 10.733 ;
     RECT  12.024 10.697 20.718 11.399 ;
     RECT  9.756 10.697 11.178 11.419 ;
     RECT  9.144 11.419 11.178 11.479 ;
     RECT  12.024 11.399 20.394 11.479 ;
     RECT  9.144 11.479 20.394 11.705 ;
     RECT  9.756 11.705 20.394 11.747 ;
     RECT  19.62 11.747 20.394 11.789 ;
     RECT  9.756 11.747 18.897 11.813 ;
     RECT  9.756 11.813 16.938 11.849 ;
     RECT  11.484 11.849 16.938 11.939 ;
     RECT  17.676 11.813 18.897 11.939 ;
     RECT  19.62 11.789 19.638 11.939 ;
     RECT  20.376 11.789 20.394 11.939 ;
     RECT  17.676 11.939 17.694 11.975 ;
     RECT  18.504 11.939 18.897 11.975 ;
     RECT  11.484 11.939 16.722 12.083 ;
     RECT  11.484 12.083 13.497 12.209 ;
     RECT  11.484 12.209 12.438 12.245 ;
     RECT  14.868 12.083 16.722 12.281 ;
     RECT  12.06 12.245 12.438 12.389 ;
     RECT  14.868 12.281 15.678 12.389 ;
     RECT  12.204 12.389 12.438 12.479 ;
     RECT  12.204 12.479 12.222 12.515 ;
     RECT  16.416 12.281 16.722 14.711 ;
     RECT  14.868 12.389 15.606 14.791 ;
     RECT  16.416 14.711 16.434 14.791 ;
     RECT  10.332 11.849 10.35 33.539 ;
     RECT  14.868 14.791 16.434 33.583 ;
     RECT  13.176 12.209 13.497 33.817 ;
     RECT  13.176 33.817 13.878 33.961 ;
     RECT  126.615 2.413 126.897 33.961 ;
     RECT  126.36 33.961 126.897 34.013 ;
     RECT  13.176 33.961 14.022 34.501 ;
     RECT  14.76 33.583 16.434 34.501 ;
     RECT  13.176 34.501 16.434 34.861 ;
     RECT  124.848 33.961 124.866 34.889 ;
     RECT  13.068 34.861 16.434 34.925 ;
     RECT  13.176 34.925 16.434 35.069 ;
     RECT  132.015 2.413 132.297 35.131 ;
     RECT  153.615 2.413 153.897 35.131 ;
     RECT  164.415 2.413 164.697 35.131 ;
     RECT  175.215 2.413 175.497 35.131 ;
     RECT  186.015 2.413 186.297 35.131 ;
     RECT  196.815 2.413 197.097 35.131 ;
     RECT  131.904 35.131 132.297 35.168 ;
     RECT  140.04 35.131 140.058 35.168 ;
     RECT  153.504 35.131 153.897 35.168 ;
     RECT  164.304 35.131 164.697 35.168 ;
     RECT  175.104 35.131 175.497 35.168 ;
     RECT  185.904 35.131 186.297 35.168 ;
     RECT  196.704 35.131 197.097 35.168 ;
     RECT  13.215 35.069 16.434 35.231 ;
     RECT  140.76 35.227 140.778 35.339 ;
     RECT  13.215 35.231 13.497 37.003 ;
     RECT  13.215 37.003 13.626 37.021 ;
     RECT  14.4 35.231 16.434 37.021 ;
     RECT  13.215 37.021 16.434 38.669 ;
     RECT  108.18 39.208 108.198 39.245 ;
     RECT  109.296 39.181 109.314 39.253 ;
     RECT  206.82 38.713 206.838 39.289 ;
     RECT  207.615 2.413 207.897 39.289 ;
     RECT  109.296 39.253 109.494 39.293 ;
     RECT  132.015 35.168 132.297 39.595 ;
     RECT  110.415 2.413 110.697 39.721 ;
     RECT  109.98 39.721 110.697 39.773 ;
     RECT  109.152 39.739 109.17 39.785 ;
     RECT  85.932 39.307 85.95 39.787 ;
     RECT  10.512 33.583 10.53 39.865 ;
     RECT  11.664 36.211 11.682 39.865 ;
     RECT  85.932 39.787 86.094 39.865 ;
     RECT  131.976 39.595 132.297 39.865 ;
     RECT  83.415 2.413 83.697 40.075 ;
     RECT  83.376 40.075 83.697 40.123 ;
     RECT  85.932 39.865 86.706 40.171 ;
     RECT  29.415 2.413 29.697 40.261 ;
     RECT  45.615 2.413 45.897 40.267 ;
     RECT  66.168 39.835 66.186 40.267 ;
     RECT  67.215 2.413 67.497 40.267 ;
     RECT  68.508 40.261 68.526 40.267 ;
     RECT  74.592 40.027 75.222 40.289 ;
     RECT  144.108 40.171 144.126 40.289 ;
     RECT  45.615 40.267 45.99 40.297 ;
     RECT  126.615 34.013 126.897 40.297 ;
     RECT  28.692 40.261 29.697 40.301 ;
     RECT  69.624 40.261 69.642 40.301 ;
     RECT  121.215 2.413 121.497 40.333 ;
     RECT  25.308 40.261 25.326 40.349 ;
     RECT  29.052 40.301 29.697 40.349 ;
     RECT  66.168 40.267 67.59 40.361 ;
     RECT  115.815 2.413 116.097 40.369 ;
     RECT  203.832 40.333 203.85 40.369 ;
     RECT  25.992 40.36 26.01 40.397 ;
     RECT  42.768 40.267 42.786 40.397 ;
     RECT  66.168 40.361 67.497 40.397 ;
     RECT  68.508 40.267 68.634 40.397 ;
     RECT  194.364 40.267 194.382 40.397 ;
     RECT  13.215 38.669 14.346 40.405 ;
     RECT  15.192 38.669 16.434 40.405 ;
     RECT  13.215 40.405 16.434 40.445 ;
     RECT  94.215 2.413 94.497 40.603 ;
     RECT  112.968 39.289 112.986 40.699 ;
     RECT  45.615 40.297 46.098 40.711 ;
     RECT  153.615 35.168 153.897 40.801 ;
     RECT  206.82 39.289 207.897 40.801 ;
     RECT  94.215 40.603 94.986 40.829 ;
     RECT  41.292 40.801 41.31 40.837 ;
     RECT  150.588 40.711 150.606 40.837 ;
     RECT  88.815 2.413 89.097 40.873 ;
     RECT  129.78 40.651 129.798 40.873 ;
     RECT  203.76 40.369 203.85 40.873 ;
     RECT  96.084 40.837 96.102 40.877 ;
     RECT  196.815 35.168 197.097 40.909 ;
     RECT  26.064 40.801 26.082 40.925 ;
     RECT  27.18 40.837 27.27 40.925 ;
     RECT  22.86 40.837 22.878 40.937 ;
     RECT  27.252 40.925 27.27 40.937 ;
     RECT  38.808 40.837 38.826 40.937 ;
     RECT  41.292 40.837 42.066 40.937 ;
     RECT  88.308 40.873 89.097 40.945 ;
     RECT  191.415 2.413 191.697 40.945 ;
     RECT  41.292 40.937 41.994 40.973 ;
     RECT  6.732 40.945 6.75 40.981 ;
     RECT  7.815 10.157 8.097 40.981 ;
     RECT  100.98 40.909 100.998 40.981 ;
     RECT  145.656 40.441 145.674 40.981 ;
     RECT  85.932 40.171 86.958 41.099 ;
     RECT  120.96 40.333 121.497 41.179 ;
     RECT  110.415 39.773 110.697 41.215 ;
     RECT  24.015 2.413 24.297 41.251 ;
     RECT  118.584 41.179 118.602 41.251 ;
     RECT  98.784 38.713 98.802 41.341 ;
     RECT  99.615 2.413 99.897 41.341 ;
     RECT  105.015 2.413 105.297 41.341 ;
     RECT  106.596 41.215 106.614 41.341 ;
     RECT  21.42 41.341 21.438 41.368 ;
     RECT  104.688 41.341 105.297 41.368 ;
     RECT  88.164 40.945 89.097 41.377 ;
     RECT  112.824 40.699 112.986 41.377 ;
     RECT  118.548 41.251 118.602 41.377 ;
     RECT  21.42 41.368 22.122 41.405 ;
     RECT  104.688 41.368 105.822 41.405 ;
     RECT  120.96 41.179 121.626 41.405 ;
     RECT  43.488 40.441 43.506 41.413 ;
     RECT  20.196 40.873 20.214 41.449 ;
     RECT  118.548 41.377 118.674 41.449 ;
     RECT  191.34 40.945 191.697 41.449 ;
     RECT  106.596 41.341 106.758 41.453 ;
     RECT  107.856 41.377 107.874 41.453 ;
     RECT  88.164 41.377 89.154 41.477 ;
     RECT  99.615 41.341 99.954 41.477 ;
     RECT  106.596 41.453 106.686 41.477 ;
     RECT  110.415 41.215 110.79 41.477 ;
     RECT  159.015 2.413 159.297 41.485 ;
     RECT  71.352 41.449 71.37 41.501 ;
     RECT  104.688 41.405 105.297 41.501 ;
     RECT  24.015 41.251 25.002 41.512 ;
     RECT  34.815 2.413 35.097 41.512 ;
     RECT  45.615 40.711 46.206 41.512 ;
     RECT  56.415 2.413 56.697 41.512 ;
     RECT  67.215 40.397 67.497 41.512 ;
     RECT  78.015 2.413 78.297 41.512 ;
     RECT  98.604 41.341 98.802 41.512 ;
     RECT  99.615 41.477 99.897 41.512 ;
     RECT  110.415 41.477 110.718 41.512 ;
     RECT  126.576 40.297 126.897 41.515 ;
     RECT  19.944 41.449 20.214 41.521 ;
     RECT  85.176 41.449 85.194 41.521 ;
     RECT  22.824 41.413 22.842 41.549 ;
     RECT  30.78 41.413 30.798 41.549 ;
     RECT  34.704 41.512 35.097 41.549 ;
     RECT  42.768 41.413 43.506 41.549 ;
     RECT  54.792 41.377 54.81 41.549 ;
     RECT  56.304 41.512 56.697 41.549 ;
     RECT  85.932 41.099 86.742 41.549 ;
     RECT  106.668 41.477 106.686 41.549 ;
     RECT  110.304 41.512 110.718 41.549 ;
     RECT  118.548 41.449 118.746 41.549 ;
     RECT  71.712 41.521 71.73 41.597 ;
     RECT  23.904 41.512 25.002 41.755 ;
     RECT  115.524 40.369 116.097 41.755 ;
     RECT  98.604 41.512 99.897 41.791 ;
     RECT  195.552 41.413 195.57 41.791 ;
     RECT  84.456 41.521 85.194 41.917 ;
     RECT  85.932 41.549 86.094 41.917 ;
     RECT  13.215 40.445 14.346 41.953 ;
     RECT  15.192 40.445 16.434 41.953 ;
     RECT  18.615 11.975 18.897 41.953 ;
     RECT  64.944 41.521 64.962 41.953 ;
     RECT  94.215 40.829 94.497 41.953 ;
     RECT  191.268 41.449 191.697 41.953 ;
     RECT  196.668 40.909 197.097 41.989 ;
     RECT  5.904 41.989 5.922 42.025 ;
     RECT  6.732 40.981 8.097 42.025 ;
     RECT  81.648 41.881 81.666 42.025 ;
     RECT  94.14 41.953 94.497 42.025 ;
     RECT  195.552 41.791 195.786 42.025 ;
     RECT  131.976 39.865 132.354 42.043 ;
     RECT  142.815 2.413 143.097 42.043 ;
     RECT  153.615 40.801 154.098 42.043 ;
     RECT  164.415 35.168 164.697 42.043 ;
     RECT  175.215 35.168 175.497 42.043 ;
     RECT  186.015 35.168 186.297 42.043 ;
     RECT  45.504 41.512 46.206 42.061 ;
     RECT  131.904 42.043 132.354 42.061 ;
     RECT  150.588 40.837 150.858 42.061 ;
     RECT  169.815 2.413 170.097 42.061 ;
     RECT  182.88 41.917 182.898 42.061 ;
     RECT  195.012 42.025 195.786 42.061 ;
     RECT  210.348 41.485 210.366 42.061 ;
     RECT  67.104 41.512 67.497 42.089 ;
     RECT  77.904 41.512 78.297 42.089 ;
     RECT  110.304 41.549 110.697 42.089 ;
     RECT  120.96 41.405 121.554 42.089 ;
     RECT  142.704 42.043 143.097 42.089 ;
     RECT  153.504 42.043 154.098 42.089 ;
     RECT  164.304 42.043 164.697 42.089 ;
     RECT  175.104 42.043 175.497 42.089 ;
     RECT  185.904 42.043 186.297 42.089 ;
     RECT  23.688 41.755 25.002 42.151 ;
     RECT  140.544 42.061 140.562 42.151 ;
     RECT  45.288 42.061 46.206 42.173 ;
     RECT  140.472 42.151 140.562 42.179 ;
     RECT  162.468 42.061 162.486 42.179 ;
     RECT  169.815 42.061 170.442 42.179 ;
     RECT  182.412 42.061 182.898 42.179 ;
     RECT  194.364 42.061 195.786 42.179 ;
     RECT  131.832 42.061 132.354 42.215 ;
     RECT  56.415 41.549 56.697 42.421 ;
     RECT  5.904 42.025 8.097 42.427 ;
     RECT  13.215 41.953 16.434 42.457 ;
     RECT  39.348 42.421 39.366 42.457 ;
     RECT  40.215 2.413 40.497 42.457 ;
     RECT  50.076 41.485 50.094 42.457 ;
     RECT  51.015 2.413 51.297 42.457 ;
     RECT  56.415 42.421 56.79 42.457 ;
     RECT  88.164 41.477 89.097 42.457 ;
     RECT  38.844 42.457 39.366 42.461 ;
     RECT  55.764 42.457 56.79 42.461 ;
     RECT  18.615 41.953 19.062 42.493 ;
     RECT  19.944 41.521 20.25 42.493 ;
     RECT  97.092 41.413 97.11 42.493 ;
     RECT  137.415 2.413 137.697 42.493 ;
     RECT  206.82 40.801 208.422 42.493 ;
     RECT  209.16 40.981 209.178 42.493 ;
     RECT  55.764 42.461 56.697 42.523 ;
     RECT  38.844 42.461 38.862 42.529 ;
     RECT  40.215 42.457 40.554 42.529 ;
     RECT  200.232 40.261 200.25 42.529 ;
     RECT  5.904 42.427 8.19 42.557 ;
     RECT  38.772 42.529 38.862 42.557 ;
     RECT  102.96 42.295 102.978 42.565 ;
     RECT  200.124 42.529 200.25 42.565 ;
     RECT  55.368 42.523 56.697 42.593 ;
     RECT  97.092 42.493 97.722 42.601 ;
     RECT  98.496 41.791 99.897 42.601 ;
     RECT  38.772 42.557 38.79 42.629 ;
     RECT  40.215 42.529 40.626 42.629 ;
     RECT  50.076 42.457 51.297 42.629 ;
     RECT  55.836 42.593 56.697 42.629 ;
     RECT  81.504 42.025 81.666 42.691 ;
     RECT  82.8 40.123 83.697 42.691 ;
     RECT  200.124 42.565 200.682 42.691 ;
     RECT  34.815 41.549 35.097 42.961 ;
     RECT  93.852 42.025 94.497 42.997 ;
     RECT  150.48 42.061 150.858 42.997 ;
     RECT  102.888 42.565 102.978 43.033 ;
     RECT  148.215 2.413 148.497 43.033 ;
     RECT  203.76 40.873 204.354 43.033 ;
     RECT  21.42 42.961 21.438 43.037 ;
     RECT  33.228 42.997 33.246 43.037 ;
     RECT  34.344 42.961 35.097 43.037 ;
     RECT  97.092 42.601 99.897 43.051 ;
     RECT  93.852 42.997 94.662 43.097 ;
     RECT  142.815 42.089 143.097 43.099 ;
     RECT  145.656 40.981 145.818 43.099 ;
     RECT  10.512 39.865 11.682 43.105 ;
     RECT  64.944 41.953 65.07 43.105 ;
     RECT  66.168 40.397 66.186 43.105 ;
     RECT  128.448 41.755 128.466 43.105 ;
     RECT  129.78 40.873 129.942 43.105 ;
     RECT  22.536 43.069 22.554 43.133 ;
     RECT  5.904 42.557 8.097 43.141 ;
     RECT  97.092 43.051 100.134 43.141 ;
     RECT  100.98 40.981 101.07 43.141 ;
     RECT  5.76 43.141 8.097 43.231 ;
     RECT  102.744 43.033 102.978 43.231 ;
     RECT  45.615 42.173 46.206 43.243 ;
     RECT  67.215 42.089 67.497 43.243 ;
     RECT  78.015 42.089 78.297 43.243 ;
     RECT  200.124 42.691 201.258 43.267 ;
     RECT  142.524 43.099 143.097 43.277 ;
     RECT  69.444 42.727 69.462 43.291 ;
     RECT  134.784 43.069 134.802 43.303 ;
     RECT  150.156 42.997 150.858 43.303 ;
     RECT  10.008 43.105 11.682 43.325 ;
     RECT  164.415 42.089 164.697 43.537 ;
     RECT  209.988 42.061 210.366 43.573 ;
     RECT  211.212 43.303 211.23 43.573 ;
     RECT  120.96 42.089 121.497 43.579 ;
     RECT  128.448 43.105 129.942 43.579 ;
     RECT  137.415 42.493 138.222 43.579 ;
     RECT  169.815 42.179 170.097 43.579 ;
     RECT  181.8 43.141 181.818 43.579 ;
     RECT  182.88 42.179 182.898 43.579 ;
     RECT  195.012 42.179 195.786 43.579 ;
     RECT  43.488 41.549 43.506 43.609 ;
     RECT  54.396 42.727 54.414 43.609 ;
     RECT  206.82 42.493 209.178 43.609 ;
     RECT  209.988 43.573 211.23 43.609 ;
     RECT  137.415 43.579 138.546 43.627 ;
     RECT  18.615 42.493 20.25 43.645 ;
     RECT  110.415 42.089 110.697 43.645 ;
     RECT  120.96 43.579 121.554 43.645 ;
     RECT  64.944 43.105 66.186 43.675 ;
     RECT  67.104 43.243 67.497 43.675 ;
     RECT  73.872 41.995 73.89 43.675 ;
     RECT  12.96 42.457 16.434 43.681 ;
     RECT  17.172 40.837 17.19 43.681 ;
     RECT  18.615 43.645 20.394 43.681 ;
     RECT  200.124 43.267 201.294 43.681 ;
     RECT  22.824 43.609 22.842 43.709 ;
     RECT  30.78 43.609 30.798 43.709 ;
     RECT  54.396 43.609 54.738 43.709 ;
     RECT  12.96 43.681 17.19 43.771 ;
     RECT  42.768 43.609 43.506 43.771 ;
     RECT  102.42 43.231 102.978 43.771 ;
     RECT  34.704 43.037 35.097 43.805 ;
     RECT  61.815 2.413 62.097 43.807 ;
     RECT  42.084 43.771 43.506 43.808 ;
     RECT  45.504 43.243 46.206 43.808 ;
     RECT  56.304 42.629 56.697 43.808 ;
     RECT  40.215 42.629 40.497 43.843 ;
     RECT  206.82 43.609 211.23 43.843 ;
     RECT  38.772 43.771 38.79 43.901 ;
     RECT  40.215 43.843 41.058 43.901 ;
     RECT  18.54 43.681 20.394 44.041 ;
     RECT  131.976 42.215 132.354 44.041 ;
     RECT  142.815 43.277 143.097 44.041 ;
     RECT  175.215 42.089 175.497 44.041 ;
     RECT  186.015 42.089 186.297 44.041 ;
     RECT  12.96 43.771 17.442 44.059 ;
     RECT  18.216 44.041 20.394 44.059 ;
     RECT  106.488 43.231 106.506 44.077 ;
     RECT  118.548 41.549 118.566 44.077 ;
     RECT  142.815 44.041 143.154 44.077 ;
     RECT  202.215 2.413 202.497 44.077 ;
     RECT  203.76 43.033 204.57 44.077 ;
     RECT  12.96 44.059 20.394 44.105 ;
     RECT  114.444 44.077 114.462 44.113 ;
     RECT  118.548 44.077 118.602 44.149 ;
     RECT  128.448 43.579 130.554 44.149 ;
     RECT  162.468 43.579 162.486 44.149 ;
     RECT  169.815 43.579 170.442 44.149 ;
     RECT  199.836 43.681 201.294 44.149 ;
     RECT  142.815 44.077 143.874 44.177 ;
     RECT  162.468 44.149 162.558 44.177 ;
     RECT  175.215 44.041 175.554 44.177 ;
     RECT  186.015 44.041 186.354 44.177 ;
     RECT  194.364 43.579 195.786 44.177 ;
     RECT  81.504 42.691 83.697 44.185 ;
     RECT  84.456 41.917 86.094 44.185 ;
     RECT  131.976 44.041 132.39 44.203 ;
     RECT  142.815 44.177 143.097 44.203 ;
     RECT  153.615 42.089 154.098 44.203 ;
     RECT  164.415 43.537 165.114 44.203 ;
     RECT  175.215 44.177 175.497 44.203 ;
     RECT  186.015 44.177 186.297 44.203 ;
     RECT  10.512 43.325 11.682 44.221 ;
     RECT  12.96 44.105 17.838 44.221 ;
     RECT  63.36 42.043 63.378 44.221 ;
     RECT  77.904 43.243 78.297 44.249 ;
     RECT  128.448 44.149 130.626 44.249 ;
     RECT  131.904 44.203 132.39 44.249 ;
     RECT  137.376 43.627 138.618 44.249 ;
     RECT  142.704 44.203 143.097 44.249 ;
     RECT  153.504 44.203 154.098 44.249 ;
     RECT  162.54 44.177 162.558 44.249 ;
     RECT  164.304 44.203 165.114 44.249 ;
     RECT  169.815 44.149 170.514 44.249 ;
     RECT  175.104 44.203 175.497 44.249 ;
     RECT  181.8 43.579 182.898 44.249 ;
     RECT  185.904 44.203 186.297 44.249 ;
     RECT  194.436 44.177 195.786 44.249 ;
     RECT  23.688 42.151 25.362 44.311 ;
     RECT  42.804 43.808 43.506 44.311 ;
     RECT  59.796 40.837 59.814 44.311 ;
     RECT  72.615 2.413 72.897 44.347 ;
     RECT  73.872 43.675 74.106 44.347 ;
     RECT  196.668 41.989 197.478 44.347 ;
     RECT  198.432 42.601 198.45 44.347 ;
     RECT  23.04 44.311 25.362 44.381 ;
     RECT  42.804 44.311 43.686 44.381 ;
     RECT  86.904 43.303 86.922 44.383 ;
     RECT  88.164 42.457 89.19 44.383 ;
     RECT  90.072 43.843 90.09 44.383 ;
     RECT  44.784 44.347 44.874 44.384 ;
     RECT  42.804 44.381 43.506 44.447 ;
     RECT  44.856 44.384 44.874 44.447 ;
     RECT  114.3 44.113 114.462 44.635 ;
     RECT  81.504 44.185 86.094 44.689 ;
     RECT  9.504 43.681 9.522 44.725 ;
     RECT  10.512 44.221 17.838 44.725 ;
     RECT  117.396 44.113 117.414 44.731 ;
     RECT  97.092 43.141 101.07 44.761 ;
     RECT  118.548 44.149 118.674 44.761 ;
     RECT  131.976 44.249 132.39 44.761 ;
     RECT  69.444 43.291 70.074 44.851 ;
     RECT  117.396 44.731 117.45 44.879 ;
     RECT  18.615 44.105 20.394 44.887 ;
     RECT  106.488 44.077 106.65 44.887 ;
     RECT  114.3 44.635 114.642 44.887 ;
     RECT  128.448 44.249 129.942 44.887 ;
     RECT  213.015 2.413 213.297 44.887 ;
     RECT  106.488 44.887 106.686 44.987 ;
     RECT  118.548 44.761 118.818 44.987 ;
     RECT  196.668 44.347 198.45 44.995 ;
     RECT  109.224 44.851 109.242 45.005 ;
     RECT  18.615 44.887 20.466 45.023 ;
     RECT  179.244 41.881 179.262 45.121 ;
     RECT  145.656 43.099 146.394 45.149 ;
     RECT  114.3 44.887 114.678 45.157 ;
     RECT  115.524 41.755 116.298 45.157 ;
     RECT  114.3 45.157 116.298 45.197 ;
     RECT  145.656 45.149 146.214 45.197 ;
     RECT  29.415 40.349 29.697 45.265 ;
     RECT  112.824 41.377 113.202 45.265 ;
     RECT  34.815 43.805 35.097 45.391 ;
     RECT  45.615 43.808 46.206 45.391 ;
     RECT  56.415 43.808 56.697 45.391 ;
     RECT  78.015 44.249 78.297 45.391 ;
     RECT  110.304 43.645 110.697 45.391 ;
     RECT  114.3 45.197 114.714 45.391 ;
     RECT  199.836 44.149 201.474 45.391 ;
     RECT  202.215 44.077 204.57 45.391 ;
     RECT  26.604 44.113 26.622 45.427 ;
     RECT  31.284 45.391 31.302 45.427 ;
     RECT  93.852 43.097 94.497 45.427 ;
     RECT  115.815 45.197 116.298 45.427 ;
     RECT  31.284 45.427 31.374 45.437 ;
     RECT  110.268 45.391 110.697 45.437 ;
     RECT  76.392 43.141 76.41 45.463 ;
     RECT  175.215 44.249 175.497 45.463 ;
     RECT  26.604 45.427 26.874 45.527 ;
     RECT  31.356 45.437 31.374 45.527 ;
     RECT  93.852 45.427 94.698 45.527 ;
     RECT  64.944 43.675 67.497 45.535 ;
     RECT  172.98 44.923 172.998 45.535 ;
     RECT  147.888 43.033 148.497 45.547 ;
     RECT  140.472 42.179 140.49 45.571 ;
     RECT  106.488 44.987 106.506 45.787 ;
     RECT  117.396 44.879 117.414 45.787 ;
     RECT  140.472 45.571 140.634 45.787 ;
     RECT  194.256 45.499 194.274 45.787 ;
     RECT  195.012 44.249 195.786 45.787 ;
     RECT  9.504 44.725 17.838 45.835 ;
     RECT  5.112 43.231 8.097 45.931 ;
     RECT  8.928 45.835 17.838 45.931 ;
     RECT  115.815 45.427 116.55 45.931 ;
     RECT  153.615 44.249 154.098 45.931 ;
     RECT  164.415 44.249 165.114 45.931 ;
     RECT  175.176 45.463 175.497 45.931 ;
     RECT  186.015 44.249 186.297 45.931 ;
     RECT  5.112 45.931 17.838 45.959 ;
     RECT  110.304 45.437 110.697 45.965 ;
     RECT  194.256 45.787 195.786 45.965 ;
     RECT  131.148 45.571 131.166 45.967 ;
     RECT  153.504 45.931 154.098 45.968 ;
     RECT  164.304 45.931 165.114 45.968 ;
     RECT  175.104 45.931 175.497 45.968 ;
     RECT  185.904 45.931 186.297 45.968 ;
     RECT  115.524 45.931 116.55 45.979 ;
     RECT  117.36 45.787 117.414 45.979 ;
     RECT  140.472 45.787 140.922 45.979 ;
     RECT  114.156 45.391 114.714 46.003 ;
     RECT  115.524 45.979 117.414 46.003 ;
     RECT  205.452 44.383 205.47 46.003 ;
     RECT  64.548 45.535 68.094 46.027 ;
     RECT  88.164 44.383 90.09 46.039 ;
     RECT  199.836 45.391 204.57 46.039 ;
     RECT  205.452 46.003 206.01 46.039 ;
     RECT  47.124 43.303 47.142 46.075 ;
     RECT  93.852 45.527 94.554 46.075 ;
     RECT  95.796 45.229 95.814 46.075 ;
     RECT  194.256 45.965 194.274 46.075 ;
     RECT  191.268 41.953 192.114 46.273 ;
     RECT  102.348 43.771 102.978 46.309 ;
     RECT  103.788 42.529 103.806 46.309 ;
     RECT  114.156 46.003 117.414 46.315 ;
     RECT  5.112 45.959 8.586 46.337 ;
     RECT  81.324 44.689 86.094 46.363 ;
     RECT  86.904 44.383 87.03 46.363 ;
     RECT  34.704 45.391 35.097 46.409 ;
     RECT  45.504 45.391 46.206 46.409 ;
     RECT  56.304 45.391 56.697 46.409 ;
     RECT  22.86 45.571 22.878 46.543 ;
     RECT  23.688 44.381 25.362 46.543 ;
     RECT  137.376 44.249 138.222 46.579 ;
     RECT  9.504 45.959 17.838 46.615 ;
     RECT  18.615 45.023 20.43 46.615 ;
     RECT  53.208 40.405 53.226 46.651 ;
     RECT  54.396 43.709 54.414 46.651 ;
     RECT  61.815 43.807 62.19 46.651 ;
     RECT  5.112 46.337 8.478 46.733 ;
     RECT  81.324 46.363 87.03 46.733 ;
     RECT  102.348 46.309 103.806 46.741 ;
     RECT  153.615 45.968 154.098 46.741 ;
     RECT  105.015 41.501 105.297 46.747 ;
     RECT  127.944 44.887 129.942 46.769 ;
     RECT  5.112 46.733 8.097 46.777 ;
     RECT  127.944 46.769 129.798 46.805 ;
     RECT  131.976 44.761 132.642 46.805 ;
     RECT  76.392 45.463 77.022 46.849 ;
     RECT  77.904 45.391 78.297 46.849 ;
     RECT  110.376 45.965 110.697 46.891 ;
     RECT  69.084 44.851 70.074 46.921 ;
     RECT  118.548 44.987 118.566 46.921 ;
     RECT  114.012 46.315 117.414 47.035 ;
     RECT  118.26 46.921 118.566 47.035 ;
     RECT  119.952 41.719 119.97 47.083 ;
     RECT  134.784 43.303 134.874 47.083 ;
     RECT  137.376 46.579 138.87 47.083 ;
     RECT  158.256 41.485 159.297 47.083 ;
     RECT  169.815 44.249 170.097 47.083 ;
     RECT  194.112 46.075 194.274 47.083 ;
     RECT  195.012 45.965 195.786 47.083 ;
     RECT  93.456 46.075 94.554 47.131 ;
     RECT  213.015 44.887 213.93 47.131 ;
     RECT  21.24 44.995 21.258 47.155 ;
     RECT  132.015 46.805 132.642 47.155 ;
     RECT  76.392 46.849 78.297 47.191 ;
     RECT  134.532 47.083 134.874 47.213 ;
     RECT  158.256 47.083 159.39 47.213 ;
     RECT  194.112 47.083 195.786 47.213 ;
     RECT  72.615 44.347 74.106 47.281 ;
     RECT  76.392 47.191 78.678 47.309 ;
     RECT  81.324 46.733 86.166 47.309 ;
     RECT  81.324 47.309 85.95 47.345 ;
     RECT  123.948 42.715 123.966 47.419 ;
     RECT  40.215 43.901 40.497 47.461 ;
     RECT  137.376 47.083 139.374 47.461 ;
     RECT  140.472 45.979 141.534 47.461 ;
     RECT  21.24 47.155 21.978 47.551 ;
     RECT  130.86 45.967 131.166 47.551 ;
     RECT  142.815 44.249 143.097 47.551 ;
     RECT  143.856 44.177 143.874 47.551 ;
     RECT  72.615 47.281 74.214 47.587 ;
     RECT  125.568 40.411 125.586 47.587 ;
     RECT  126.432 41.515 126.897 47.587 ;
     RECT  120.96 43.645 122.274 47.611 ;
     RECT  156.888 46.885 156.906 47.611 ;
     RECT  97.092 44.761 101.142 47.623 ;
     RECT  102.348 46.741 103.878 47.623 ;
     RECT  191.196 46.273 192.114 47.623 ;
     RECT  72.615 47.587 74.502 47.659 ;
     RECT  91.872 44.959 91.89 47.659 ;
     RECT  180.615 2.413 180.897 47.659 ;
     RECT  181.8 44.249 181.818 47.659 ;
     RECT  134.784 47.213 134.874 47.695 ;
     RECT  72.108 47.659 74.502 47.707 ;
     RECT  61.815 46.651 62.334 47.731 ;
     RECT  63.108 44.221 63.378 47.731 ;
     RECT  123.804 47.419 123.966 47.821 ;
     RECT  95.472 46.075 95.814 47.857 ;
     RECT  206.82 43.843 211.482 47.857 ;
     RECT  212.292 47.131 213.93 47.857 ;
     RECT  132.015 47.155 133.146 47.899 ;
     RECT  194.112 47.213 194.274 47.929 ;
     RECT  130.68 47.551 131.166 47.947 ;
     RECT  155.916 47.083 155.934 47.965 ;
     RECT  34.815 46.409 35.097 47.992 ;
     RECT  45.615 46.409 46.206 47.992 ;
     RECT  56.415 46.409 56.697 47.992 ;
     RECT  168.228 47.731 168.246 48.001 ;
     RECT  2.415 2.413 2.697 48.091 ;
     RECT  4.464 46.777 8.097 48.091 ;
     RECT  72.108 47.707 74.538 48.091 ;
     RECT  119.628 47.083 119.97 48.091 ;
     RECT  120.816 47.611 122.274 48.091 ;
     RECT  34.704 47.992 35.097 48.125 ;
     RECT  45.504 47.992 46.206 48.128 ;
     RECT  56.304 47.992 56.697 48.128 ;
     RECT  95.472 47.857 96.066 48.139 ;
     RECT  199.836 46.039 206.01 48.139 ;
     RECT  206.82 47.857 213.93 48.139 ;
     RECT  76.392 47.309 78.297 48.187 ;
     RECT  86.904 46.733 87.03 48.199 ;
     RECT  137.376 47.461 141.534 48.199 ;
     RECT  72.108 48.091 74.79 48.221 ;
     RECT  4.464 48.091 8.37 48.235 ;
     RECT  136.08 48.163 136.098 48.235 ;
     RECT  199.836 48.139 213.93 48.235 ;
     RECT  58.464 44.923 58.482 48.271 ;
     RECT  132.015 47.899 133.686 48.271 ;
     RECT  2.415 48.091 2.862 48.361 ;
     RECT  3.96 48.235 8.37 48.361 ;
     RECT  130.536 47.947 131.166 48.389 ;
     RECT  72.108 48.221 74.682 48.413 ;
     RECT  76.392 48.187 78.354 48.413 ;
     RECT  76.392 48.413 78.297 48.427 ;
     RECT  86.904 48.199 87.246 48.433 ;
     RECT  9.504 46.615 20.43 48.469 ;
     RECT  137.34 48.199 141.534 48.505 ;
     RECT  2.415 48.361 8.37 48.541 ;
     RECT  9.108 48.469 20.43 48.541 ;
     RECT  146.664 48.091 146.682 48.541 ;
     RECT  153.576 46.741 154.098 48.541 ;
     RECT  147.888 45.547 148.878 48.631 ;
     RECT  145.656 45.197 145.818 48.659 ;
     RECT  104.976 46.747 105.297 48.667 ;
     RECT  145.656 48.659 145.674 48.695 ;
     RECT  75.528 44.995 75.546 48.703 ;
     RECT  76.32 48.427 78.297 48.703 ;
     RECT  93.06 47.131 94.554 48.739 ;
     RECT  95.328 48.139 96.066 48.739 ;
     RECT  124.776 44.887 124.794 48.739 ;
     RECT  125.568 47.587 126.897 48.739 ;
     RECT  59.364 44.311 59.814 48.775 ;
     RECT  114.012 47.035 118.566 48.775 ;
     RECT  119.628 48.091 122.274 48.775 ;
     RECT  153.576 48.541 154.242 48.839 ;
     RECT  21.24 47.551 22.014 48.901 ;
     RECT  22.86 46.543 25.362 48.901 ;
     RECT  190.476 47.623 192.114 48.901 ;
     RECT  192.852 41.521 192.87 48.901 ;
     RECT  155.808 47.965 155.934 48.907 ;
     RECT  2.415 48.541 20.43 48.937 ;
     RECT  91.872 47.659 91.998 48.937 ;
     RECT  153.576 48.839 154.206 48.965 ;
     RECT  1.728 48.937 20.43 49.003 ;
     RECT  21.24 48.901 25.362 49.003 ;
     RECT  1.728 49.003 25.362 49.037 ;
     RECT  132.015 48.271 133.758 49.045 ;
     RECT  0.54 48.775 0.558 49.099 ;
     RECT  132.015 49.045 133.974 49.171 ;
     RECT  134.784 47.695 135.018 49.171 ;
     RECT  146.664 48.541 146.754 49.171 ;
     RECT  149.616 43.303 150.858 49.171 ;
     RECT  44.46 48.955 44.478 49.195 ;
     RECT  45.615 48.128 46.206 49.195 ;
     RECT  97.092 47.623 103.878 49.195 ;
     RECT  96.948 49.195 103.878 49.199 ;
     RECT  132.015 49.171 135.018 49.199 ;
     RECT  48.888 49.003 48.906 49.229 ;
     RECT  44.46 49.195 46.206 49.235 ;
     RECT  96.948 49.199 96.966 49.235 ;
     RECT  51.015 42.629 51.297 49.243 ;
     RECT  69.084 46.921 70.398 49.243 ;
     RECT  72.108 48.413 74.538 49.243 ;
     RECT  75.528 48.703 78.297 49.243 ;
     RECT  97.704 49.199 103.878 49.243 ;
     RECT  104.688 48.667 105.297 49.243 ;
     RECT  186.015 45.968 186.297 49.243 ;
     RECT  196.668 44.995 198.666 49.243 ;
     RECT  106.488 45.787 107.19 49.279 ;
     RECT  137.34 48.505 141.786 49.279 ;
     RECT  135.828 48.235 136.098 49.291 ;
     RECT  137.052 49.279 141.786 49.291 ;
     RECT  185.868 49.243 186.297 49.291 ;
     RECT  130.608 48.389 131.166 49.315 ;
     RECT  180.615 47.659 181.818 49.339 ;
     RECT  182.664 44.249 182.898 49.339 ;
     RECT  196.668 49.243 198.702 49.351 ;
     RECT  51.015 49.243 51.39 49.373 ;
     RECT  71.46 49.243 78.678 49.373 ;
     RECT  146.484 49.171 146.754 49.379 ;
     RECT  149.616 49.171 151.002 49.379 ;
     RECT  2.268 49.037 25.362 49.421 ;
     RECT  59.364 48.775 60.174 49.441 ;
     RECT  60.912 43.867 60.93 49.441 ;
     RECT  93.06 48.739 96.066 49.441 ;
     RECT  199.8 48.235 213.93 49.441 ;
     RECT  71.46 49.373 78.297 49.469 ;
     RECT  146.556 49.379 146.754 49.469 ;
     RECT  149.616 49.379 150.93 49.469 ;
     RECT  147.6 48.631 148.878 49.483 ;
     RECT  149.616 49.469 150.606 49.483 ;
     RECT  147.6 49.483 150.606 49.505 ;
     RECT  214.92 48.973 214.938 49.513 ;
     RECT  180.615 49.339 182.898 49.517 ;
     RECT  185.868 49.291 186.498 49.517 ;
     RECT  47.124 46.075 47.394 49.549 ;
     RECT  48.204 49.243 48.222 49.549 ;
     RECT  79.704 46.615 79.794 49.549 ;
     RECT  26.604 45.527 26.622 49.621 ;
     RECT  34.815 48.125 35.097 49.621 ;
     RECT  38.808 48.811 38.826 49.621 ;
     RECT  40.215 47.461 40.554 49.621 ;
     RECT  43.488 44.447 43.506 49.621 ;
     RECT  51.015 49.373 51.297 49.621 ;
     RECT  53.208 46.651 54.414 49.621 ;
     RECT  56.415 48.128 56.697 49.621 ;
     RECT  58.14 48.271 58.482 49.621 ;
     RECT  59.364 49.441 60.93 49.621 ;
     RECT  61.815 47.731 63.378 49.621 ;
     RECT  69.084 49.243 70.722 49.621 ;
     RECT  71.46 49.469 74.538 49.621 ;
     RECT  132.015 49.199 133.47 49.621 ;
     RECT  190.476 48.901 192.87 49.621 ;
     RECT  135.828 49.291 141.786 49.627 ;
     RECT  40.104 49.621 40.554 49.661 ;
     RECT  50.904 49.621 51.297 49.661 ;
     RECT  2.304 49.421 25.362 49.675 ;
     RECT  31.068 49.621 31.086 49.675 ;
     RECT  56.304 49.621 56.697 49.711 ;
     RECT  135.828 49.627 142.074 49.711 ;
     RECT  142.815 47.551 143.874 49.711 ;
     RECT  153.615 48.965 153.897 49.711 ;
     RECT  164.415 45.968 165.114 49.711 ;
     RECT  175.176 45.968 175.497 49.711 ;
     RECT  196.632 49.351 198.702 49.711 ;
     RECT  193.896 47.929 194.274 49.723 ;
     RECT  195.012 47.213 195.786 49.723 ;
     RECT  30.996 49.675 31.086 49.739 ;
     RECT  38.808 49.621 38.862 49.739 ;
     RECT  53.208 49.621 54.81 49.739 ;
     RECT  158.256 47.213 159.297 49.739 ;
     RECT  187.668 49.711 187.686 49.757 ;
     RECT  152.28 43.573 152.298 49.771 ;
     RECT  158.256 49.739 158.274 49.775 ;
     RECT  185.868 49.517 186.297 49.783 ;
     RECT  196.632 49.711 198.774 49.783 ;
     RECT  38.808 49.739 38.826 49.811 ;
     RECT  0.108 49.099 0.558 49.819 ;
     RECT  110.232 46.891 110.697 49.819 ;
     RECT  162.288 46.309 162.306 49.819 ;
     RECT  164.304 49.711 165.114 49.819 ;
     RECT  30.924 49.783 30.942 49.855 ;
     RECT  86.904 48.433 87.282 49.855 ;
     RECT  88.164 46.039 90.594 49.855 ;
     RECT  135.828 49.711 143.874 49.855 ;
     RECT  2.304 49.675 25.398 49.883 ;
     RECT  30.708 49.855 30.942 49.883 ;
     RECT  26.352 49.621 26.622 49.891 ;
     RECT  162.288 49.819 162.486 49.981 ;
     RECT  0.108 49.819 0.666 49.997 ;
     RECT  112.68 45.265 113.202 50.009 ;
     RECT  193.896 49.723 195.786 50.017 ;
     RECT  196.632 49.783 198.99 50.017 ;
     RECT  81.324 47.345 85.374 50.045 ;
     RECT  112.68 50.009 113.058 50.045 ;
     RECT  26.28 49.891 26.622 50.053 ;
     RECT  93.06 49.441 96.678 50.053 ;
     RECT  199.764 49.441 213.93 50.053 ;
     RECT  214.812 49.513 214.938 50.053 ;
     RECT  56.304 49.711 56.934 50.081 ;
     RECT  190.404 49.621 192.87 50.081 ;
     RECT  26.208 50.053 26.622 50.093 ;
     RECT  162.288 49.981 162.558 50.117 ;
     RECT  164.304 49.819 165.258 50.117 ;
     RECT  30.708 49.883 30.798 50.141 ;
     RECT  84.996 50.045 85.374 50.153 ;
     RECT  58.14 49.621 60.93 50.155 ;
     RECT  61.704 49.621 63.378 50.155 ;
     RECT  42.804 49.621 43.506 50.161 ;
     RECT  91.62 48.937 91.998 50.161 ;
     RECT  92.736 50.053 96.678 50.161 ;
     RECT  127.944 46.805 129.762 50.189 ;
     RECT  69.084 49.621 74.538 50.203 ;
     RECT  75.276 49.469 78.297 50.203 ;
     RECT  86.904 49.855 90.594 50.251 ;
     RECT  97.704 49.243 105.297 50.251 ;
     RECT  182.664 49.517 182.898 50.279 ;
     RECT  193.896 50.017 198.99 50.279 ;
     RECT  135.828 49.855 144.234 50.288 ;
     RECT  153.504 49.711 153.897 50.288 ;
     RECT  164.304 50.117 164.898 50.288 ;
     RECT  175.104 49.711 175.497 50.288 ;
     RECT  108 46.039 108.018 50.299 ;
     RECT  108.756 46.885 108.774 50.299 ;
     RECT  26.28 50.093 26.622 50.323 ;
     RECT  69.084 50.203 78.297 50.323 ;
     RECT  79.092 49.549 79.794 50.323 ;
     RECT  195.876 50.279 198.99 50.333 ;
     RECT  97.632 50.251 105.297 50.351 ;
     RECT  128.34 50.189 129.762 50.351 ;
     RECT  0.108 49.997 0.558 50.387 ;
     RECT  69.084 50.323 79.794 50.395 ;
     RECT  97.704 50.351 105.297 50.443 ;
     RECT  26.28 50.323 26.658 50.459 ;
     RECT  108 50.299 108.774 50.521 ;
     RECT  69.084 50.395 80.118 50.525 ;
     RECT  111.6 48.235 111.762 50.539 ;
     RECT  112.68 50.045 112.698 50.539 ;
     RECT  111.6 50.539 112.698 50.585 ;
     RECT  131.904 49.621 133.47 50.585 ;
     RECT  50.076 42.629 50.094 50.593 ;
     RECT  69.084 50.525 80.01 50.621 ;
     RECT  58.14 50.155 63.378 50.665 ;
     RECT  86.364 50.251 90.594 50.665 ;
     RECT  130.5 49.315 131.166 50.665 ;
     RECT  131.904 50.585 132.297 50.665 ;
     RECT  58.14 50.665 63.738 50.669 ;
     RECT  50.076 50.593 50.166 50.701 ;
     RECT  91.62 50.161 96.678 50.701 ;
     RECT  110.052 49.819 110.697 50.701 ;
     RECT  111.6 50.585 111.762 50.701 ;
     RECT  114.012 48.775 122.274 50.729 ;
     RECT  86.328 50.665 90.594 50.731 ;
     RECT  91.332 50.701 96.678 50.731 ;
     RECT  108 50.521 109.134 50.731 ;
     RECT  110.016 50.701 111.762 50.731 ;
     RECT  53.208 49.739 54.738 50.779 ;
     RECT  120.492 50.729 122.274 50.779 ;
     RECT  85.032 50.153 85.374 50.791 ;
     RECT  86.328 50.731 96.678 50.791 ;
     RECT  196.344 50.333 198.99 50.791 ;
     RECT  199.764 50.053 214.938 50.791 ;
     RECT  190.476 50.081 192.87 50.819 ;
     RECT  26.28 50.459 26.622 50.821 ;
     RECT  2.304 49.883 25.362 50.827 ;
     RECT  26.1 50.821 26.622 50.827 ;
     RECT  27.612 50.731 27.63 50.827 ;
     RECT  69.084 50.621 75.006 50.827 ;
     RECT  81.324 50.045 84.258 50.827 ;
     RECT  106.344 49.279 107.19 50.827 ;
     RECT  135.828 50.288 142.074 50.855 ;
     RECT  30.78 50.141 30.798 50.863 ;
     RECT  47.124 49.549 48.222 50.863 ;
     RECT  169.815 47.083 170.334 50.863 ;
     RECT  28.872 45.265 29.697 50.875 ;
     RECT  30.708 50.863 30.798 50.899 ;
     RECT  34.704 49.621 35.097 50.899 ;
     RECT  44.46 49.235 44.478 50.899 ;
     RECT  45.504 49.235 46.206 50.899 ;
     RECT  47.124 50.863 48.474 50.899 ;
     RECT  155.808 48.907 156.006 50.899 ;
     RECT  120.492 50.779 122.382 50.909 ;
     RECT  147.6 49.505 150.174 50.909 ;
     RECT  47.124 50.899 48.546 50.923 ;
     RECT  49.968 50.701 50.166 50.923 ;
     RECT  51.015 49.661 51.297 50.923 ;
     RECT  53.208 50.779 54.774 50.923 ;
     RECT  56.304 50.081 56.697 50.923 ;
     RECT  40.215 49.661 40.554 50.935 ;
     RECT  49.968 50.923 51.297 50.935 ;
     RECT  52.992 50.923 54.882 50.935 ;
     RECT  147.888 50.909 150.174 50.935 ;
     RECT  166.212 44.311 166.23 50.935 ;
     RECT  40.104 50.935 40.554 50.965 ;
     RECT  81.144 50.827 84.258 50.965 ;
     RECT  42.768 50.161 43.506 50.971 ;
     RECT  97.704 50.443 105.39 50.971 ;
     RECT  106.128 50.827 107.19 50.971 ;
     RECT  178.02 46.849 178.038 50.971 ;
     RECT  34.704 50.899 35.262 50.999 ;
     RECT  56.304 50.923 56.898 50.999 ;
     RECT  108 50.731 111.762 50.999 ;
     RECT  147.888 50.935 150.462 50.999 ;
     RECT  34.704 50.999 35.19 51.005 ;
     RECT  60.912 50.669 63.738 51.019 ;
     RECT  64.548 46.027 68.238 51.019 ;
     RECT  128.34 50.351 128.862 51.061 ;
     RECT  52.956 50.935 54.882 51.067 ;
     RECT  85.032 50.791 96.678 51.089 ;
     RECT  146.664 49.469 146.754 51.089 ;
     RECT  182.664 50.279 182.682 51.089 ;
     RECT  40.104 50.965 40.59 51.097 ;
     RECT  140.796 50.855 142.074 51.097 ;
     RECT  142.815 50.288 144.234 51.097 ;
     RECT  145.764 50.971 145.782 51.097 ;
     RECT  156.816 47.611 156.906 51.125 ;
     RECT  39.924 51.097 40.59 51.133 ;
     RECT  42.768 50.971 43.578 51.133 ;
     RECT  185.832 49.783 186.297 51.133 ;
     RECT  47.124 50.923 49.194 51.149 ;
     RECT  27.612 50.827 27.954 51.161 ;
     RECT  86.076 51.089 96.678 51.161 ;
     RECT  49.032 51.149 49.194 51.169 ;
     RECT  112.68 50.585 112.698 51.169 ;
     RECT  175.176 50.288 175.497 51.169 ;
     RECT  127.944 51.061 128.862 51.197 ;
     RECT  140.796 51.097 144.234 51.197 ;
     RECT  52.884 51.067 54.882 51.203 ;
     RECT  34.704 51.005 35.118 51.205 ;
     RECT  145.512 51.097 145.782 51.205 ;
     RECT  146.664 51.089 146.682 51.205 ;
     RECT  162.288 50.117 162.306 51.205 ;
     RECT  150.156 50.999 150.462 51.211 ;
     RECT  108.756 50.999 111.762 51.233 ;
     RECT  42.66 51.133 43.578 51.241 ;
     RECT  44.46 50.899 46.206 51.241 ;
     RECT  69.012 50.827 75.006 51.241 ;
     RECT  160.524 50.431 160.542 51.241 ;
     RECT  39.924 51.133 40.95 51.259 ;
     RECT  86.076 51.161 91.998 51.269 ;
     RECT  0.108 50.387 0.306 51.307 ;
     RECT  38.808 50.899 38.826 51.307 ;
     RECT  49.968 50.935 51.894 51.307 ;
     RECT  75.744 50.621 80.01 51.307 ;
     RECT  81.036 50.965 84.258 51.307 ;
     RECT  141.372 51.197 144.234 51.307 ;
     RECT  28.872 50.875 29.79 51.331 ;
     RECT  36.792 51.205 36.81 51.331 ;
     RECT  38.772 51.307 38.826 51.331 ;
     RECT  39.78 51.259 40.95 51.331 ;
     RECT  44.424 51.241 46.206 51.331 ;
     RECT  97.704 50.971 107.19 51.331 ;
     RECT  114.012 50.729 119.754 51.331 ;
     RECT  123.372 47.821 123.966 51.331 ;
     RECT  124.776 48.739 126.897 51.331 ;
     RECT  141.372 51.307 144.486 51.331 ;
     RECT  157.608 51.307 157.626 51.331 ;
     RECT  159.015 49.739 159.297 51.331 ;
     RECT  162.288 51.205 162.414 51.331 ;
     RECT  166.212 50.935 166.482 51.331 ;
     RECT  167.904 48.001 168.246 51.331 ;
     RECT  178.02 50.971 178.362 51.331 ;
     RECT  179.208 45.121 179.262 51.331 ;
     RECT  180.615 49.517 181.818 51.331 ;
     RECT  185.364 51.133 186.297 51.331 ;
     RECT  193.896 50.279 195.138 51.331 ;
     RECT  37.62 49.771 37.638 51.355 ;
     RECT  38.772 51.331 38.862 51.355 ;
     RECT  39.708 51.331 40.95 51.355 ;
     RECT  155.34 50.899 156.006 51.355 ;
     RECT  161.676 51.331 162.594 51.355 ;
     RECT  167.904 51.331 168.534 51.355 ;
     RECT  174.492 51.169 175.497 51.355 ;
     RECT  177.84 51.331 179.262 51.355 ;
     RECT  75.744 51.307 84.258 51.359 ;
     RECT  92.736 51.161 96.678 51.359 ;
     RECT  97.704 51.331 107.622 51.359 ;
     RECT  130.5 50.665 132.297 51.359 ;
     RECT  156.816 51.125 156.834 51.359 ;
     RECT  190.476 50.819 192.186 51.359 ;
     RECT  28.692 51.331 29.79 51.367 ;
     RECT  30.708 50.899 31.014 51.367 ;
     RECT  56.376 50.999 56.898 51.367 ;
     RECT  58.14 50.669 60.174 51.367 ;
     RECT  134.46 49.199 135.018 51.367 ;
     RECT  135.828 50.855 139.914 51.367 ;
     RECT  153.615 50.288 153.897 51.367 ;
     RECT  157.608 51.331 157.698 51.367 ;
     RECT  158.472 51.331 159.297 51.367 ;
     RECT  177.84 51.355 179.406 51.367 ;
     RECT  180.615 51.331 181.89 51.367 ;
     RECT  185.328 51.331 186.297 51.367 ;
     RECT  188.856 49.549 188.874 51.367 ;
     RECT  2.304 50.827 26.622 51.395 ;
     RECT  47.124 51.149 48.258 51.395 ;
     RECT  68.976 51.241 75.006 51.395 ;
     RECT  75.744 51.359 79.902 51.395 ;
     RECT  93.456 51.359 96.678 51.395 ;
     RECT  102.42 51.359 107.622 51.395 ;
     RECT  108.936 51.233 111.762 51.395 ;
     RECT  112.68 51.169 112.77 51.395 ;
     RECT  113.94 51.331 119.754 51.395 ;
     RECT  123.372 51.331 126.897 51.395 ;
     RECT  130.5 51.359 130.986 51.395 ;
     RECT  157.608 51.367 159.297 51.395 ;
     RECT  160.524 51.241 160.758 51.395 ;
     RECT  167.832 51.355 168.534 51.395 ;
     RECT  37.62 51.355 38.862 51.403 ;
     RECT  39.6 51.355 40.95 51.403 ;
     RECT  49.968 51.307 52.038 51.403 ;
     RECT  56.376 51.367 60.174 51.403 ;
     RECT  60.912 51.019 68.238 51.403 ;
     RECT  113.94 51.395 116.55 51.403 ;
     RECT  127.944 51.197 128.61 51.403 ;
     RECT  155.052 51.355 156.006 51.403 ;
     RECT  185.328 51.367 186.786 51.403 ;
     RECT  147.888 50.999 149.058 51.431 ;
     RECT  0.108 51.307 0.342 51.437 ;
     RECT  37.62 51.403 40.95 51.437 ;
     RECT  129.744 50.351 129.762 51.439 ;
     RECT  161.676 51.355 162.63 51.439 ;
     RECT  166.212 51.331 166.59 51.439 ;
     RECT  185.328 51.403 186.966 51.439 ;
     RECT  33.192 51.367 33.21 51.451 ;
     RECT  34.092 51.205 35.118 51.451 ;
     RECT  153.252 51.367 153.897 51.451 ;
     RECT  155.052 51.403 156.762 51.451 ;
     RECT  157.68 51.395 159.297 51.451 ;
     RECT  164.415 50.288 164.898 51.451 ;
     RECT  166.212 51.439 167.238 51.451 ;
     RECT  47.448 51.395 48.258 51.467 ;
     RECT  53.208 51.203 54.882 51.467 ;
     RECT  102.6 51.395 107.622 51.467 ;
     RECT  117.396 51.395 119.754 51.467 ;
     RECT  123.372 51.395 124.29 51.467 ;
     RECT  126.252 51.395 126.897 51.467 ;
     RECT  141.372 51.331 144.738 51.467 ;
     RECT  157.68 51.451 159.354 51.467 ;
     RECT  168.336 51.395 168.534 51.475 ;
     RECT  68.976 51.395 73.818 51.485 ;
     RECT  164.304 51.451 164.898 51.499 ;
     RECT  33.192 51.451 35.118 51.503 ;
     RECT  44.424 51.331 46.35 51.503 ;
     RECT  56.376 51.403 68.238 51.503 ;
     RECT  68.976 51.485 73.71 51.503 ;
     RECT  118.188 51.467 119.754 51.503 ;
     RECT  141.372 51.467 144.306 51.503 ;
     RECT  157.932 51.467 159.354 51.503 ;
     RECT  160.56 51.395 160.758 51.503 ;
     RECT  26.604 51.395 26.622 51.511 ;
     RECT  27.684 51.161 27.954 51.511 ;
     RECT  28.692 51.367 31.014 51.511 ;
     RECT  33.192 51.503 33.21 51.511 ;
     RECT  36.396 51.331 36.81 51.511 ;
     RECT  74.664 51.395 75.006 51.511 ;
     RECT  75.744 51.395 79.686 51.511 ;
     RECT  120.564 50.909 122.382 51.511 ;
     RECT  161.676 51.439 162.666 51.511 ;
     RECT  172.98 45.535 173.646 51.511 ;
     RECT  174.492 51.355 175.554 51.511 ;
     RECT  188.712 51.367 188.874 51.511 ;
     RECT  190.44 51.403 190.458 51.511 ;
     RECT  134.46 51.367 139.914 51.533 ;
     RECT  33.12 51.511 33.21 51.539 ;
     RECT  35.928 51.511 36.81 51.539 ;
     RECT  48.06 51.467 48.258 51.539 ;
     RECT  66.636 51.503 68.238 51.539 ;
     RECT  74.664 51.511 79.686 51.539 ;
     RECT  80.856 51.359 84.258 51.539 ;
     RECT  95.868 51.395 96.678 51.539 ;
     RECT  118.476 51.503 119.754 51.539 ;
     RECT  166.068 51.451 167.238 51.539 ;
     RECT  180.615 51.367 182.178 51.539 ;
     RECT  49.968 51.403 52.434 51.581 ;
     RECT  103.356 51.467 107.622 51.587 ;
     RECT  126.615 51.467 126.897 51.587 ;
     RECT  131.904 51.359 132.297 51.587 ;
     RECT  38.196 51.437 40.95 51.592 ;
     RECT  172.188 51.331 172.206 51.592 ;
     RECT  188.64 51.511 188.982 51.592 ;
     RECT  153.252 51.451 156.762 51.595 ;
     RECT  188.64 51.592 189.09 51.595 ;
     RECT  27.684 51.511 31.014 51.601 ;
     RECT  38.196 51.592 41.454 51.601 ;
     RECT  42.192 51.241 43.578 51.601 ;
     RECT  44.424 51.503 46.278 51.601 ;
     RECT  129.672 51.439 129.762 51.601 ;
     RECT  130.5 51.395 130.878 51.601 ;
     RECT  169.815 50.863 171.018 51.601 ;
     RECT  174.492 51.511 175.59 51.601 ;
     RECT  177.84 51.367 179.478 51.628 ;
     RECT  2.304 51.395 25.794 51.629 ;
     RECT  26.604 51.511 26.694 51.629 ;
     RECT  27.684 51.601 31.122 51.629 ;
     RECT  38.196 51.601 46.278 51.629 ;
     RECT  48.168 51.539 48.258 51.629 ;
     RECT  49.968 51.581 50.058 51.629 ;
     RECT  50.796 51.581 52.434 51.629 ;
     RECT  53.208 51.467 53.298 51.629 ;
     RECT  68.976 51.503 73.638 51.629 ;
     RECT  77.904 51.539 79.686 51.629 ;
     RECT  80.856 51.539 81.954 51.629 ;
     RECT  82.728 51.539 84.258 51.629 ;
     RECT  85.032 51.089 85.302 51.629 ;
     RECT  86.256 51.269 91.998 51.629 ;
     RECT  96.12 51.539 96.678 51.629 ;
     RECT  97.704 51.359 101.574 51.629 ;
     RECT  108.936 51.395 111.114 51.629 ;
     RECT  123.444 51.467 124.29 51.629 ;
     RECT  125.316 51.395 125.406 51.629 ;
     RECT  127.656 51.403 128.61 51.629 ;
     RECT  129.672 51.601 130.878 51.629 ;
     RECT  134.712 51.533 139.914 51.629 ;
     RECT  152.136 49.771 152.298 51.629 ;
     RECT  164.16 51.499 164.898 51.629 ;
     RECT  172.116 51.592 172.206 51.629 ;
     RECT  182.052 51.539 182.142 51.629 ;
     RECT  188.568 51.595 189.09 51.635 ;
     RECT  26.676 51.629 26.694 51.637 ;
     RECT  120.564 51.511 122.562 51.637 ;
     RECT  150.156 51.211 151.11 51.637 ;
     RECT  152.136 51.629 152.154 51.637 ;
     RECT  185.256 51.439 186.966 51.637 ;
     RECT  35.928 51.539 36.738 51.665 ;
     RECT  41.76 51.629 46.278 51.665 ;
     RECT  50.04 51.629 50.058 51.665 ;
     RECT  54.18 51.467 54.882 51.665 ;
     RECT  56.376 51.503 65.79 51.665 ;
     RECT  85.032 51.629 85.194 51.665 ;
     RECT  86.256 51.629 91.494 51.665 ;
     RECT  93.456 51.395 94.662 51.665 ;
     RECT  105.984 51.587 107.622 51.665 ;
     RECT  112.932 51.403 116.55 51.665 ;
     RECT  118.548 51.539 119.754 51.665 ;
     RECT  120.564 51.637 122.634 51.665 ;
     RECT  127.656 51.629 128.358 51.665 ;
     RECT  133.128 50.585 133.47 51.665 ;
     RECT  135.684 51.629 135.846 51.665 ;
     RECT  136.8 51.629 139.914 51.665 ;
     RECT  148.104 51.431 149.058 51.665 ;
     RECT  150.156 51.637 152.154 51.665 ;
     RECT  153.18 51.595 156.762 51.665 ;
     RECT  158.004 51.503 159.354 51.665 ;
     RECT  164.16 51.629 164.79 51.665 ;
     RECT  166.068 51.539 167.166 51.665 ;
     RECT  27.828 51.629 31.122 51.673 ;
     RECT  33.12 51.539 33.174 51.673 ;
     RECT  66.744 51.539 68.238 51.673 ;
     RECT  68.976 51.629 71.478 51.673 ;
     RECT  129.672 51.629 130.734 51.673 ;
     RECT  33.984 51.503 35.118 51.677 ;
     RECT  38.196 51.629 41.022 51.677 ;
     RECT  81.936 51.629 81.954 51.677 ;
     RECT  112.932 51.665 116.226 51.677 ;
     RECT  129.456 51.673 130.734 51.677 ;
     RECT  27.828 51.673 31.338 51.688 ;
     RECT  26.676 51.637 26.73 51.701 ;
     RECT  27.828 51.688 29.898 51.701 ;
     RECT  33.048 51.673 33.174 51.701 ;
     RECT  35.928 51.665 36.558 51.701 ;
     RECT  38.772 51.677 38.97 51.701 ;
     RECT  41.76 51.665 44.478 51.701 ;
     RECT  58.464 51.665 65.79 51.701 ;
     RECT  85.14 51.665 85.194 51.701 ;
     RECT  88.704 51.665 91.494 51.701 ;
     RECT  108.936 51.629 110.97 51.701 ;
     RECT  114.192 51.677 116.226 51.701 ;
     RECT  172.98 51.511 173.754 51.701 ;
     RECT  174.492 51.601 175.878 51.701 ;
     RECT  118.584 51.665 119.754 51.709 ;
     RECT  120.564 51.665 121.734 51.709 ;
     RECT  158.904 51.665 159.354 51.709 ;
     RECT  41.76 51.701 43.326 51.725 ;
     RECT  82.728 51.629 83.898 51.725 ;
     RECT  188.64 51.635 189.09 51.736 ;
     RECT  58.536 51.701 65.79 51.737 ;
     RECT  85.176 51.701 85.194 51.737 ;
     RECT  96.12 51.629 96.426 51.737 ;
     RECT  97.704 51.629 100.062 51.737 ;
     RECT  101.088 51.629 101.574 51.737 ;
     RECT  103.356 51.587 105.21 51.737 ;
     RECT  114.516 51.701 116.226 51.737 ;
     RECT  118.584 51.709 121.734 51.737 ;
     RECT  122.544 51.665 122.634 51.737 ;
     RECT  125.316 51.629 125.334 51.737 ;
     RECT  134.712 51.629 134.91 51.737 ;
     RECT  141.372 51.503 144.054 51.737 ;
     RECT  145.512 51.205 146.682 51.737 ;
     RECT  161.64 51.511 162.666 51.737 ;
     RECT  164.304 51.665 164.79 51.737 ;
     RECT  168.336 51.475 168.57 51.737 ;
     RECT  171.936 51.637 171.954 51.737 ;
     RECT  172.98 51.701 172.998 51.737 ;
     RECT  34.164 51.677 35.118 51.739 ;
     RECT  35.928 51.701 36.486 51.739 ;
     RECT  88.704 51.701 90.054 51.746 ;
     RECT  0.108 51.437 0.162 51.773 ;
     RECT  27.828 51.701 28.422 51.773 ;
     RECT  29.415 51.701 29.898 51.773 ;
     RECT  30.78 51.688 31.338 51.773 ;
     RECT  33.048 51.701 33.066 51.773 ;
     RECT  34.164 51.739 36.486 51.773 ;
     RECT  40.032 51.677 41.022 51.773 ;
     RECT  54.252 51.665 54.882 51.773 ;
     RECT  56.376 51.665 57.294 51.773 ;
     RECT  58.536 51.737 63.342 51.773 ;
     RECT  64.548 51.737 65.79 51.773 ;
     RECT  66.744 51.673 71.478 51.773 ;
     RECT  98.568 51.737 100.062 51.773 ;
     RECT  136.872 51.665 137.754 51.773 ;
     RECT  138.528 51.665 139.374 51.773 ;
     RECT  146.484 51.737 146.682 51.773 ;
     RECT  162.468 51.737 162.666 51.773 ;
     RECT  164.304 51.737 164.718 51.773 ;
     RECT  188.64 51.736 189.63 51.773 ;
     RECT  60.048 51.773 62.874 51.779 ;
     RECT  56.376 51.773 57.222 51.781 ;
     RECT  107.424 51.665 107.622 51.781 ;
     RECT  133.308 51.665 133.47 51.781 ;
     RECT  173.736 51.701 173.754 51.781 ;
     RECT  174.492 51.701 175.734 51.781 ;
     RECT  180.615 51.539 181.278 51.781 ;
     RECT  190.404 51.511 190.458 51.781 ;
     RECT  48.24 51.629 48.258 51.809 ;
     RECT  50.904 51.629 52.434 51.809 ;
     RECT  60.048 51.779 62.01 51.809 ;
     RECT  107.424 51.781 108.198 51.809 ;
     RECT  108.936 51.701 110.898 51.809 ;
     RECT  118.584 51.737 121.482 51.809 ;
     RECT  123.444 51.629 124.218 51.809 ;
     RECT  129.456 51.677 130.626 51.809 ;
     RECT  136.872 51.773 137.682 51.809 ;
     RECT  146.52 51.773 146.682 51.809 ;
     RECT  150.408 51.665 151.686 51.809 ;
     RECT  153.252 51.665 155.178 51.809 ;
     RECT  158.904 51.709 159.39 51.809 ;
     RECT  162.576 51.773 162.666 51.809 ;
     RECT  166.14 51.665 167.166 51.809 ;
     RECT  177.84 51.628 179.514 51.809 ;
     RECT  185.256 51.637 187.002 51.809 ;
     RECT  188.64 51.773 189.054 51.809 ;
     RECT  50.904 51.809 51.894 51.821 ;
     RECT  81.18 51.629 81.198 51.821 ;
     RECT  102.6 51.467 102.618 51.821 ;
     RECT  105.015 51.737 105.21 51.821 ;
     RECT  114.516 51.737 116.01 51.821 ;
     RECT  118.584 51.809 119.682 51.821 ;
     RECT  122.58 51.737 122.598 51.821 ;
     RECT  126.615 51.587 126.81 51.821 ;
     RECT  131.904 51.587 132.21 51.821 ;
     RECT  137.304 51.809 137.682 51.821 ;
     RECT  148.104 51.665 148.698 51.821 ;
     RECT  153.432 51.809 155.178 51.821 ;
     RECT  158.904 51.809 159.282 51.821 ;
     RECT  164.304 51.773 164.61 51.821 ;
     RECT  180.504 51.781 181.278 51.821 ;
     RECT  185.256 51.809 186.21 51.821 ;
     RECT  191.304 51.359 192.114 51.821 ;
     RECT  29.415 51.773 29.79 51.857 ;
     RECT  51.015 51.821 51.894 51.857 ;
     RECT  72.615 51.629 73.638 51.857 ;
     RECT  94.215 51.665 94.662 51.857 ;
     RECT  105.015 51.821 105.105 51.857 ;
     RECT  114.516 51.821 115.905 51.857 ;
     RECT  126.615 51.821 126.705 51.857 ;
     RECT  132.015 51.821 132.105 51.857 ;
     RECT  137.415 51.821 137.61 51.857 ;
     RECT  148.215 51.821 148.698 51.857 ;
     RECT  159.015 51.821 159.21 51.857 ;
     RECT  164.415 51.821 164.61 51.857 ;
     RECT  169.815 51.601 171.054 51.857 ;
     RECT  180.615 51.821 181.278 51.857 ;
     RECT  185.256 51.821 186.105 51.857 ;
     RECT  191.415 51.821 192.114 51.857 ;
     RECT  2.304 51.629 25.65 51.869 ;
     RECT  29.628 51.857 29.79 51.869 ;
     RECT  30.888 51.773 31.338 51.869 ;
     RECT  38.808 51.701 38.97 51.869 ;
     RECT  51.3 51.857 51.894 51.869 ;
     RECT  60.336 51.809 62.01 51.869 ;
     RECT  62.784 51.779 62.874 51.869 ;
     RECT  72.792 51.857 73.638 51.869 ;
     RECT  77.904 51.629 78.858 51.869 ;
     RECT  82.944 51.725 83.61 51.869 ;
     RECT  86.256 51.665 87.786 51.869 ;
     RECT  114.516 51.857 115.686 51.869 ;
     RECT  134.712 51.737 134.73 51.869 ;
     RECT  137.592 51.857 137.61 51.869 ;
     RECT  138.636 51.773 138.654 51.869 ;
     RECT  146.52 51.809 146.61 51.869 ;
     RECT  153.432 51.821 153.81 51.869 ;
     RECT  154.584 51.821 155.178 51.869 ;
     RECT  159.192 51.857 159.21 51.869 ;
     RECT  162.612 51.809 162.63 51.869 ;
     RECT  164.592 51.857 164.61 51.869 ;
     RECT  169.992 51.857 171.054 51.869 ;
     RECT  173.736 51.781 175.734 51.869 ;
     RECT  178.884 51.809 179.154 51.869 ;
     RECT  54.72 51.773 54.882 51.883 ;
     RECT  38.808 51.869 38.934 51.899 ;
     RECT  40.032 51.773 40.77 51.899 ;
     RECT  66.744 51.773 71.262 51.899 ;
     RECT  141.372 51.737 141.39 51.899 ;
     RECT  148.356 51.857 148.698 51.899 ;
     RECT  186.948 51.809 187.002 51.899 ;
     RECT  2.304 51.869 24.714 51.917 ;
     RECT  34.668 51.773 36.486 51.917 ;
     RECT  34.704 51.917 36.486 51.935 ;
     RECT  64.548 51.773 64.998 51.935 ;
     RECT  74.664 51.539 77.166 51.935 ;
     RECT  77.904 51.869 78.786 51.935 ;
     RECT  88.704 51.746 90.018 51.935 ;
     RECT  142.308 51.737 144.054 51.935 ;
     RECT  166.5 51.809 167.166 51.935 ;
     RECT  120.564 51.809 121.482 51.965 ;
     RECT  193.248 51.331 195.138 51.965 ;
     RECT  40.752 51.899 40.77 51.971 ;
     RECT  45.36 51.665 45.99 51.971 ;
     RECT  60.336 51.869 61.758 51.971 ;
     RECT  108.936 51.809 108.954 51.971 ;
     RECT  110.016 51.809 110.898 51.971 ;
     RECT  148.356 51.899 148.374 51.971 ;
     RECT  55.872 51.781 57.222 52.007 ;
     RECT  98.568 51.773 99.882 52.007 ;
     RECT  118.62 51.821 119.682 52.007 ;
     RECT  120.852 51.965 121.482 52.007 ;
     RECT  54.72 51.883 54.954 52.013 ;
     RECT  55.872 52.007 56.718 52.013 ;
     RECT  62.784 51.869 62.802 52.013 ;
     RECT  110.592 51.971 110.898 52.013 ;
     RECT  133.308 51.781 133.974 52.013 ;
     RECT  64.8 51.935 64.998 52.043 ;
     RECT  88.74 51.935 90.018 52.043 ;
     RECT  26.712 51.701 26.73 52.061 ;
     RECT  75.204 51.935 77.166 52.061 ;
     RECT  189.828 51.781 190.458 52.079 ;
     RECT  42.192 51.725 43.326 52.109 ;
     RECT  45.576 51.971 45.918 52.109 ;
     RECT  54.72 52.013 54.738 52.109 ;
     RECT  56.7 52.013 56.718 52.109 ;
     RECT  58.716 51.773 59.238 52.109 ;
     RECT  193.824 51.965 195.138 52.109 ;
     RECT  89.064 52.043 90.018 52.124 ;
     RECT  160.56 51.503 160.722 52.157 ;
     RECT  181.26 51.857 181.278 52.157 ;
     RECT  194.364 52.109 195.138 52.157 ;
     RECT  105.984 51.665 106.686 52.169 ;
     RECT  111.852 51.475 111.87 52.169 ;
     RECT  44.352 51.701 44.442 52.205 ;
     RECT  66.744 51.899 71.082 52.205 ;
     RECT  76.392 52.061 77.166 52.205 ;
     RECT  114.516 51.869 114.894 52.205 ;
     RECT  73.08 51.869 73.638 52.241 ;
     RECT  150.408 51.809 151.614 52.241 ;
     RECT  44.352 52.205 44.37 52.253 ;
     RECT  66.744 52.205 69.534 52.253 ;
     RECT  60.336 51.971 60.858 52.277 ;
     RECT  146.52 51.869 146.538 52.277 ;
     RECT  70.344 52.205 71.082 52.313 ;
     RECT  167.04 51.935 167.166 52.313 ;
     RECT  34.704 51.935 34.722 52.349 ;
     RECT  67.536 52.253 69.534 52.349 ;
     RECT  114.876 52.205 114.894 52.349 ;
     RECT  120.852 52.007 120.87 52.349 ;
     RECT  2.304 51.917 23.85 52.363 ;
     RECT  29.628 51.869 29.646 52.394 ;
     RECT  191.808 51.857 192.114 52.394 ;
     RECT  43.308 52.109 43.326 52.397 ;
     RECT  186.984 51.899 187.002 52.397 ;
     RECT  27.828 51.773 27.846 52.439 ;
     RECT  107.424 51.809 107.442 52.439 ;
     RECT  86.256 51.869 87.246 52.445 ;
     RECT  194.364 52.157 194.49 52.445 ;
     RECT  0.144 51.773 0.162 52.459 ;
     RECT  1.152 51.595 1.17 52.459 ;
     RECT  31.104 51.869 31.338 52.475 ;
     RECT  82.944 51.869 83.214 52.475 ;
     RECT  194.364 52.445 194.382 52.493 ;
     RECT  60.336 52.277 60.354 52.511 ;
     RECT  133.308 52.013 133.362 52.511 ;
     RECT  135.684 51.665 135.702 52.511 ;
     RECT  96.408 51.737 96.426 52.541 ;
     RECT  0.144 52.459 1.17 52.547 ;
     RECT  82.944 52.475 82.962 52.547 ;
     RECT  143.568 51.935 144.054 52.547 ;
     RECT  156.204 51.665 156.762 52.547 ;
     RECT  0.144 52.547 0.558 52.555 ;
     RECT  90.828 51.701 91.494 52.583 ;
     RECT  150.804 52.241 151.614 52.583 ;
     RECT  185.256 51.857 185.382 52.583 ;
     RECT  143.568 52.547 143.586 52.589 ;
     RECT  196.344 50.791 214.938 52.589 ;
     RECT  35.928 51.935 36.486 52.619 ;
     RECT  69.516 52.349 69.534 52.619 ;
     RECT  127.656 51.665 127.674 52.619 ;
     RECT  185.256 52.583 185.346 52.619 ;
     RECT  191.808 52.394 191.826 52.637 ;
     RECT  87.228 52.445 87.246 52.664 ;
     RECT  129.456 51.809 130.59 52.664 ;
     RECT  177.84 51.809 177.858 52.685 ;
     RECT  75.204 52.061 75.222 52.709 ;
     RECT  117.396 51.467 117.414 52.709 ;
     RECT  89.46 52.124 90.018 52.733 ;
     RECT  112.932 51.677 113.418 52.745 ;
     RECT  142.308 51.935 142.578 52.745 ;
     RECT  106.668 52.169 106.686 52.781 ;
     RECT  133.344 52.511 133.362 52.781 ;
     RECT  150.804 52.583 150.822 52.781 ;
     RECT  103.968 51.737 104.058 52.817 ;
     RECT  151.596 52.583 151.614 52.817 ;
     RECT  161.64 51.737 161.658 52.825 ;
     RECT  119.268 52.007 119.682 52.829 ;
     RECT  129.456 52.664 129.942 52.829 ;
     RECT  59.22 52.109 59.238 52.843 ;
     RECT  90 52.733 90.018 52.853 ;
     RECT  113.4 52.745 113.418 52.853 ;
     RECT  175.572 51.869 175.734 52.853 ;
     RECT  217.98 52.789 217.998 52.861 ;
     RECT  78.48 51.935 78.786 52.889 ;
     RECT  160.704 52.157 160.722 52.889 ;
     RECT  104.04 52.817 104.058 52.925 ;
     RECT  115.668 51.869 115.686 52.925 ;
     RECT  45.576 52.109 45.594 52.934 ;
     RECT  31.32 52.475 31.338 52.973 ;
     RECT  124.056 51.809 124.218 52.973 ;
     RECT  67.536 52.349 68.31 52.979 ;
     RECT  216.216 50.125 216.234 52.987 ;
     RECT  188.64 51.809 188.658 53.015 ;
     RECT  25.632 51.869 25.65 53.021 ;
     RECT  108.18 51.809 108.198 53.021 ;
     RECT  101.556 51.737 101.574 53.023 ;
     RECT  97.272 51.745 97.29 53.035 ;
     RECT  78.768 52.889 78.786 53.051 ;
     RECT  98.604 52.007 99.306 53.051 ;
     RECT  196.344 52.589 196.362 53.051 ;
     RECT  58.716 52.843 59.238 53.087 ;
     RECT  161.64 52.825 161.91 53.087 ;
     RECT  101.484 53.023 101.574 53.117 ;
     RECT  32.976 51.781 32.994 53.123 ;
     RECT  73.188 52.241 73.638 53.123 ;
     RECT  175.572 52.853 175.59 53.123 ;
     RECT  35.928 52.619 35.946 53.159 ;
     RECT  167.04 52.313 167.058 53.159 ;
     RECT  173.736 51.869 174.798 53.159 ;
     RECT  97.272 53.035 97.47 53.165 ;
     RECT  86.256 52.445 86.274 53.204 ;
     RECT  145.512 51.737 145.53 53.204 ;
     RECT  110.88 52.013 110.898 53.213 ;
     RECT  171.036 51.869 171.054 53.213 ;
     RECT  98.964 53.051 99.306 53.221 ;
     RECT  65.772 51.773 65.79 53.249 ;
     RECT  182.052 51.629 182.07 53.249 ;
     RECT  2.268 52.363 23.85 53.285 ;
     RECT  217.98 52.861 218.034 53.329 ;
     RECT  0.108 52.555 0.558 53.357 ;
     RECT  219.456 52.951 219.474 53.365 ;
     RECT  217.8 53.329 218.034 53.401 ;
     RECT  216.216 52.987 216.81 53.491 ;
     RECT  217.8 53.401 218.286 53.491 ;
     RECT  24.696 51.917 24.714 53.716 ;
     RECT  197.244 52.589 214.938 53.905 ;
     RECT  216.216 53.491 218.286 53.905 ;
     RECT  219.456 53.365 219.51 53.905 ;
     RECT  220.248 53.833 220.266 53.905 ;
     RECT  197.244 53.905 218.286 53.941 ;
     RECT  2.304 53.285 23.85 54 ;
     RECT  24.696 53.716 24.786 54 ;
     RECT  42.192 52.109 42.21 54 ;
     RECT  49.032 51.169 49.23 54 ;
     RECT  51.876 51.869 51.894 54 ;
     RECT  55.872 52.013 55.89 54 ;
     RECT  59.22 53.087 59.238 54 ;
     RECT  61.74 51.971 61.758 54 ;
     RECT  64.8 52.043 64.818 54 ;
     RECT  66.744 52.253 66.762 54 ;
     RECT  67.968 52.979 68.31 54 ;
     RECT  71.064 52.313 71.082 54 ;
     RECT  73.188 53.123 73.206 54 ;
     RECT  76.392 52.205 76.986 54 ;
     RECT  91.476 52.583 91.494 54 ;
     RECT  94.644 51.857 94.662 54 ;
     RECT  97.452 53.165 97.47 54 ;
     RECT  98.964 53.221 99.414 54 ;
     RECT  101.556 53.117 101.574 54 ;
     RECT  119.664 52.829 119.682 54 ;
     RECT  124.056 52.973 124.074 54 ;
     RECT  129.456 52.829 129.474 54 ;
     RECT  142.308 52.745 142.326 54 ;
     RECT  153.432 51.869 153.45 54 ;
     RECT  155.16 51.869 155.178 54 ;
     RECT  156.708 52.547 156.762 54 ;
     RECT  161.892 53.087 161.91 54 ;
     RECT  168.336 51.737 168.354 54 ;
     RECT  173.736 53.159 173.754 54 ;
     RECT  174.78 53.159 174.798 54 ;
     RECT  179.136 51.869 179.154 54 ;
     RECT  185.256 52.619 185.274 54 ;
     RECT  190.44 52.079 190.458 54 ;
     RECT  197.244 53.941 218.394 54 ;
     RECT  0.108 53.357 0.162 54.095 ;
     RECT  2.304 54 218.394 54.571 ;
     RECT  0.108 54.095 0.126 54.635 ;
     RECT  219.456 53.905 220.266 54.743 ;
     RECT  2.268 54.571 218.394 54.779 ;
     RECT  1.368 54.475 1.386 54.955 ;
     RECT  2.304 54.779 218.394 55.445 ;
     RECT  2.376 55.445 218.394 55.531 ;
     RECT  219.456 54.743 220.194 55.531 ;
     RECT  1.296 54.955 1.386 55.553 ;
     RECT  2.376 55.531 220.194 55.589 ;
     RECT  219.456 55.589 220.194 55.949 ;
     RECT  220.176 55.949 220.194 56.045 ;
     RECT  1.296 55.553 1.314 56.057 ;
     RECT  0.108 55.957 0.126 56.227 ;
     RECT  2.376 55.589 218.358 56.333 ;
     RECT  2.376 56.333 218.322 56.335 ;
     RECT  1.728 56.335 218.322 56.525 ;
     RECT  219.42 56.587 219.438 56.683 ;
     RECT  0.108 56.227 0.27 56.779 ;
     RECT  0.108 56.779 0.558 56.867 ;
     RECT  219.384 56.683 219.438 57.067 ;
     RECT  220.212 56.395 220.23 57.163 ;
     RECT  2.304 56.525 218.322 57.293 ;
     RECT  219.348 57.067 219.438 57.407 ;
     RECT  219.348 57.407 219.366 57.451 ;
     RECT  220.176 57.163 220.23 57.479 ;
     RECT  218.844 57.451 219.366 57.569 ;
     RECT  0.108 56.867 0.27 57.721 ;
     RECT  218.844 57.569 218.862 57.749 ;
     RECT  0.108 57.721 0.558 58.061 ;
     RECT  2.304 57.293 217.854 58.109 ;
     RECT  2.304 58.109 217.782 58.123 ;
     RECT  2.268 58.123 217.782 58.217 ;
     RECT  0.108 58.061 0.198 58.415 ;
     RECT  218.88 58.351 218.898 58.507 ;
     RECT  218.844 58.507 218.898 58.699 ;
     RECT  220.176 57.479 220.194 58.795 ;
     RECT  0.144 58.415 0.198 58.891 ;
     RECT  2.304 58.217 217.782 58.919 ;
     RECT  0.144 58.891 0.342 58.999 ;
     RECT  2.304 58.919 11.43 59.027 ;
     RECT  12.276 58.919 217.782 59.035 ;
     RECT  12.276 59.035 217.818 59.063 ;
     RECT  218.844 58.699 219.438 59.179 ;
     RECT  12.312 59.063 217.818 59.269 ;
     RECT  218.808 59.179 219.438 59.269 ;
     RECT  12.312 59.269 219.438 59.341 ;
     RECT  220.176 58.795 220.23 59.341 ;
     RECT  0.144 58.999 0.558 59.371 ;
     RECT  0.108 59.371 0.558 59.567 ;
     RECT  12.312 59.341 220.23 59.597 ;
     RECT  2.304 59.027 11.25 59.837 ;
     RECT  12.312 59.597 219.438 59.909 ;
     RECT  220.176 59.597 220.23 59.999 ;
     RECT  220.212 59.999 220.23 60.269 ;
     RECT  0.108 59.567 0.342 60.365 ;
     RECT  0.108 60.365 0.234 60.377 ;
     RECT  0.108 60.377 0.162 60.413 ;
     RECT  12.312 59.909 217.818 60.413 ;
     RECT  2.304 59.837 8.19 60.421 ;
     RECT  218.808 59.909 219.438 60.449 ;
     RECT  2.268 60.421 8.19 60.461 ;
     RECT  2.304 60.461 8.19 60.691 ;
     RECT  9.144 59.837 11.25 60.691 ;
     RECT  2.304 60.691 11.25 60.809 ;
     RECT  218.808 60.449 218.862 60.809 ;
     RECT  0.108 60.413 0.126 60.845 ;
     RECT  1.296 60.523 1.314 60.907 ;
     RECT  9.108 60.809 11.25 61.004 ;
     RECT  9.144 61.004 11.25 61.079 ;
     RECT  12.312 60.413 217.71 61.195 ;
     RECT  218.88 61.231 218.898 61.429 ;
     RECT  12.312 61.195 217.818 61.619 ;
     RECT  13.068 61.619 217.818 61.627 ;
     RECT  218.88 61.429 219.474 61.627 ;
     RECT  1.152 60.907 1.314 61.727 ;
     RECT  2.304 60.809 8.298 61.763 ;
     RECT  1.296 61.727 1.314 61.997 ;
     RECT  9.504 61.079 11.25 62.159 ;
     RECT  0.108 62.155 0.126 62.251 ;
     RECT  9.504 62.159 9.522 62.311 ;
     RECT  9.36 62.311 9.522 62.429 ;
     RECT  2.304 61.763 3.042 62.509 ;
     RECT  3.78 61.763 8.298 62.509 ;
     RECT  9.396 62.429 9.522 62.609 ;
     RECT  2.304 62.509 8.442 62.635 ;
     RECT  9.468 62.609 9.522 62.699 ;
     RECT  0.108 62.251 0.162 62.731 ;
     RECT  2.268 62.635 8.442 62.743 ;
     RECT  220.212 62.635 220.23 62.807 ;
     RECT  12.312 61.619 12.33 63.067 ;
     RECT  13.068 61.627 219.474 63.067 ;
     RECT  12.312 63.067 219.474 63.166 ;
     RECT  12.312 63.166 219.582 63.275 ;
     RECT  13.215 63.275 219.582 63.341 ;
     RECT  2.268 62.743 8.55 63.509 ;
     RECT  2.268 63.509 8.514 63.545 ;
     RECT  0.108 62.731 0.558 63.617 ;
     RECT  2.304 63.545 8.514 63.779 ;
     RECT  218.88 63.341 219.582 63.787 ;
     RECT  2.304 63.779 8.37 63.815 ;
     RECT  218.88 63.787 220.23 63.851 ;
     RECT  218.88 63.851 219.546 64.013 ;
     RECT  10.692 62.159 11.25 64.049 ;
     RECT  2.304 63.815 8.298 64.267 ;
     RECT  9.504 62.699 9.522 64.319 ;
     RECT  12.312 63.275 12.33 64.463 ;
     RECT  2.268 64.267 8.298 64.561 ;
     RECT  9.36 64.471 9.414 64.589 ;
     RECT  13.215 63.341 217.854 64.589 ;
     RECT  2.268 64.561 8.514 64.733 ;
     RECT  0.108 63.617 0.162 64.741 ;
     RECT  9.396 64.589 9.414 64.769 ;
     RECT  0.108 64.741 0.558 64.781 ;
     RECT  2.268 64.733 6.858 64.931 ;
     RECT  218.88 64.013 219.51 64.939 ;
     RECT  218.88 64.939 220.23 65.035 ;
     RECT  6.84 64.931 6.858 65.129 ;
     RECT  2.268 64.931 5.886 65.165 ;
     RECT  218.844 65.035 220.23 65.237 ;
     RECT  13.215 64.589 21.402 65.261 ;
     RECT  7.815 64.733 8.514 65.281 ;
     RECT  22.176 64.589 217.854 65.281 ;
     RECT  22.176 65.281 218.358 65.357 ;
     RECT  11.232 64.049 11.25 65.371 ;
     RECT  2.304 65.165 5.886 65.435 ;
     RECT  22.176 65.357 218.286 65.453 ;
     RECT  22.284 65.453 218.286 65.501 ;
     RECT  11.232 65.371 11.502 65.551 ;
     RECT  2.415 65.435 5.886 65.741 ;
     RECT  219.348 65.237 220.23 65.777 ;
     RECT  2.415 65.741 4.59 65.813 ;
     RECT  10.908 65.551 11.502 65.813 ;
     RECT  22.284 65.501 217.818 65.849 ;
     RECT  2.415 65.813 4.554 65.939 ;
     RECT  5.472 65.741 5.886 65.939 ;
     RECT  7.815 65.281 8.622 65.939 ;
     RECT  1.152 64.939 1.17 65.975 ;
     RECT  5.868 65.939 5.886 65.975 ;
     RECT  22.284 65.849 205.002 66.029 ;
     RECT  13.215 65.261 17.19 66.055 ;
     RECT  13.215 66.055 17.226 66.139 ;
     RECT  18.18 65.261 21.402 66.139 ;
     RECT  13.215 66.139 21.402 66.187 ;
     RECT  22.284 66.029 202.497 66.187 ;
     RECT  2.415 65.939 4.518 66.209 ;
     RECT  13.215 66.187 202.497 66.209 ;
     RECT  0.108 64.781 0.126 66.245 ;
     RECT  4.068 66.209 4.518 66.245 ;
     RECT  11.484 65.813 11.502 66.245 ;
     RECT  206.136 65.849 217.818 66.289 ;
     RECT  219.384 65.777 220.23 66.317 ;
     RECT  6.84 66.289 6.858 66.389 ;
     RECT  13.215 66.209 17.19 66.515 ;
     RECT  4.5 66.245 4.518 66.701 ;
     RECT  18.18 66.209 202.497 66.749 ;
     RECT  203.22 66.029 205.002 66.749 ;
     RECT  206.136 66.289 217.962 66.785 ;
     RECT  18.18 66.749 198.342 66.797 ;
     RECT  6.984 66.811 7.002 66.857 ;
     RECT  206.352 66.785 217.962 66.859 ;
     RECT  206.352 66.859 218.25 66.955 ;
     RECT  219.384 66.317 220.158 66.955 ;
     RECT  14.724 66.515 17.19 67.003 ;
     RECT  18.18 66.797 21.942 67.003 ;
     RECT  206.352 66.955 220.158 67.019 ;
     RECT  210.636 67.019 220.158 67.051 ;
     RECT  199.188 66.749 202.497 67.055 ;
     RECT  22.752 66.797 197.73 67.091 ;
     RECT  206.352 67.019 209.862 67.133 ;
     RECT  199.188 67.055 201.474 67.397 ;
     RECT  14.724 67.003 21.942 67.531 ;
     RECT  22.752 67.091 197.64 67.531 ;
     RECT  206.352 67.133 209.826 67.675 ;
     RECT  210.636 67.051 220.23 67.805 ;
     RECT  14.724 67.531 197.64 67.829 ;
     RECT  212.184 67.805 220.23 67.973 ;
     RECT  206.136 67.675 209.826 67.981 ;
     RECT  210.636 67.805 211.446 67.981 ;
     RECT  16.524 67.829 197.64 68.099 ;
     RECT  17.748 68.099 197.64 68.107 ;
     RECT  206.136 67.981 211.446 68.155 ;
     RECT  17.748 68.107 197.73 68.171 ;
     RECT  218.808 67.973 220.23 68.215 ;
     RECT  22.752 68.171 197.73 68.333 ;
     RECT  199.188 67.397 200.934 68.341 ;
     RECT  203.76 66.749 205.002 68.549 ;
     RECT  206.1 68.155 211.446 68.611 ;
     RECT  212.184 67.973 217.854 68.611 ;
     RECT  206.1 68.611 217.854 68.675 ;
     RECT  218.808 68.215 220.302 68.779 ;
     RECT  14.724 67.829 15.714 68.791 ;
     RECT  16.524 68.099 16.974 68.791 ;
     RECT  22.788 68.333 197.73 68.791 ;
     RECT  198.936 68.341 200.934 68.791 ;
     RECT  22.788 68.791 200.934 68.981 ;
     RECT  13.215 66.515 13.806 69.061 ;
     RECT  14.724 68.791 16.974 69.061 ;
     RECT  206.1 68.675 217.782 69.179 ;
     RECT  206.172 69.179 217.782 69.215 ;
     RECT  203.76 68.549 204.39 69.251 ;
     RECT  206.172 69.215 206.19 69.251 ;
     RECT  13.215 69.061 16.974 69.331 ;
     RECT  17.748 68.171 21.762 69.331 ;
     RECT  22.788 68.981 197.766 69.355 ;
     RECT  207.036 69.215 217.782 69.421 ;
     RECT  218.556 68.779 220.302 69.421 ;
     RECT  207.036 69.421 220.302 69.449 ;
     RECT  13.215 69.331 21.762 69.485 ;
     RECT  203.796 69.251 204.39 69.529 ;
     RECT  198.936 68.981 200.934 69.581 ;
     RECT  203.796 69.529 204.714 69.593 ;
     RECT  207.18 69.449 220.302 69.629 ;
     RECT  22.752 69.355 197.766 69.763 ;
     RECT  204.624 69.593 204.714 69.899 ;
     RECT  207.324 69.629 220.302 69.899 ;
     RECT  209.052 69.899 220.302 70.109 ;
     RECT  22.752 69.763 198.45 70.123 ;
     RECT  199.188 69.581 200.934 70.123 ;
     RECT  209.988 70.109 220.302 70.133 ;
     RECT  22.716 70.123 198.45 70.141 ;
     RECT  209.052 70.109 209.214 70.169 ;
     RECT  209.988 70.133 211.23 70.259 ;
     RECT  199.188 70.123 201.186 70.267 ;
     RECT  199.188 70.267 201.438 70.295 ;
     RECT  204.624 69.899 204.642 70.295 ;
     RECT  209.052 70.169 209.178 70.295 ;
     RECT  209.988 70.259 211.086 70.301 ;
     RECT  209.988 70.301 210.366 70.304 ;
     RECT  212.04 70.133 220.302 70.367 ;
     RECT  207.324 69.899 208.206 70.403 ;
     RECT  22.644 70.141 198.45 70.411 ;
     RECT  199.188 70.295 200.538 70.411 ;
     RECT  13.215 69.485 21.69 70.439 ;
     RECT  201.42 70.295 201.438 70.439 ;
     RECT  22.644 70.411 200.538 70.484 ;
     RECT  22.644 70.484 198.45 70.501 ;
     RECT  207.615 70.403 208.206 70.529 ;
     RECT  13.215 70.439 21.114 70.537 ;
     RECT  207.615 70.529 208.062 70.565 ;
     RECT  12.996 70.537 21.114 70.589 ;
     RECT  212.184 70.367 220.302 70.601 ;
     RECT  210.348 70.304 210.366 70.637 ;
     RECT  212.184 70.601 219.15 70.709 ;
     RECT  212.364 70.709 219.15 70.799 ;
     RECT  13.215 70.589 21.114 71.179 ;
     RECT  22.212 70.501 198.45 71.179 ;
     RECT  212.616 70.799 219.15 71.339 ;
     RECT  203.796 69.593 203.814 71.375 ;
     RECT  13.215 71.179 198.45 71.383 ;
     RECT  199.188 70.484 200.538 71.383 ;
     RECT  212.616 71.339 213.297 71.519 ;
     RECT  214.344 71.339 219.15 71.645 ;
     RECT  214.344 71.645 214.362 71.789 ;
     RECT  215.46 71.645 219.15 72.149 ;
     RECT  215.46 72.149 218.106 72.257 ;
     RECT  13.215 71.383 200.538 72.293 ;
     RECT  19.872 72.293 200.538 72.374 ;
     RECT  215.46 72.257 218.07 72.419 ;
     RECT  215.46 72.419 217.89 72.455 ;
     RECT  19.872 72.374 198.45 72.563 ;
     RECT  220.068 70.601 220.302 72.563 ;
     RECT  220.068 72.563 220.23 72.599 ;
     RECT  215.46 72.455 217.818 72.689 ;
     RECT  220.068 72.599 220.086 72.689 ;
     RECT  216.216 72.689 217.818 72.725 ;
     RECT  216.216 72.725 216.27 72.797 ;
     RECT  219.132 72.149 219.15 72.869 ;
     RECT  19.872 72.563 198.378 72.959 ;
     RECT  215.46 72.689 215.478 72.959 ;
     RECT  217.008 72.725 217.782 72.959 ;
     RECT  13.215 72.293 18.99 73.003 ;
     RECT  13.104 73.003 18.99 73.039 ;
     RECT  19.872 72.959 21.69 73.039 ;
     RECT  216.216 72.797 216.234 73.103 ;
     RECT  22.752 72.959 198.378 73.139 ;
     RECT  13.104 73.039 21.69 73.499 ;
     RECT  199.188 72.374 200.538 73.507 ;
     RECT  13.215 73.499 21.69 73.769 ;
     RECT  18.072 73.769 21.69 74.059 ;
     RECT  22.752 73.139 197.766 74.059 ;
     RECT  13.215 73.769 17.19 74.219 ;
     RECT  18.072 74.059 197.766 74.236 ;
     RECT  198.936 73.507 200.538 74.236 ;
     RECT  18.072 74.236 200.538 74.309 ;
     RECT  18.072 74.309 198.45 74.489 ;
     RECT  18.072 74.489 20.718 74.579 ;
     RECT  18.072 74.579 20.538 74.587 ;
     RECT  21.708 74.489 198.45 74.669 ;
     RECT  18 74.587 20.538 75.001 ;
     RECT  17.964 75.001 20.538 75.091 ;
     RECT  13.215 74.219 16.974 75.115 ;
     RECT  17.928 75.091 20.538 75.115 ;
     RECT  13.215 75.115 20.538 75.307 ;
     RECT  22.212 74.669 198.45 75.667 ;
     RECT  199.188 74.309 200.538 75.667 ;
     RECT  22.212 75.667 200.538 75.691 ;
     RECT  13.215 75.307 20.574 75.775 ;
     RECT  21.636 75.691 200.538 75.901 ;
     RECT  21.6 75.901 200.538 76.397 ;
     RECT  13.215 75.775 20.718 76.459 ;
     RECT  21.6 76.397 198.45 76.459 ;
     RECT  13.215 76.459 198.45 76.469 ;
     RECT  22.14 76.469 198.45 77.009 ;
     RECT  13.215 76.469 21.114 77.315 ;
     RECT  13.215 77.315 20.826 77.549 ;
     RECT  22.176 77.009 198.45 77.549 ;
     RECT  22.248 77.549 198.45 77.645 ;
     RECT  17.928 77.549 20.826 77.693 ;
     RECT  13.215 77.549 17.118 77.855 ;
     RECT  13.215 77.855 16.074 77.999 ;
     RECT  7.815 65.939 8.097 78.043 ;
     RECT  22.284 77.645 198.45 78.061 ;
     RECT  199.188 76.397 200.538 78.061 ;
     RECT  10.836 77.947 10.854 78.077 ;
     RECT  7.815 78.043 8.19 78.089 ;
     RECT  14.58 77.999 16.074 78.089 ;
     RECT  14.58 78.089 16.038 78.269 ;
     RECT  22.284 78.061 200.538 78.379 ;
     RECT  16.812 77.855 17.118 78.403 ;
     RECT  16.812 78.403 17.19 78.439 ;
     RECT  17.928 77.693 20.718 78.439 ;
     RECT  22.212 78.379 200.538 78.475 ;
     RECT  14.796 78.269 16.038 78.629 ;
     RECT  16.812 78.439 20.718 78.629 ;
     RECT  14.796 78.629 15.894 78.653 ;
     RECT  21.636 78.475 200.538 78.736 ;
     RECT  15.408 78.653 15.894 78.899 ;
     RECT  21.6 78.736 200.538 78.971 ;
     RECT  16.884 78.629 20.718 79.435 ;
     RECT  16.884 79.435 21.078 79.825 ;
     RECT  15.408 78.899 15.426 79.861 ;
     RECT  16.164 79.825 21.078 79.889 ;
     RECT  16.164 79.889 20.682 79.979 ;
     RECT  2.415 66.209 2.697 79.987 ;
     RECT  2.415 79.987 2.97 80.023 ;
     RECT  14.832 79.861 15.426 80.051 ;
     RECT  6.84 79.951 6.858 80.059 ;
     RECT  4.392 80.059 4.41 80.095 ;
     RECT  5.364 80.059 5.382 80.095 ;
     RECT  15.372 80.051 15.426 80.095 ;
     RECT  2.415 80.023 3.402 80.131 ;
     RECT  4.392 80.095 5.382 80.131 ;
     RECT  6.156 80.059 6.858 80.131 ;
     RECT  7.815 78.089 8.097 80.131 ;
     RECT  2.415 80.131 8.097 80.221 ;
     RECT  22.14 78.971 200.538 80.221 ;
     RECT  15.372 80.095 16.038 80.381 ;
     RECT  16.956 79.979 20.682 80.519 ;
     RECT  16.956 80.519 17.37 80.573 ;
     RECT  2.376 80.221 8.097 80.599 ;
     RECT  12.024 80.491 12.042 80.761 ;
     RECT  21.672 80.221 200.538 80.909 ;
     RECT  0.18 80.635 0.198 80.941 ;
     RECT  18.216 80.519 20.682 80.971 ;
     RECT  18.216 80.971 21.078 81.101 ;
     RECT  2.304 80.599 8.097 81.103 ;
     RECT  15.372 80.381 15.426 81.103 ;
     RECT  18.216 81.101 21.042 81.131 ;
     RECT  0.18 80.941 0.522 81.139 ;
     RECT  0.18 81.139 0.558 81.163 ;
     RECT  18.216 81.131 20.502 81.409 ;
     RECT  0.108 81.163 0.558 81.437 ;
     RECT  15.372 81.103 15.462 81.437 ;
     RECT  17.1 80.573 17.37 81.437 ;
     RECT  2.268 81.103 8.097 81.481 ;
     RECT  18.144 81.409 20.502 81.481 ;
     RECT  13.215 77.999 13.806 81.571 ;
     RECT  10.224 81.481 10.242 81.599 ;
     RECT  2.268 81.481 8.586 81.634 ;
     RECT  2.268 81.634 8.622 81.677 ;
     RECT  15.372 81.437 15.426 81.679 ;
     RECT  12.852 81.571 13.806 81.707 ;
     RECT  10.728 81.679 10.746 81.715 ;
     RECT  0.108 81.437 0.522 81.773 ;
     RECT  0.144 81.773 0.522 81.905 ;
     RECT  10.728 81.715 10.926 81.905 ;
     RECT  17.676 81.481 20.502 81.931 ;
     RECT  0.18 81.905 0.522 81.965 ;
     RECT  2.268 81.677 8.37 81.985 ;
     RECT  13.215 81.707 13.806 81.985 ;
     RECT  9.18 81.931 9.198 82.021 ;
     RECT  22.176 80.909 200.538 82.123 ;
     RECT  13.215 81.985 13.878 82.147 ;
     RECT  0.324 81.965 0.522 82.157 ;
     RECT  11.988 80.761 12.042 82.175 ;
     RECT  17.676 81.931 20.538 82.175 ;
     RECT  16.488 81.643 16.506 82.211 ;
     RECT  18.252 82.175 20.538 82.247 ;
     RECT  9.18 82.021 9.306 82.291 ;
     RECT  13.215 82.147 14.058 82.291 ;
     RECT  10.728 81.905 10.818 82.381 ;
     RECT  13.215 82.291 14.13 82.417 ;
     RECT  14.868 81.679 15.426 82.417 ;
     RECT  0.324 82.157 0.342 82.445 ;
     RECT  11.988 82.175 12.006 82.445 ;
     RECT  1.728 81.985 8.37 82.453 ;
     RECT  9.18 82.291 9.63 82.453 ;
     RECT  18.615 82.247 20.538 82.481 ;
     RECT  1.728 82.453 9.63 82.489 ;
     RECT  21.636 82.123 200.538 82.553 ;
     RECT  16.524 82.291 16.542 82.561 ;
     RECT  1.728 82.489 9.666 82.589 ;
     RECT  20.484 82.481 20.538 82.651 ;
     RECT  21.636 82.553 198.45 82.651 ;
     RECT  9.648 82.589 9.666 82.679 ;
     RECT  16.524 82.561 17.19 82.679 ;
     RECT  16.524 82.679 16.542 82.715 ;
     RECT  20.484 82.651 198.45 82.733 ;
     RECT  10.692 82.381 10.818 82.921 ;
     RECT  18.615 82.481 19.494 82.985 ;
     RECT  13.215 82.417 15.426 82.993 ;
     RECT  20.484 82.733 20.502 83.129 ;
     RECT  1.728 82.589 8.694 83.179 ;
     RECT  9.756 82.921 10.818 83.219 ;
     RECT  13.215 82.993 15.462 83.275 ;
     RECT  13.215 83.275 15.966 83.363 ;
     RECT  10.764 83.219 10.818 83.371 ;
     RECT  9.756 83.219 9.846 83.399 ;
     RECT  21.636 82.733 198.45 83.467 ;
     RECT  14.832 83.363 15.966 83.489 ;
     RECT  14.832 83.489 15.462 83.501 ;
     RECT  0.108 82.795 0.162 83.563 ;
     RECT  0.108 83.563 0.234 83.633 ;
     RECT  1.152 83.179 8.694 83.641 ;
     RECT  9.828 83.399 9.846 83.759 ;
     RECT  21.06 83.467 198.45 83.767 ;
     RECT  199.188 82.553 200.538 83.767 ;
     RECT  0.108 83.633 0.162 83.789 ;
     RECT  10.764 83.371 10.854 83.875 ;
     RECT  1.152 83.641 8.982 83.885 ;
     RECT  15.408 83.501 15.462 83.939 ;
     RECT  21.06 83.767 200.538 84.043 ;
     RECT  17.064 83.563 17.082 84.109 ;
     RECT  19.908 83.659 19.926 84.109 ;
     RECT  21.024 84.043 200.538 84.109 ;
     RECT  10.764 83.875 10.89 84.173 ;
     RECT  2.268 83.885 8.982 84.181 ;
     RECT  18.615 82.985 18.897 84.181 ;
     RECT  19.908 84.109 200.538 84.181 ;
     RECT  18.615 84.181 200.538 84.299 ;
     RECT  17.064 84.109 17.118 84.379 ;
     RECT  15.408 83.939 15.426 84.415 ;
     RECT  18.615 84.299 197.766 84.443 ;
     RECT  19.908 84.443 197.766 84.461 ;
     RECT  198.936 84.299 200.538 84.461 ;
     RECT  19.908 84.461 19.926 84.479 ;
     RECT  10.836 84.173 10.89 84.541 ;
     RECT  14.724 84.415 15.426 84.569 ;
     RECT  0.108 83.789 0.126 84.571 ;
     RECT  16.416 84.379 17.118 84.577 ;
     RECT  0.108 84.571 0.162 84.605 ;
     RECT  16.236 84.577 17.73 84.677 ;
     RECT  2.268 84.181 9.234 84.721 ;
     RECT  0.144 84.605 0.162 84.749 ;
     RECT  10.836 84.541 10.962 84.749 ;
     RECT  21.06 84.461 197.766 84.749 ;
     RECT  14.832 84.569 15.426 84.811 ;
     RECT  16.236 84.677 16.506 84.811 ;
     RECT  10.836 84.749 10.926 84.839 ;
     RECT  17.352 84.677 17.73 84.839 ;
     RECT  21.636 84.749 197.766 84.839 ;
     RECT  2.268 84.721 9.738 84.859 ;
     RECT  1.152 83.885 1.17 84.883 ;
     RECT  2.268 84.859 9.774 84.883 ;
     RECT  1.152 84.883 9.774 84.911 ;
     RECT  1.152 84.911 9.63 85.019 ;
     RECT  14.832 84.811 16.506 85.019 ;
     RECT  1.152 85.019 9.162 85.037 ;
     RECT  18.615 84.443 18.954 85.099 ;
     RECT  21.672 84.839 197.766 85.117 ;
     RECT  17.352 84.839 17.442 85.181 ;
     RECT  18.216 85.099 18.954 85.189 ;
     RECT  21.672 85.117 198.45 85.189 ;
     RECT  199.188 84.461 200.538 85.189 ;
     RECT  2.304 85.037 9.162 85.217 ;
     RECT  13.215 83.363 13.806 85.261 ;
     RECT  1.152 85.037 1.386 85.291 ;
     RECT  0.18 85.291 1.386 85.483 ;
     RECT  0.108 85.483 1.386 85.487 ;
     RECT  18.216 85.189 19.422 85.517 ;
     RECT  14.832 85.019 16.47 85.568 ;
     RECT  10.368 85.195 10.386 85.649 ;
     RECT  15.012 85.568 16.47 85.649 ;
     RECT  21.672 85.189 200.538 85.675 ;
     RECT  15.408 85.649 16.47 85.829 ;
     RECT  21.636 85.675 200.538 85.829 ;
     RECT  2.304 85.217 8.838 85.919 ;
     RECT  9.684 85.801 10.026 85.919 ;
     RECT  15.408 85.829 16.002 85.919 ;
     RECT  21.636 85.829 21.654 86.059 ;
     RECT  9.684 85.919 9.81 86.071 ;
     RECT  17.424 85.181 17.442 86.071 ;
     RECT  18.216 85.517 18.897 86.071 ;
     RECT  9.576 86.071 9.81 86.189 ;
     RECT  17.424 86.071 18.897 86.189 ;
     RECT  13.104 85.261 13.806 86.233 ;
     RECT  2.376 85.919 8.838 86.269 ;
     RECT  9.576 86.189 9.702 86.269 ;
     RECT  0.108 85.487 0.342 86.305 ;
     RECT  1.152 85.487 1.386 86.305 ;
     RECT  12.6 86.233 13.806 86.369 ;
     RECT  17.892 86.189 18.897 86.459 ;
     RECT  21.06 86.059 21.654 86.459 ;
     RECT  13.215 86.369 13.806 86.575 ;
     RECT  0.108 86.305 1.386 86.603 ;
     RECT  18.252 86.459 18.897 86.611 ;
     RECT  18.252 86.611 18.954 86.635 ;
     RECT  2.376 86.269 9.702 86.731 ;
     RECT  15.408 85.919 15.93 86.731 ;
     RECT  10.8 86.467 10.89 86.737 ;
     RECT  13.215 86.575 13.986 86.737 ;
     RECT  14.724 86.731 15.93 86.737 ;
     RECT  10.512 86.737 10.926 86.773 ;
     RECT  17.064 86.251 17.082 86.779 ;
     RECT  18.252 86.635 18.99 86.813 ;
     RECT  10.512 86.773 11.25 86.971 ;
     RECT  13.215 86.737 16.002 86.999 ;
     RECT  2.304 86.731 9.702 87.035 ;
     RECT  10.512 86.971 11.322 87.071 ;
     RECT  10.512 87.071 10.53 87.115 ;
     RECT  19.908 86.539 19.926 87.115 ;
     RECT  21.06 86.459 21.078 87.115 ;
     RECT  0.108 86.603 1.17 87.143 ;
     RECT  2.304 87.035 9.414 87.179 ;
     RECT  13.215 86.999 13.59 87.179 ;
     RECT  10.224 87.115 10.53 87.269 ;
     RECT  19.908 87.115 21.078 87.341 ;
     RECT  2.304 87.179 9.342 87.499 ;
     RECT  20.484 87.341 21.078 87.539 ;
     RECT  14.724 86.999 16.002 87.547 ;
     RECT  17.028 86.779 17.082 87.547 ;
     RECT  18.252 86.813 18.897 87.595 ;
     RECT  0.144 87.143 1.17 87.629 ;
     RECT  13.215 87.179 13.497 87.655 ;
     RECT  0.324 87.629 1.17 87.691 ;
     RECT  22.788 85.829 200.538 87.691 ;
     RECT  14.724 87.547 17.082 87.719 ;
     RECT  22.212 87.691 200.538 87.787 ;
     RECT  10.512 87.269 10.53 87.853 ;
     RECT  12.564 87.655 13.497 87.917 ;
     RECT  2.268 87.499 9.342 87.925 ;
     RECT  2.268 87.925 9.666 87.953 ;
     RECT  18.216 87.595 18.897 87.961 ;
     RECT  16.488 87.719 17.082 87.989 ;
     RECT  20.484 87.539 21.042 88.075 ;
     RECT  13.215 87.917 13.497 88.087 ;
     RECT  14.724 87.719 15.426 88.087 ;
     RECT  10.512 87.853 10.818 88.123 ;
     RECT  13.215 88.087 15.426 88.151 ;
     RECT  20.448 88.075 21.042 88.171 ;
     RECT  19.908 88.171 21.042 88.267 ;
     RECT  13.215 88.151 14.346 88.385 ;
     RECT  10.512 88.123 10.998 88.465 ;
     RECT  17.028 87.989 17.082 88.529 ;
     RECT  0.324 87.691 1.206 88.555 ;
     RECT  15.372 88.151 15.426 88.591 ;
     RECT  18.144 87.961 18.897 88.591 ;
     RECT  15.372 88.591 16.002 88.619 ;
     RECT  18.144 88.591 18.954 88.651 ;
     RECT  15.984 88.619 16.002 88.691 ;
     RECT  0.108 88.555 1.206 88.727 ;
     RECT  13.215 88.385 13.497 88.735 ;
     RECT  0.108 88.727 0.558 88.763 ;
     RECT  19.908 88.267 21.078 88.889 ;
     RECT  14.472 88.933 14.49 88.969 ;
     RECT  19.908 88.889 20.502 89.033 ;
     RECT  22.176 87.787 200.538 89.035 ;
     RECT  21.636 89.035 200.538 89.159 ;
     RECT  2.304 87.953 9.666 89.167 ;
     RECT  10.512 88.465 11.106 89.167 ;
     RECT  14.472 88.969 14.85 89.267 ;
     RECT  17.64 88.651 18.954 89.323 ;
     RECT  17.64 89.323 18.99 89.419 ;
     RECT  2.304 89.167 11.106 89.429 ;
     RECT  14.544 89.267 14.85 89.429 ;
     RECT  22.752 89.159 200.538 89.429 ;
     RECT  21.636 89.159 21.654 89.465 ;
     RECT  17.604 89.419 18.99 89.467 ;
     RECT  14.616 89.429 14.85 89.501 ;
     RECT  17.388 89.467 18.99 89.501 ;
     RECT  22.752 89.429 197.766 89.501 ;
     RECT  198.936 89.429 200.538 89.549 ;
     RECT  14.832 89.501 14.85 89.699 ;
     RECT  12.672 88.735 13.497 89.707 ;
     RECT  0.108 88.763 0.342 89.741 ;
     RECT  1.368 88.747 1.386 89.843 ;
     RECT  17.388 89.501 18.897 89.879 ;
     RECT  12.672 89.707 13.662 90.005 ;
     RECT  17.46 89.879 18.897 90.005 ;
     RECT  19.908 89.033 19.926 90.041 ;
     RECT  17.568 90.005 18.897 90.149 ;
     RECT  2.304 89.429 9.378 90.247 ;
     RECT  10.26 89.429 11.106 90.247 ;
     RECT  13.215 90.005 13.662 90.283 ;
     RECT  17.604 90.149 18.897 90.283 ;
     RECT  21.096 90.049 21.114 90.379 ;
     RECT  21.096 90.379 21.654 90.419 ;
     RECT  22.788 89.501 197.766 90.481 ;
     RECT  22.788 90.481 198.378 90.571 ;
     RECT  22.176 90.571 198.378 90.787 ;
     RECT  22.176 90.787 198.45 90.823 ;
     RECT  199.188 89.549 200.538 90.823 ;
     RECT  2.304 90.247 11.106 90.853 ;
     RECT  2.304 90.853 11.43 90.893 ;
     RECT  0.108 89.741 0.27 90.931 ;
     RECT  1.152 90.571 1.17 90.931 ;
     RECT  17.604 90.283 19.386 90.959 ;
     RECT  0.108 90.931 1.17 90.989 ;
     RECT  2.304 90.893 11.106 91.049 ;
     RECT  21.06 90.475 21.078 91.051 ;
     RECT  13.215 90.283 13.806 91.085 ;
     RECT  20.448 91.051 21.078 91.147 ;
     RECT  22.176 90.823 200.538 91.147 ;
     RECT  0.108 90.989 0.27 91.193 ;
     RECT  18.615 90.959 19.386 91.201 ;
     RECT  20.448 91.147 200.538 91.201 ;
     RECT  18.615 91.201 200.538 91.229 ;
     RECT  22.14 91.229 200.538 91.277 ;
     RECT  18.615 91.229 21.078 91.319 ;
     RECT  17.604 90.959 17.622 91.391 ;
     RECT  0.108 91.193 0.198 91.499 ;
     RECT  2.304 91.049 9.45 91.589 ;
     RECT  0.108 91.499 0.126 91.661 ;
     RECT  18.615 91.319 20.502 91.859 ;
     RECT  199.188 91.277 200.538 91.895 ;
     RECT  18.615 91.859 20.466 92.003 ;
     RECT  22.14 91.277 198.45 92.107 ;
     RECT  14.652 91.975 14.67 92.129 ;
     RECT  21.636 92.107 198.45 92.237 ;
     RECT  2.304 91.589 9.414 92.281 ;
     RECT  21.636 92.237 198.378 92.299 ;
     RECT  21.6 92.299 198.378 92.399 ;
     RECT  16.488 92.203 16.506 92.471 ;
     RECT  2.268 92.281 9.414 92.479 ;
     RECT  20.448 92.003 20.466 92.507 ;
     RECT  17.676 92.407 17.694 92.551 ;
     RECT  2.268 92.479 9.522 92.579 ;
     RECT  1.152 90.989 1.17 92.587 ;
     RECT  199.512 91.895 200.538 92.669 ;
     RECT  1.152 92.587 1.206 92.705 ;
     RECT  17.1 92.551 17.694 92.765 ;
     RECT  0.108 92.395 0.126 92.777 ;
     RECT  2.268 92.579 9.45 92.849 ;
     RECT  17.1 92.765 17.118 92.939 ;
     RECT  13.215 91.085 13.497 92.947 ;
     RECT  1.188 92.705 1.206 92.971 ;
     RECT  13.215 92.947 14.382 92.971 ;
     RECT  21.636 92.399 198.378 92.975 ;
     RECT  20.484 92.683 20.502 93.011 ;
     RECT  18.615 92.003 19.386 93.047 ;
     RECT  13.215 92.971 14.742 93.091 ;
     RECT  22.176 92.975 198.378 93.091 ;
     RECT  18.615 93.047 19.17 93.119 ;
     RECT  18.615 93.119 19.062 93.209 ;
     RECT  15.948 92.779 15.966 93.211 ;
     RECT  18.615 93.209 18.954 93.245 ;
     RECT  13.215 93.091 14.886 93.281 ;
     RECT  22.176 93.091 198.486 93.317 ;
     RECT  22.212 93.317 198.486 93.353 ;
     RECT  15.948 93.211 16.506 93.451 ;
     RECT  13.215 93.281 14.202 93.479 ;
     RECT  1.188 92.971 1.386 93.515 ;
     RECT  0.18 93.067 0.198 93.547 ;
     RECT  199.512 92.669 200.322 93.547 ;
     RECT  2.268 92.849 9.378 93.587 ;
     RECT  199.476 93.547 200.322 93.623 ;
     RECT  0.108 93.547 0.198 93.631 ;
     RECT  13.215 93.479 13.59 93.659 ;
     RECT  2.304 93.587 9.378 93.721 ;
     RECT  10.512 91.049 11.106 93.721 ;
     RECT  15.408 93.451 16.506 93.739 ;
     RECT  20.952 93.643 20.97 93.739 ;
     RECT  15.408 93.739 17.658 93.749 ;
     RECT  1.368 93.515 1.386 93.835 ;
     RECT  22.212 93.353 198.45 93.857 ;
     RECT  22.212 93.857 198.414 93.929 ;
     RECT  0.108 93.631 0.558 93.965 ;
     RECT  15.948 93.749 17.658 94.027 ;
     RECT  18.615 93.245 18.897 94.027 ;
     RECT  15.948 94.027 18.897 94.163 ;
     RECT  15.948 94.163 16.506 94.199 ;
     RECT  20.952 93.739 21.078 94.219 ;
     RECT  22.752 93.929 198.414 94.289 ;
     RECT  17.64 94.163 18.897 94.315 ;
     RECT  20.52 94.219 21.078 94.397 ;
     RECT  22.896 94.289 198.414 94.397 ;
     RECT  17.64 94.315 19.35 94.441 ;
     RECT  1.368 93.835 1.422 94.507 ;
     RECT  2.304 93.721 11.106 94.507 ;
     RECT  0.108 93.965 0.234 94.595 ;
     RECT  1.368 94.507 11.106 94.699 ;
     RECT  21.06 94.397 21.078 94.739 ;
     RECT  0.144 94.595 0.234 94.795 ;
     RECT  17.64 94.441 19.926 94.829 ;
     RECT  199.584 93.623 200.322 94.829 ;
     RECT  17.64 94.829 19.386 94.901 ;
     RECT  15.948 94.199 15.966 94.937 ;
     RECT  17.64 94.901 19.35 94.973 ;
     RECT  198.396 94.397 198.414 94.981 ;
     RECT  18.615 94.973 19.35 95.009 ;
     RECT  14.544 94.873 14.562 95.099 ;
     RECT  17.64 94.973 17.658 95.441 ;
     RECT  0.144 94.795 0.342 95.467 ;
     RECT  1.152 94.699 11.106 95.467 ;
     RECT  0.144 95.467 11.106 95.513 ;
     RECT  0.144 95.513 1.314 95.755 ;
     RECT  18.615 95.009 18.897 95.881 ;
     RECT  2.268 95.513 11.106 96.053 ;
     RECT  2.304 96.053 11.106 96.179 ;
     RECT  0.108 95.755 1.314 96.215 ;
     RECT  2.304 96.179 11.034 96.359 ;
     RECT  0.144 96.215 1.314 96.427 ;
     RECT  9.9 96.359 11.034 96.719 ;
     RECT  2.304 96.359 8.874 96.749 ;
     RECT  0.144 96.427 1.35 97.097 ;
     RECT  10.872 96.719 11.034 97.133 ;
     RECT  2.304 96.749 6.966 97.259 ;
     RECT  7.74 96.749 8.874 97.259 ;
     RECT  198.396 94.981 198.666 97.259 ;
     RECT  198.612 97.259 198.666 97.411 ;
     RECT  199.62 94.829 200.322 97.411 ;
     RECT  2.304 97.259 6.858 97.529 ;
     RECT  0.144 97.097 0.594 97.565 ;
     RECT  1.332 97.097 1.35 97.637 ;
     RECT  2.304 97.529 6.786 97.709 ;
     RECT  0.216 97.565 0.594 97.835 ;
     RECT  2.304 97.709 6.03 97.943 ;
     RECT  0.576 97.835 0.594 98.105 ;
     RECT  2.415 97.943 6.03 98.339 ;
     RECT  3.456 98.339 5.67 98.717 ;
     RECT  4.104 98.717 5.67 98.753 ;
     RECT  22.896 94.397 197.64 98.851 ;
     RECT  4.104 98.753 5.598 98.951 ;
     RECT  7.815 97.259 8.874 101.759 ;
     RECT  18.615 95.881 19.098 114.845 ;
     RECT  22.5 98.851 197.64 124.488 ;
     RECT  8.82 101.759 8.874 125.141 ;
     RECT  22.5 124.488 22.59 125.177 ;
     RECT  68.22 124.488 68.238 125.653 ;
     RECT  69.804 125.689 69.822 125.725 ;
     RECT  70.668 124.488 70.686 125.725 ;
     RECT  9.9 96.719 10.062 125.753 ;
     RECT  68.22 125.653 68.562 126.229 ;
     RECT  6.768 97.709 6.786 126.257 ;
     RECT  69.804 125.725 70.686 126.265 ;
     RECT  22.5 125.177 22.554 126.293 ;
     RECT  8.856 125.141 8.874 126.329 ;
     RECT  198.612 97.411 200.322 126.329 ;
     RECT  68.22 126.229 68.67 126.571 ;
     RECT  69.516 126.265 70.686 126.571 ;
     RECT  5.04 98.951 5.598 126.599 ;
     RECT  198.612 126.329 200.286 126.599 ;
     RECT  66.888 126.265 66.906 126.613 ;
     RECT  68.076 126.571 70.686 126.613 ;
     RECT  72.36 126.301 72.378 126.613 ;
     RECT  66.888 126.613 70.686 126.689 ;
     RECT  71.568 126.535 71.586 126.689 ;
     RECT  72.36 126.613 72.897 126.689 ;
     RECT  79.884 124.488 80.37 126.689 ;
     RECT  78.207 126.613 78.297 126.697 ;
     RECT  199.188 126.599 200.286 126.725 ;
     RECT  66.888 126.689 67.497 126.733 ;
     RECT  11.016 97.133 11.034 126.761 ;
     RECT  72.432 126.689 72.897 126.797 ;
     RECT  78.207 126.697 78.678 126.797 ;
     RECT  80.424 126.697 80.442 126.797 ;
     RECT  66.708 126.733 67.497 126.833 ;
     RECT  24.207 126.613 24.297 126.883 ;
     RECT  29.607 126.613 29.697 126.883 ;
     RECT  35.007 126.613 35.097 126.883 ;
     RECT  40.407 126.613 40.497 126.883 ;
     RECT  45.807 126.613 45.897 126.883 ;
     RECT  51.207 126.613 51.297 126.883 ;
     RECT  56.607 126.613 56.697 126.883 ;
     RECT  62.007 126.613 62.097 126.883 ;
     RECT  78.207 126.797 78.297 126.883 ;
     RECT  83.607 126.613 83.697 126.883 ;
     RECT  89.007 126.613 89.097 126.883 ;
     RECT  94.407 126.613 94.497 126.883 ;
     RECT  99.807 126.613 99.897 126.883 ;
     RECT  105.207 126.613 105.297 126.883 ;
     RECT  110.607 126.613 110.697 126.883 ;
     RECT  116.007 126.613 116.097 126.883 ;
     RECT  121.407 126.613 121.497 126.883 ;
     RECT  126.807 126.613 126.897 126.883 ;
     RECT  132.207 126.613 132.297 126.883 ;
     RECT  137.607 126.613 137.697 126.883 ;
     RECT  143.007 126.613 143.097 126.883 ;
     RECT  148.407 126.613 148.497 126.883 ;
     RECT  153.807 126.613 153.897 126.883 ;
     RECT  159.207 126.613 159.297 126.883 ;
     RECT  164.607 126.613 164.697 126.883 ;
     RECT  170.007 126.613 170.097 126.883 ;
     RECT  175.407 126.613 175.497 126.883 ;
     RECT  180.807 126.613 180.897 126.883 ;
     RECT  186.207 126.613 186.297 126.883 ;
     RECT  191.607 126.613 191.697 126.883 ;
     RECT  197.007 126.613 197.097 126.883 ;
     RECT  4.104 98.951 4.122 126.959 ;
     RECT  68.22 126.689 70.686 126.959 ;
     RECT  5.58 126.599 5.598 127.139 ;
     RECT  68.22 126.959 69.822 127.229 ;
     RECT  199.836 126.725 200.286 127.229 ;
     RECT  199.836 127.229 199.854 127.499 ;
     RECT  68.22 127.229 68.67 127.769 ;
     RECT  9.9 125.753 9.918 128.039 ;
     RECT  68.652 127.769 68.67 128.039 ;
     RECT  69.804 127.229 69.822 128.309 ;
     RECT  22.536 126.293 22.554 128.345 ;
     RECT  2.415 98.339 2.697 174.707 ;
     RECT  7.815 101.759 8.097 174.707 ;
     RECT  13.215 93.659 13.497 174.707 ;
     RECT  18.615 114.845 18.897 174.707 ;
     RECT  24.015 126.883 24.297 174.707 ;
     RECT  29.415 126.883 29.697 174.707 ;
     RECT  34.815 126.883 35.097 174.707 ;
     RECT  40.215 126.883 40.497 174.707 ;
     RECT  45.615 126.883 45.897 174.707 ;
     RECT  51.015 126.883 51.297 174.707 ;
     RECT  56.415 126.883 56.697 174.707 ;
     RECT  61.815 126.883 62.097 174.707 ;
     RECT  67.215 126.833 67.497 174.707 ;
     RECT  72.615 126.797 72.897 174.707 ;
     RECT  78.015 126.883 78.297 174.707 ;
     RECT  83.415 126.883 83.697 174.707 ;
     RECT  88.815 126.883 89.097 174.707 ;
     RECT  94.215 126.883 94.497 174.707 ;
     RECT  99.615 126.883 99.897 174.707 ;
     RECT  105.015 126.883 105.297 174.707 ;
     RECT  110.415 126.883 110.697 174.707 ;
     RECT  115.815 126.883 116.097 174.707 ;
     RECT  121.215 126.883 121.497 174.707 ;
     RECT  126.615 126.883 126.897 174.707 ;
     RECT  132.015 126.883 132.297 174.707 ;
     RECT  137.415 126.883 137.697 174.707 ;
     RECT  142.815 126.883 143.097 174.707 ;
     RECT  148.215 126.883 148.497 174.707 ;
     RECT  153.615 126.883 153.897 174.707 ;
     RECT  159.015 126.883 159.297 174.707 ;
     RECT  164.415 126.883 164.697 174.707 ;
     RECT  169.815 126.883 170.097 174.707 ;
     RECT  175.215 126.883 175.497 174.707 ;
     RECT  180.615 126.883 180.897 174.707 ;
     RECT  186.015 126.883 186.297 174.707 ;
     RECT  191.415 126.883 191.697 174.707 ;
     RECT  196.815 126.883 197.097 174.707 ;
     RECT  202.215 67.055 202.497 174.707 ;
     RECT  207.615 70.565 207.897 174.707 ;
     RECT  213.015 71.519 213.297 174.707 ;
     RECT  2.415 174.707 2.505 174.977 ;
     RECT  7.815 174.707 7.905 174.977 ;
     RECT  13.215 174.707 13.305 174.977 ;
     RECT  18.615 174.707 18.705 174.977 ;
     RECT  24.015 174.707 24.105 174.977 ;
     RECT  29.415 174.707 29.505 174.977 ;
     RECT  34.815 174.707 34.905 174.977 ;
     RECT  40.215 174.707 40.305 174.977 ;
     RECT  45.615 174.707 45.705 174.977 ;
     RECT  51.015 174.707 51.105 174.977 ;
     RECT  56.415 174.707 56.505 174.977 ;
     RECT  61.815 174.707 61.905 174.977 ;
     RECT  67.215 174.707 67.305 174.977 ;
     RECT  72.615 174.707 72.705 174.977 ;
     RECT  78.015 174.707 78.105 174.977 ;
     RECT  83.415 174.707 83.505 174.977 ;
     RECT  88.815 174.707 88.905 174.977 ;
     RECT  94.215 174.707 94.305 174.977 ;
     RECT  99.615 174.707 99.705 174.977 ;
     RECT  105.015 174.707 105.105 174.977 ;
     RECT  110.415 174.707 110.505 174.977 ;
     RECT  115.815 174.707 115.905 174.977 ;
     RECT  121.215 174.707 121.305 174.977 ;
     RECT  126.615 174.707 126.705 174.977 ;
     RECT  132.015 174.707 132.105 174.977 ;
     RECT  137.415 174.707 137.505 174.977 ;
     RECT  142.815 174.707 142.905 174.977 ;
     RECT  148.215 174.707 148.305 174.977 ;
     RECT  153.615 174.707 153.705 174.977 ;
     RECT  159.015 174.707 159.105 174.977 ;
     RECT  164.415 174.707 164.505 174.977 ;
     RECT  169.815 174.707 169.905 174.977 ;
     RECT  175.215 174.707 175.305 174.977 ;
     RECT  180.615 174.707 180.705 174.977 ;
     RECT  186.015 174.707 186.105 174.977 ;
     RECT  191.415 174.707 191.505 174.977 ;
     RECT  196.815 174.707 196.905 174.977 ;
     RECT  202.215 174.707 202.305 174.977 ;
     RECT  207.615 174.707 207.705 174.977 ;
     RECT  213.015 174.707 213.105 174.977 ;
    LAYER M4 ;
     RECT  0.06 56.304 0.137 64.968 ;
     RECT  0.06 81.168 0.137 96.456 ;
     RECT  0.06 48.912 0.569 54.984 ;
     RECT  0.137 81.264 0.569 96.456 ;
     RECT  0.137 56.4 1.181 64.968 ;
     RECT  0.569 49.008 1.325 54.984 ;
     RECT  0.569 81.84 1.361 96.456 ;
     RECT  1.325 49.008 2.408 54.888 ;
     RECT  1.181 56.4 2.408 64.872 ;
     RECT  1.361 81.84 2.408 96.36 ;
     RECT  2.408 2.148 2.512 174.972 ;
     RECT  2.512 2.418 2.704 174.702 ;
     RECT  2.704 57.84 2.765 58.728 ;
     RECT  2.704 60.048 2.765 60.648 ;
     RECT  2.704 64.656 2.765 64.68 ;
     RECT  2.704 82.416 2.765 91.992 ;
     RECT  2.765 60.048 2.801 60.36 ;
     RECT  2.765 85.68 2.801 91.992 ;
     RECT  2.704 49.68 2.909 55.848 ;
     RECT  2.909 54.432 2.945 55.848 ;
     RECT  2.801 85.68 2.945 90.936 ;
     RECT  2.765 82.416 2.981 84.6 ;
     RECT  2.801 91.92 3.125 91.992 ;
     RECT  2.801 60.336 3.413 60.36 ;
     RECT  3.125 91.92 3.449 91.944 ;
     RECT  2.981 82.416 3.521 84.36 ;
     RECT  2.704 94.896 3.557 94.92 ;
     RECT  2.704 62.592 3.629 63.336 ;
     RECT  2.704 80.4 3.733 80.424 ;
     RECT  2.909 49.68 3.737 53.352 ;
     RECT  3.521 82.56 3.737 84.36 ;
     RECT  2.765 58.608 3.769 58.728 ;
     RECT  3.629 62.592 3.769 62.616 ;
     RECT  3.733 80.4 3.773 80.952 ;
     RECT  3.737 49.68 3.845 52.776 ;
     RECT  2.704 96.576 3.877 96.6 ;
     RECT  2.945 54.576 3.913 55.848 ;
     RECT  2.945 85.92 3.913 90.936 ;
     RECT  3.877 96.576 3.949 96.792 ;
     RECT  3.769 62.304 4.025 62.616 ;
     RECT  3.913 85.92 4.061 91.752 ;
     RECT  3.769 57.984 4.076 58.728 ;
     RECT  3.913 54.576 4.201 56.424 ;
     RECT  3.949 96.576 4.237 97.32 ;
     RECT  4.117 60.432 4.273 60.456 ;
     RECT  4.165 93.072 4.273 93.096 ;
     RECT  4.076 57.984 4.309 59.112 ;
     RECT  3.737 84.24 4.345 84.36 ;
     RECT  4.273 93.072 4.345 93.624 ;
     RECT  3.845 49.68 4.417 52.44 ;
     RECT  4.201 54.288 4.453 56.424 ;
     RECT  3.769 65.52 4.453 65.544 ;
     RECT  4.345 93.072 4.453 93.816 ;
     RECT  4.237 96.192 4.453 97.32 ;
     RECT  4.309 57.984 4.489 59.208 ;
     RECT  4.273 60.432 4.489 60.648 ;
     RECT  4.453 65.52 4.489 66.216 ;
     RECT  4.489 65.52 4.526 66.696 ;
     RECT  4.526 65.568 4.54 66.696 ;
     RECT  4.54 66.672 4.573 66.696 ;
     RECT  4.417 49.2 4.637 52.44 ;
     RECT  4.489 57.984 4.705 60.648 ;
     RECT  4.025 62.304 4.705 62.568 ;
     RECT  4.637 49.2 4.741 49.704 ;
     RECT  4.741 48.96 4.777 49.704 ;
     RECT  4.061 88.128 4.813 91.752 ;
     RECT  4.705 57.984 4.817 62.568 ;
     RECT  4.453 54.288 4.837 56.664 ;
     RECT  3.773 80.928 4.849 80.952 ;
     RECT  4.813 88.128 4.885 91.896 ;
     RECT  4.453 92.88 4.885 93.816 ;
     RECT  4.345 84.24 4.993 84.888 ;
     RECT  4.061 85.92 4.993 87.096 ;
     RECT  3.737 82.56 5.037 83.208 ;
     RECT  4.993 84.24 5.037 87.096 ;
     RECT  5.037 82.56 5.137 87.096 ;
     RECT  4.885 88.128 5.137 93.816 ;
     RECT  4.453 96.192 5.137 97.56 ;
     RECT  4.817 58.128 5.173 62.568 ;
     RECT  4.201 63.792 5.173 63.816 ;
     RECT  4.54 65.568 5.177 65.592 ;
     RECT  5.173 58.128 5.213 63.816 ;
     RECT  4.237 95.136 5.245 95.16 ;
     RECT  5.137 96.144 5.245 97.56 ;
     RECT  5.137 82.56 5.281 93.816 ;
     RECT  4.837 40.32 5.461 40.344 ;
     RECT  4.777 48.144 5.497 49.704 ;
     RECT  5.461 40.32 5.509 40.872 ;
     RECT  4.837 53.952 5.533 56.664 ;
     RECT  5.497 47.904 5.581 49.704 ;
     RECT  4.637 50.688 5.605 52.44 ;
     RECT  5.533 53.952 5.605 57.096 ;
     RECT  5.281 82.56 5.605 94.008 ;
     RECT  5.245 95.136 5.681 97.56 ;
     RECT  5.681 95.136 5.699 97.512 ;
     RECT  5.581 48.144 5.713 49.704 ;
     RECT  5.605 50.688 5.713 57.096 ;
     RECT  5.509 40.32 5.893 41.4 ;
     RECT  4.849 80.928 5.893 81.096 ;
     RECT  5.213 58.128 6.005 58.968 ;
     RECT  5.605 82.08 6.109 94.008 ;
     RECT  5.893 80.88 6.253 81.096 ;
     RECT  6.109 82.08 6.253 94.104 ;
     RECT  5.213 62.448 6.265 63.816 ;
     RECT  6.265 63.792 6.293 63.816 ;
     RECT  6.236 6.24 6.323 6.264 ;
     RECT  6.253 80.88 6.325 94.104 ;
     RECT  6.245 7.968 6.329 7.992 ;
     RECT  6.325 80.88 6.401 94.152 ;
     RECT  6.005 58.656 6.433 58.968 ;
     RECT  5.213 60.096 6.433 61.128 ;
     RECT  6.401 81.072 6.473 94.152 ;
     RECT  6.433 58.656 6.509 61.128 ;
     RECT  6.473 83.088 6.721 94.152 ;
     RECT  5.699 95.136 6.721 96.744 ;
     RECT  6.541 64.32 6.757 64.344 ;
     RECT  6.037 3.936 6.833 3.96 ;
     RECT  6.853 0.576 6.949 0.6 ;
     RECT  6.949 0.096 6.977 0.6 ;
     RECT  6.901 44.352 7.045 44.376 ;
     RECT  6.977 0.096 7.049 0.168 ;
     RECT  5.713 48.144 7.189 57.096 ;
     RECT  7.049 0.144 7.301 0.168 ;
     RECT  5.893 40.272 7.621 41.4 ;
     RECT  6.997 42.528 7.621 42.552 ;
     RECT  7.621 40.272 7.669 42.552 ;
     RECT  7.045 44.064 7.669 44.376 ;
     RECT  7.189 48.144 7.729 57.288 ;
     RECT  7.141 1.152 7.733 1.176 ;
     RECT  6.757 5.472 7.808 5.496 ;
     RECT  7.669 40.272 7.808 44.376 ;
     RECT  7.729 48.144 7.808 57.672 ;
     RECT  6.509 58.656 7.808 60.12 ;
     RECT  6.509 61.104 7.808 61.128 ;
     RECT  6.265 62.448 7.808 62.808 ;
     RECT  6.757 64.32 7.808 64.632 ;
     RECT  6.973 66.816 7.808 66.84 ;
     RECT  4.501 70.56 7.808 70.584 ;
     RECT  5.605 78.048 7.808 78.072 ;
     RECT  6.473 81.072 7.808 82.008 ;
     RECT  6.721 83.088 7.808 96.744 ;
     RECT  7.808 2.148 7.912 174.972 ;
     RECT  7.912 2.418 8.104 174.702 ;
     RECT  8.104 81.648 8.165 86.328 ;
     RECT  8.104 93.744 8.237 95.448 ;
     RECT  8.104 48.096 8.243 60.12 ;
     RECT  8.104 91.104 8.273 92.088 ;
     RECT  8.104 96.576 8.273 96.6 ;
     RECT  8.104 88.464 8.417 90.024 ;
     RECT  8.104 45.408 8.489 46.728 ;
     RECT  8.237 93.84 8.489 95.448 ;
     RECT  8.165 81.648 8.633 81.96 ;
     RECT  8.165 82.944 8.705 86.328 ;
     RECT  8.489 93.84 8.819 95.4 ;
     RECT  8.705 83.472 8.893 86.328 ;
     RECT  8.819 93.84 8.921 95.064 ;
     RECT  8.921 93.84 8.993 94.92 ;
     RECT  8.243 48.096 9.065 58.056 ;
     RECT  8.993 93.84 9.065 94.344 ;
     RECT  8.104 10.272 9.089 10.728 ;
     RECT  8.273 91.632 9.101 92.088 ;
     RECT  8.243 59.472 9.133 60.12 ;
     RECT  8.104 61.104 9.133 61.128 ;
     RECT  9.089 10.272 9.155 11.448 ;
     RECT  8.104 40.272 9.157 44.376 ;
     RECT  9.155 11.424 9.173 11.448 ;
     RECT  9.065 57.312 9.173 58.056 ;
     RECT  8.633 81.936 9.209 81.96 ;
     RECT  8.417 88.464 9.209 89.784 ;
     RECT  8.104 5.472 9.212 5.496 ;
     RECT  9.133 59.472 9.217 61.128 ;
     RECT  8.104 6.816 9.245 8.232 ;
     RECT  8.893 83.472 9.245 85.224 ;
     RECT  9.245 7.92 9.253 8.232 ;
     RECT  9.212 5.088 9.281 5.496 ;
     RECT  9.281 5.088 9.299 5.112 ;
     RECT  9.065 48.096 9.317 56.328 ;
     RECT  9.209 88.944 9.317 89.784 ;
     RECT  9.157 40.272 9.349 44.424 ;
     RECT  9.173 57.552 9.349 58.056 ;
     RECT  8.104 62.448 9.395 63.288 ;
     RECT  9.245 84.864 9.785 85.224 ;
     RECT  9.155 10.272 10.033 10.296 ;
     RECT  9.349 39.312 10.037 44.424 ;
     RECT  9.317 54.336 10.037 56.328 ;
     RECT  9.349 57.552 10.141 58.296 ;
     RECT  9.065 93.84 10.145 93.864 ;
     RECT  10.141 57.216 10.177 58.296 ;
     RECT  9.217 59.472 10.177 60.12 ;
     RECT  9.245 83.472 10.177 83.496 ;
     RECT  9.317 48.096 10.465 53.256 ;
     RECT  10.037 54.336 10.465 56.04 ;
     RECT  10.465 48.096 10.537 56.04 ;
     RECT  10.556 11.568 10.597 11.592 ;
     RECT  10.597 11.568 10.643 12.216 ;
     RECT  10.177 83.184 10.793 83.496 ;
     RECT  9.253 7.92 10.825 8.712 ;
     RECT  10.033 10.128 10.825 10.296 ;
     RECT  8.489 45.408 10.825 45.96 ;
     RECT  8.104 78.048 10.825 78.072 ;
     RECT  9.785 85.2 10.825 85.224 ;
     RECT  10.177 57.216 10.829 60.12 ;
     RECT  10.645 93.312 10.829 93.336 ;
     RECT  10.748 6.816 10.835 6.84 ;
     RECT  10.825 77.952 10.865 78.072 ;
     RECT  10.825 84.768 10.937 85.224 ;
     RECT  9.565 4.896 11.257 4.92 ;
     RECT  10.825 7.92 11.333 10.296 ;
     RECT  10.537 47.856 11.365 56.04 ;
     RECT  9.101 91.632 11.401 91.656 ;
     RECT  10.829 57.408 11.549 60.12 ;
     RECT  11.257 4.896 11.725 5.736 ;
     RECT  11.549 57.408 11.797 57.912 ;
     RECT  10.643 12.192 12.013 12.216 ;
     RECT  11.333 7.92 12.017 9.576 ;
     RECT  11.797 57.36 12.017 57.912 ;
     RECT  12.017 8.448 12.161 9.576 ;
     RECT  11.725 4.896 12.445 6.024 ;
     RECT  11.365 47.856 12.517 56.328 ;
     RECT  12.445 4.896 12.553 6.312 ;
     RECT  12.553 4.128 12.733 6.312 ;
     RECT  9.395 62.448 12.877 62.472 ;
     RECT  12.013 11.424 13.021 12.216 ;
     RECT  12.733 4.128 13.208 6.888 ;
     RECT  12.161 8.448 13.208 9.528 ;
     RECT  13.021 10.608 13.208 12.216 ;
     RECT  13.057 34.896 13.208 34.92 ;
     RECT  10.037 39.312 13.208 43.08 ;
     RECT  10.037 44.064 13.208 44.424 ;
     RECT  10.825 45.408 13.208 46.056 ;
     RECT  12.517 47.376 13.208 56.328 ;
     RECT  12.017 57.408 13.208 57.912 ;
     RECT  11.549 58.992 13.208 60.12 ;
     RECT  9.217 61.104 13.208 61.128 ;
     RECT  12.877 62.448 13.208 63.096 ;
     RECT  8.104 64.32 13.208 64.344 ;
     RECT  8.104 66.816 13.208 66.84 ;
     RECT  8.104 70.56 13.208 70.584 ;
     RECT  10.865 77.952 13.208 77.976 ;
     RECT  10.793 83.472 13.208 83.496 ;
     RECT  10.937 85.2 13.208 85.224 ;
     RECT  8.893 86.304 13.208 86.328 ;
     RECT  9.317 88.944 13.208 88.968 ;
     RECT  11.401 90.864 13.208 91.656 ;
     RECT  13.208 2.148 13.312 174.972 ;
     RECT  13.312 2.418 13.504 174.702 ;
     RECT  13.504 5.28 13.601 5.304 ;
     RECT  13.504 33.84 13.667 34.92 ;
     RECT  13.504 37.008 13.681 37.032 ;
     RECT  13.504 4.128 13.745 4.152 ;
     RECT  13.504 38.496 13.781 43.08 ;
     RECT  13.667 33.84 13.907 34.776 ;
     RECT  13.504 47.28 14.213 57 ;
     RECT  13.504 62.448 14.291 63.096 ;
     RECT  13.504 65.664 14.332 65.688 ;
     RECT  13.504 6.816 14.533 9.384 ;
     RECT  13.504 66.816 14.605 66.84 ;
     RECT  13.907 34.752 14.645 34.776 ;
     RECT  13.504 69.984 14.677 71.4 ;
     RECT  13.504 81.984 14.713 82.008 ;
     RECT  13.504 83.472 14.713 83.496 ;
     RECT  13.504 86.304 14.713 86.328 ;
     RECT  14.533 6.72 14.741 9.384 ;
     RECT  13.504 10.464 14.741 12.072 ;
     RECT  13.504 2.88 14.749 2.904 ;
     RECT  14.749 2.688 14.773 2.904 ;
     RECT  14.773 2.208 14.785 2.904 ;
     RECT  13.504 77.136 14.785 77.976 ;
     RECT  14.677 69.36 14.789 71.4 ;
     RECT  14.789 69.36 14.821 70.056 ;
     RECT  13.504 85.2 14.821 85.224 ;
     RECT  14.713 86.304 14.821 86.76 ;
     RECT  14.713 81.984 14.861 83.496 ;
     RECT  14.821 68.928 14.867 70.056 ;
     RECT  14.741 6.72 14.897 12.072 ;
     RECT  14.867 68.928 14.905 68.952 ;
     RECT  14.924 74.832 14.965 74.856 ;
     RECT  14.785 77.136 14.969 78.648 ;
     RECT  14.789 71.376 15.113 71.4 ;
     RECT  13.504 58.992 15.177 61.128 ;
     RECT  14.897 11.232 15.289 12.072 ;
     RECT  14.965 75.936 15.293 75.96 ;
     RECT  14.605 66.48 15.397 66.84 ;
     RECT  15.361 80.592 15.433 80.616 ;
     RECT  14.861 81.984 15.433 83.352 ;
     RECT  15.289 11.232 15.473 12.216 ;
     RECT  14.965 74.496 15.473 74.856 ;
     RECT  14.867 69.984 15.509 70.056 ;
     RECT  15.5 36.096 15.587 36.12 ;
     RECT  14.785 2.208 15.596 3.576 ;
     RECT  14.897 6.72 15.637 9.96 ;
     RECT  15.596 2.208 15.72 4.296 ;
     RECT  15.473 74.688 15.793 74.856 ;
     RECT  15.637 6.048 15.829 9.96 ;
     RECT  15.72 2.208 15.868 4.488 ;
     RECT  14.969 77.52 15.905 78.648 ;
     RECT  15.829 5.664 15.925 9.96 ;
     RECT  15.361 0.72 15.937 0.744 ;
     RECT  14.713 92.976 15.937 93 ;
     RECT  15.177 58.992 15.965 60.12 ;
     RECT  15.433 80.592 16.009 83.352 ;
     RECT  14.213 47.28 16.021 56.04 ;
     RECT  15.925 5.664 16.045 10.152 ;
     RECT  15.965 58.128 16.049 60.12 ;
     RECT  16.021 47.088 16.081 56.04 ;
     RECT  15.541 71.712 16.117 71.736 ;
     RECT  15.793 74.688 16.225 74.952 ;
     RECT  16.213 4.56 16.261 4.584 ;
     RECT  16.045 5.616 16.261 10.152 ;
     RECT  16.117 71.712 16.261 72.408 ;
     RECT  13.504 64.32 16.333 64.344 ;
     RECT  16.225 74.688 16.333 75.192 ;
     RECT  15.473 11.328 16.409 12.216 ;
     RECT  16.333 74.688 16.445 75.864 ;
     RECT  15.177 61.104 16.453 61.128 ;
     RECT  14.291 62.448 16.477 62.472 ;
     RECT  14.821 85.152 16.477 86.76 ;
     RECT  13.504 90.864 16.477 91.656 ;
     RECT  15.937 92.784 16.477 93 ;
     RECT  15.905 77.52 16.513 78.168 ;
     RECT  16.081 47.088 16.517 57 ;
     RECT  16.261 4.56 16.553 10.152 ;
     RECT  16.553 4.608 16.733 10.152 ;
     RECT  15.937 0.576 16.741 0.744 ;
     RECT  16.733 4.608 16.741 9 ;
     RECT  13.781 39.312 16.741 43.08 ;
     RECT  13.504 44.064 16.741 44.424 ;
     RECT  13.504 45.408 16.805 46.056 ;
     RECT  16.445 74.928 16.805 75.864 ;
     RECT  16.805 45.504 16.835 46.056 ;
     RECT  15.509 69.984 16.837 70.008 ;
     RECT  16.477 62.256 16.873 62.472 ;
     RECT  16.049 58.992 16.883 60.12 ;
     RECT  15.868 2.208 16.979 3.576 ;
     RECT  16.733 10.128 16.981 10.152 ;
     RECT  15.397 66.096 17.053 66.84 ;
     RECT  16.009 80.352 17.053 83.352 ;
     RECT  16.477 90.864 17.053 93.24 ;
     RECT  15.937 94.416 17.053 94.44 ;
     RECT  16.981 10.128 17.057 10.296 ;
     RECT  16.517 47.088 17.125 56.472 ;
     RECT  16.333 64.32 17.125 64.728 ;
     RECT  16.741 0.096 17.189 0.744 ;
     RECT  16.883 58.992 17.273 59.016 ;
     RECT  16.837 69.984 17.305 70.584 ;
     RECT  16.261 71.712 17.305 72.696 ;
     RECT  16.981 57.84 17.324 57.864 ;
     RECT  17.053 65.712 17.341 67.032 ;
     RECT  16.549 68.112 17.341 68.136 ;
     RECT  17.305 69.984 17.341 72.696 ;
     RECT  16.873 62.16 17.365 62.472 ;
     RECT  17.125 63.84 17.365 64.728 ;
     RECT  17.324 57.84 17.411 58.68 ;
     RECT  16.979 2.208 17.459 2.904 ;
     RECT  17.125 46.56 17.521 56.472 ;
     RECT  17.341 69.984 17.521 73.32 ;
     RECT  17.057 10.272 17.557 10.296 ;
     RECT  16.409 11.328 17.557 11.784 ;
     RECT  17.053 80.352 17.593 83.592 ;
     RECT  17.189 0.096 17.605 1.176 ;
     RECT  17.459 2.208 17.605 2.808 ;
     RECT  16.741 4.608 17.605 6.312 ;
     RECT  13.504 88.944 17.629 89.736 ;
     RECT  17.365 62.16 17.665 64.728 ;
     RECT  17.341 65.712 17.665 68.136 ;
     RECT  16.513 77.28 17.701 78.168 ;
     RECT  16.883 60.096 17.845 60.12 ;
     RECT  16.453 61.104 17.845 61.176 ;
     RECT  16.741 39.312 17.893 44.424 ;
     RECT  16.835 45.504 17.893 45.576 ;
     RECT  17.521 69.984 17.953 73.368 ;
     RECT  17.845 60.096 17.989 61.176 ;
     RECT  17.665 62.16 17.989 68.136 ;
     RECT  16.805 74.928 17.989 75.72 ;
     RECT  17.605 0.096 18.101 2.808 ;
     RECT  17.989 60.096 18.133 68.136 ;
     RECT  17.629 88.656 18.169 89.736 ;
     RECT  17.053 90.864 18.169 94.44 ;
     RECT  17.953 69.216 18.205 73.368 ;
     RECT  16.477 84.912 18.205 87.576 ;
     RECT  17.605 4.416 18.229 6.312 ;
     RECT  16.741 7.392 18.229 9 ;
     RECT  17.557 10.272 18.229 11.784 ;
     RECT  18.101 0.144 18.317 2.808 ;
     RECT  18.229 4.416 18.325 11.784 ;
     RECT  17.893 39.312 18.325 45.576 ;
     RECT  17.521 46.56 18.325 56.52 ;
     RECT  18.325 4.224 18.373 11.784 ;
     RECT  18.317 1.728 18.421 2.808 ;
     RECT  18.373 4.128 18.421 11.784 ;
     RECT  18.133 59.712 18.421 68.136 ;
     RECT  18.325 39.312 18.565 56.52 ;
     RECT  17.411 57.84 18.565 57.864 ;
     RECT  17.701 77.28 18.565 78.696 ;
     RECT  18.421 1.728 18.608 11.784 ;
     RECT  18.565 39.312 18.608 57.864 ;
     RECT  18.421 59.712 18.608 68.232 ;
     RECT  18.205 69.216 18.608 73.512 ;
     RECT  17.989 74.592 18.608 75.912 ;
     RECT  18.565 77.04 18.608 78.696 ;
     RECT  17.593 79.68 18.608 83.592 ;
     RECT  18.205 84.912 18.608 87.624 ;
     RECT  18.169 88.656 18.608 94.44 ;
     RECT  18.317 0.144 18.611 0.6 ;
     RECT  18.608 1.728 18.712 174.972 ;
     RECT  18.611 0.192 18.803 0.6 ;
     RECT  18.712 1.728 18.904 174.702 ;
     RECT  18.803 0.576 19.289 0.6 ;
     RECT  18.904 39.312 19.541 70.344 ;
     RECT  18.904 1.728 19.577 9.384 ;
     RECT  18.904 71.376 19.897 83.592 ;
     RECT  18.904 84.72 19.897 87.624 ;
     RECT  18.904 88.656 19.897 94.536 ;
     RECT  19.577 1.776 19.973 9.384 ;
     RECT  18.904 11.712 20.005 11.784 ;
     RECT  20.005 11.424 20.045 11.784 ;
     RECT  19.541 57.552 20.077 70.344 ;
     RECT  19.897 71.376 20.077 83.688 ;
     RECT  19.973 1.824 20.387 9.384 ;
     RECT  20.387 8.208 20.396 9.384 ;
     RECT  20.077 57.552 20.509 83.688 ;
     RECT  19.897 84.72 20.509 94.536 ;
     RECT  20.396 8.208 20.513 10.344 ;
     RECT  20.513 8.448 20.533 10.344 ;
     RECT  19.541 39.312 20.545 56.472 ;
     RECT  20.509 57.552 20.545 94.536 ;
     RECT  20.045 11.424 20.579 11.448 ;
     RECT  20.545 39.312 20.585 94.536 ;
     RECT  20.387 1.824 20.621 6.888 ;
     RECT  20.621 2.64 20.657 6.888 ;
     RECT  20.657 2.832 20.873 6.888 ;
     RECT  20.533 8.448 20.909 10.392 ;
     RECT  20.909 9.36 21.107 10.392 ;
     RECT  20.873 2.832 21.155 6.84 ;
     RECT  21.107 9.696 21.197 10.392 ;
     RECT  21.155 2.832 21.203 4.008 ;
     RECT  21.155 5.136 21.241 6.84 ;
     RECT  21.203 3.936 21.313 4.008 ;
     RECT  21.197 9.696 21.341 9.72 ;
     RECT  21.313 3.936 21.377 3.96 ;
     RECT  21.241 5.424 21.377 6.84 ;
     RECT  21.377 6.24 21.593 6.84 ;
     RECT  20.585 39.312 21.661 73.992 ;
     RECT  20.585 75.12 21.661 94.536 ;
     RECT  21.593 6.24 21.953 6.264 ;
     RECT  21.203 2.832 22.385 2.856 ;
     RECT  21.661 39.312 22.968 94.536 ;
     RECT  22.968 39.312 24.008 124.488 ;
     RECT  24.008 2.148 24.112 124.488 ;
     RECT  24.008 126.888 24.112 174.972 ;
     RECT  24.112 126.888 24.2 174.702 ;
     RECT  24.112 2.418 24.304 124.488 ;
     RECT  24.2 126.618 24.304 174.702 ;
     RECT  24.304 39.312 29.408 124.488 ;
     RECT  29.408 2.148 29.512 124.488 ;
     RECT  29.408 126.888 29.512 174.972 ;
     RECT  29.512 126.888 29.6 174.702 ;
     RECT  29.512 2.418 29.704 124.488 ;
     RECT  29.6 126.618 29.704 174.702 ;
     RECT  29.704 39.312 34.808 124.488 ;
     RECT  34.808 2.148 34.912 124.488 ;
     RECT  34.808 126.888 34.912 174.972 ;
     RECT  34.912 126.888 35 174.702 ;
     RECT  34.912 2.418 35.104 124.488 ;
     RECT  35 126.618 35.104 174.702 ;
     RECT  35.104 39.312 40.208 124.488 ;
     RECT  40.208 2.148 40.312 124.488 ;
     RECT  40.208 126.888 40.312 174.972 ;
     RECT  40.312 126.888 40.4 174.702 ;
     RECT  40.312 2.418 40.504 124.488 ;
     RECT  40.4 126.618 40.504 174.702 ;
     RECT  40.504 39.312 45.608 124.488 ;
     RECT  45.608 2.148 45.712 124.488 ;
     RECT  45.608 126.888 45.712 174.972 ;
     RECT  45.712 126.888 45.8 174.702 ;
     RECT  45.712 2.418 45.904 124.488 ;
     RECT  45.8 126.618 45.904 174.702 ;
     RECT  45.904 39.312 51.008 124.488 ;
     RECT  51.008 2.148 51.112 124.488 ;
     RECT  51.008 126.888 51.112 174.972 ;
     RECT  51.112 126.888 51.2 174.702 ;
     RECT  51.112 2.418 51.304 124.488 ;
     RECT  51.2 126.618 51.304 174.702 ;
     RECT  51.304 39.312 56.408 124.488 ;
     RECT  56.408 2.148 56.512 124.488 ;
     RECT  56.408 126.888 56.512 174.972 ;
     RECT  56.512 126.888 56.6 174.702 ;
     RECT  56.512 2.418 56.704 124.488 ;
     RECT  56.6 126.618 56.704 174.702 ;
     RECT  56.704 39.312 61.808 124.488 ;
     RECT  61.808 2.148 61.912 124.488 ;
     RECT  61.808 126.888 61.912 174.972 ;
     RECT  61.912 126.888 62 174.702 ;
     RECT  61.912 2.418 62.104 124.488 ;
     RECT  62 126.618 62.104 174.702 ;
     RECT  62.104 39.312 67.208 124.488 ;
     RECT  67.208 2.148 67.312 124.488 ;
     RECT  67.208 126.888 67.312 174.972 ;
     RECT  67.312 126.888 67.4 174.702 ;
     RECT  67.312 2.418 67.504 124.488 ;
     RECT  67.4 126.618 67.504 174.702 ;
     RECT  67.504 39.312 72.608 124.488 ;
     RECT  72.608 2.148 72.712 124.488 ;
     RECT  72.608 126.888 72.712 174.972 ;
     RECT  72.712 126.888 72.8 174.702 ;
     RECT  72.712 2.418 72.904 124.488 ;
     RECT  72.8 126.618 72.904 174.702 ;
     RECT  72.904 39.312 78.008 124.488 ;
     RECT  78.008 2.148 78.112 124.488 ;
     RECT  78.008 126.888 78.112 174.972 ;
     RECT  78.112 126.888 78.2 174.702 ;
     RECT  78.112 2.418 78.304 124.488 ;
     RECT  78.2 126.618 78.304 174.702 ;
     RECT  78.304 39.312 83.269 124.488 ;
     RECT  83.269 39.216 83.408 124.488 ;
     RECT  83.408 2.148 83.512 124.488 ;
     RECT  83.408 126.888 83.512 174.972 ;
     RECT  83.512 126.888 83.6 174.702 ;
     RECT  83.512 2.418 83.704 124.488 ;
     RECT  83.6 126.618 83.704 174.702 ;
     RECT  83.704 39.216 88.808 124.488 ;
     RECT  88.808 2.148 88.912 124.488 ;
     RECT  88.808 126.888 88.912 174.972 ;
     RECT  88.912 126.888 89 174.702 ;
     RECT  88.912 2.418 89.104 124.488 ;
     RECT  89 126.618 89.104 174.702 ;
     RECT  89.104 39.216 94.208 124.488 ;
     RECT  94.208 2.148 94.312 124.488 ;
     RECT  94.208 126.888 94.312 174.972 ;
     RECT  94.312 126.888 94.4 174.702 ;
     RECT  94.312 2.418 94.504 124.488 ;
     RECT  94.4 126.618 94.504 174.702 ;
     RECT  94.504 39.216 99.608 124.488 ;
     RECT  99.608 2.148 99.712 124.488 ;
     RECT  99.608 126.888 99.712 174.972 ;
     RECT  99.712 126.888 99.8 174.702 ;
     RECT  99.712 2.418 99.904 124.488 ;
     RECT  99.8 126.618 99.904 174.702 ;
     RECT  99.904 39.216 105.008 124.488 ;
     RECT  105.008 2.148 105.112 124.488 ;
     RECT  105.008 126.888 105.112 174.972 ;
     RECT  105.112 126.888 105.2 174.702 ;
     RECT  105.112 2.418 105.304 124.488 ;
     RECT  105.2 126.618 105.304 174.702 ;
     RECT  105.304 39.216 108.209 124.488 ;
     RECT  108.209 39.264 109.285 124.488 ;
     RECT  109.285 39.216 110.408 124.488 ;
     RECT  110.408 2.148 110.512 124.488 ;
     RECT  110.408 126.888 110.512 174.972 ;
     RECT  110.512 126.888 110.6 174.702 ;
     RECT  110.512 2.418 110.704 124.488 ;
     RECT  110.6 126.618 110.704 174.702 ;
     RECT  110.704 39.216 115.808 124.488 ;
     RECT  115.808 2.148 115.912 124.488 ;
     RECT  115.808 126.888 115.912 174.972 ;
     RECT  115.912 126.888 116 174.702 ;
     RECT  115.912 2.418 116.104 124.488 ;
     RECT  116 126.618 116.104 174.702 ;
     RECT  116.104 39.216 121.208 124.488 ;
     RECT  121.208 2.148 121.312 124.488 ;
     RECT  121.208 126.888 121.312 174.972 ;
     RECT  121.312 126.888 121.4 174.702 ;
     RECT  121.312 2.418 121.504 124.488 ;
     RECT  121.4 126.618 121.504 174.702 ;
     RECT  126.332 33.984 126.608 34.008 ;
     RECT  126.373 34.992 126.608 35.016 ;
     RECT  121.504 39.216 126.608 124.488 ;
     RECT  126.608 2.148 126.712 124.488 ;
     RECT  126.608 126.888 126.712 174.972 ;
     RECT  126.712 126.888 126.8 174.702 ;
     RECT  126.712 2.418 126.904 124.488 ;
     RECT  126.8 126.618 126.904 174.702 ;
     RECT  126.904 35.136 132.008 35.16 ;
     RECT  126.904 39.216 132.008 124.488 ;
     RECT  132.008 2.148 132.112 124.488 ;
     RECT  132.008 126.888 132.112 174.972 ;
     RECT  132.112 126.888 132.2 174.702 ;
     RECT  132.112 2.418 132.304 124.488 ;
     RECT  132.2 126.618 132.304 174.702 ;
     RECT  132.304 35.136 137.408 35.16 ;
     RECT  132.304 39.216 137.408 124.488 ;
     RECT  137.408 2.148 137.512 124.488 ;
     RECT  137.408 126.888 137.512 174.972 ;
     RECT  137.512 126.888 137.6 174.702 ;
     RECT  137.512 2.418 137.704 124.488 ;
     RECT  137.6 126.618 137.704 174.702 ;
     RECT  137.704 35.136 140.069 35.16 ;
     RECT  140.749 35.232 142.808 35.256 ;
     RECT  137.704 39.216 142.808 124.488 ;
     RECT  142.808 2.148 142.912 124.488 ;
     RECT  142.808 126.888 142.912 174.972 ;
     RECT  142.912 126.888 143 174.702 ;
     RECT  142.912 2.418 143.104 124.488 ;
     RECT  143 126.618 143.104 174.702 ;
     RECT  143.104 35.136 148.208 35.16 ;
     RECT  143.104 39.216 148.208 124.488 ;
     RECT  148.208 2.148 148.312 124.488 ;
     RECT  148.208 126.888 148.312 174.972 ;
     RECT  148.312 126.888 148.4 174.702 ;
     RECT  148.312 2.418 148.504 124.488 ;
     RECT  148.4 126.618 148.504 174.702 ;
     RECT  148.504 35.136 153.608 35.16 ;
     RECT  148.504 39.216 153.608 124.488 ;
     RECT  153.608 2.148 153.712 124.488 ;
     RECT  153.608 126.888 153.712 174.972 ;
     RECT  153.712 126.888 153.8 174.702 ;
     RECT  153.712 2.418 153.904 124.488 ;
     RECT  153.8 126.618 153.904 174.702 ;
     RECT  153.904 39.216 154.163 124.488 ;
     RECT  153.904 35.136 159.008 35.16 ;
     RECT  154.163 39.216 159.008 42.072 ;
     RECT  154.163 43.056 159.008 124.488 ;
     RECT  159.008 2.148 159.112 124.488 ;
     RECT  159.008 126.888 159.112 174.972 ;
     RECT  159.112 126.888 159.2 174.702 ;
     RECT  159.112 2.418 159.304 124.488 ;
     RECT  159.2 126.618 159.304 174.702 ;
     RECT  159.304 35.136 164.408 35.16 ;
     RECT  159.304 39.216 164.408 42.072 ;
     RECT  159.304 43.056 164.408 124.488 ;
     RECT  164.408 2.148 164.512 124.488 ;
     RECT  164.408 126.888 164.512 174.972 ;
     RECT  164.512 126.888 164.6 174.702 ;
     RECT  164.512 2.418 164.704 124.488 ;
     RECT  164.6 126.618 164.704 174.702 ;
     RECT  164.704 35.136 169.808 35.16 ;
     RECT  164.704 39.216 169.808 42.072 ;
     RECT  164.704 43.056 169.808 124.488 ;
     RECT  169.808 2.148 169.912 124.488 ;
     RECT  169.808 126.888 169.912 174.972 ;
     RECT  169.912 126.888 170 174.702 ;
     RECT  169.912 2.418 170.104 124.488 ;
     RECT  170 126.618 170.104 174.702 ;
     RECT  170.104 35.136 175.208 35.16 ;
     RECT  170.104 39.216 175.208 42.072 ;
     RECT  170.104 43.056 175.208 124.488 ;
     RECT  175.208 2.148 175.312 124.488 ;
     RECT  175.208 126.888 175.312 174.972 ;
     RECT  175.312 126.888 175.4 174.702 ;
     RECT  175.312 2.418 175.504 124.488 ;
     RECT  175.4 126.618 175.504 174.702 ;
     RECT  175.504 35.136 180.608 35.16 ;
     RECT  175.504 39.216 180.608 42.072 ;
     RECT  175.504 43.056 180.608 124.488 ;
     RECT  180.608 2.148 180.712 124.488 ;
     RECT  180.608 126.888 180.712 174.972 ;
     RECT  180.712 126.888 180.8 174.702 ;
     RECT  180.712 2.418 180.904 124.488 ;
     RECT  180.8 126.618 180.904 174.702 ;
     RECT  180.904 35.136 186.008 35.16 ;
     RECT  180.904 39.216 186.008 42.072 ;
     RECT  180.904 43.056 186.008 124.488 ;
     RECT  186.008 2.148 186.112 124.488 ;
     RECT  186.008 126.888 186.112 174.972 ;
     RECT  186.112 126.888 186.2 174.702 ;
     RECT  186.112 2.418 186.304 124.488 ;
     RECT  186.2 126.618 186.304 174.702 ;
     RECT  186.304 35.136 191.408 35.16 ;
     RECT  186.304 39.216 191.408 42.072 ;
     RECT  186.304 43.056 191.408 124.488 ;
     RECT  191.408 2.148 191.512 124.488 ;
     RECT  191.408 126.888 191.512 174.972 ;
     RECT  191.512 126.888 191.6 174.702 ;
     RECT  191.512 2.418 191.704 124.488 ;
     RECT  191.6 126.618 191.704 174.702 ;
     RECT  191.704 35.136 196.808 35.16 ;
     RECT  191.704 39.216 196.808 42.072 ;
     RECT  191.704 43.056 196.808 124.488 ;
     RECT  196.808 2.148 196.912 124.488 ;
     RECT  196.808 126.888 196.912 174.972 ;
     RECT  196.912 126.888 197 174.702 ;
     RECT  196.912 2.418 197.104 124.488 ;
     RECT  197 126.618 197.104 174.702 ;
     RECT  197.104 43.056 197.568 124.488 ;
     RECT  197.568 43.056 197.777 94.68 ;
     RECT  197.777 92.304 198.46 94.68 ;
     RECT  197.104 39.216 198.659 42.072 ;
     RECT  197.777 75.888 198.965 91.272 ;
     RECT  198.965 85.008 199.001 85.608 ;
     RECT  197.777 43.056 199.505 70.632 ;
     RECT  197.777 72.912 199.505 74.76 ;
     RECT  198.965 76.848 199.505 83.976 ;
     RECT  199.001 85.008 199.505 85.032 ;
     RECT  198.965 86.64 199.505 86.664 ;
     RECT  198.965 88.464 199.505 88.488 ;
     RECT  199.505 43.056 199.523 69.096 ;
     RECT  199.505 72.912 199.541 74.52 ;
     RECT  199.505 76.848 199.541 77.448 ;
     RECT  199.505 80.4 199.541 83.208 ;
     RECT  199.541 77.424 199.577 77.448 ;
     RECT  198.659 40.848 199.667 42.072 ;
     RECT  199.541 73.68 199.721 74.52 ;
     RECT  199.541 82.608 199.793 82.728 ;
     RECT  199.505 70.608 199.865 70.632 ;
     RECT  199.793 82.608 199.901 82.632 ;
     RECT  199.541 80.4 199.945 81.384 ;
     RECT  199.721 73.68 199.973 73.704 ;
     RECT  199.945 80.592 199.973 81.384 ;
     RECT  199.523 43.296 200.009 69.096 ;
     RECT  199.973 81.36 200.009 81.384 ;
     RECT  198.46 92.304 200.009 94.44 ;
     RECT  200.009 92.4 200.045 92.424 ;
     RECT  200.009 94.32 200.045 94.44 ;
     RECT  198.965 90.24 200.081 91.176 ;
     RECT  200.045 94.32 200.081 94.344 ;
     RECT  200.009 43.296 200.099 68.328 ;
     RECT  200.099 44.976 200.117 68.328 ;
     RECT  200.117 44.976 200.153 68.232 ;
     RECT  200.153 44.976 200.189 66.984 ;
     RECT  200.153 68.016 200.189 68.232 ;
     RECT  200.189 68.16 200.261 68.232 ;
     RECT  200.189 44.976 200.333 66.888 ;
     RECT  199.667 41.376 200.387 42.072 ;
     RECT  200.333 44.976 200.549 62.088 ;
     RECT  200.333 63.264 200.585 66.888 ;
     RECT  200.585 63.264 200.657 63.288 ;
     RECT  197.104 35.136 200.675 35.16 ;
     RECT  200.585 64.464 200.675 66.888 ;
     RECT  200.387 41.424 200.723 42.072 ;
     RECT  200.099 43.296 200.729 43.896 ;
     RECT  200.549 56.304 200.809 62.088 ;
     RECT  200.549 44.976 200.819 54.936 ;
     RECT  200.809 56.304 200.837 56.616 ;
     RECT  198.659 39.216 200.915 39.864 ;
     RECT  200.723 41.424 200.963 41.448 ;
     RECT  200.819 44.976 201.011 45.288 ;
     RECT  200.819 46.608 201.155 54.936 ;
     RECT  201.011 45.264 201.203 45.288 ;
     RECT  200.809 57.84 201.233 62.088 ;
     RECT  201.157 70.128 201.241 70.152 ;
     RECT  200.261 68.16 201.445 68.184 ;
     RECT  200.675 64.944 201.637 66.888 ;
     RECT  200.915 39.264 202.208 39.864 ;
     RECT  200.729 43.872 202.208 43.896 ;
     RECT  201.155 46.608 202.208 48.792 ;
     RECT  201.155 49.872 202.208 54.936 ;
     RECT  200.837 56.592 202.208 56.616 ;
     RECT  201.233 57.84 202.208 61.944 ;
     RECT  201.589 63.024 202.208 63.048 ;
     RECT  201.637 64.944 202.208 67.08 ;
     RECT  201.445 68.16 202.208 69.048 ;
     RECT  199.933 84.96 202.208 84.984 ;
     RECT  202.208 2.148 202.312 174.972 ;
     RECT  202.312 2.418 202.504 174.702 ;
     RECT  202.504 49.872 202.565 55.032 ;
     RECT  202.504 57.84 202.565 58.776 ;
     RECT  202.504 60.048 202.601 60.072 ;
     RECT  202.504 65.28 202.961 66.888 ;
     RECT  202.504 46.608 203.249 47.16 ;
     RECT  202.565 50.064 204.653 55.032 ;
     RECT  204.289 56.544 204.833 56.568 ;
     RECT  202.504 63.024 205.873 63.048 ;
     RECT  202.961 66.768 206.005 66.888 ;
     RECT  202.504 68.16 206.005 69.048 ;
     RECT  204.653 50.064 206.051 51.672 ;
     RECT  206.005 66.768 206.129 69.048 ;
     RECT  202.504 61.92 206.237 61.944 ;
     RECT  202.565 57.84 206.341 57.864 ;
     RECT  205.405 59.472 206.341 59.496 ;
     RECT  202.961 65.28 206.341 65.4 ;
     RECT  206.341 65.28 206.381 65.448 ;
     RECT  206.341 57.84 206.485 59.496 ;
     RECT  206.485 57.84 206.525 59.592 ;
     RECT  204.653 52.8 206.845 55.032 ;
     RECT  205.873 63.024 207.277 63.24 ;
     RECT  207.277 63.024 207.445 63.288 ;
     RECT  206.381 65.376 207.493 65.448 ;
     RECT  206.129 66.768 207.493 68.952 ;
     RECT  203.249 47.136 207.608 47.16 ;
     RECT  202.504 48.144 207.608 48.168 ;
     RECT  206.051 50.064 207.608 50.616 ;
     RECT  206.051 51.648 207.608 51.672 ;
     RECT  206.845 52.8 207.608 55.32 ;
     RECT  206.821 56.544 207.608 56.568 ;
     RECT  206.525 57.84 207.608 58.152 ;
     RECT  206.525 59.568 207.608 59.592 ;
     RECT  206.413 61.344 207.608 61.368 ;
     RECT  207.445 62.736 207.608 63.288 ;
     RECT  207.493 65.376 207.608 68.952 ;
     RECT  207.313 70.368 207.608 70.392 ;
     RECT  207.608 2.148 207.712 174.972 ;
     RECT  207.712 2.418 207.904 174.702 ;
     RECT  207.904 63.168 208.073 70.392 ;
     RECT  207.904 57.84 208.109 59.592 ;
     RECT  207.904 61.344 208.253 61.368 ;
     RECT  208.073 66.672 208.499 70.104 ;
     RECT  208.499 66.672 208.739 67.704 ;
     RECT  208.109 57.84 208.897 59.448 ;
     RECT  208.897 56.88 208.937 59.448 ;
     RECT  208.937 56.88 208.969 58.728 ;
     RECT  208.969 56.832 209.113 58.728 ;
     RECT  208.073 63.168 209.113 65.448 ;
     RECT  208.739 66.672 209.113 67.128 ;
     RECT  207.904 55.008 209.269 55.32 ;
     RECT  209.113 56.448 209.269 58.728 ;
     RECT  207.904 52.8 209.333 53.88 ;
     RECT  207.904 51.648 209.459 51.672 ;
     RECT  209.231 60.384 209.507 60.408 ;
     RECT  209.333 53.856 209.689 53.88 ;
     RECT  209.269 55.008 209.689 58.728 ;
     RECT  208.499 69.168 209.689 70.104 ;
     RECT  209.113 63.168 209.747 67.128 ;
     RECT  209.689 68.4 209.833 70.104 ;
     RECT  209.747 64.992 209.873 67.128 ;
     RECT  209.747 63.168 209.977 63.816 ;
     RECT  209.833 68.352 209.977 70.104 ;
     RECT  209.873 64.992 210.053 66.792 ;
     RECT  209.689 53.856 210.085 58.728 ;
     RECT  210.085 53.856 210.125 59.208 ;
     RECT  210.125 53.856 210.485 57.864 ;
     RECT  210.125 59.04 210.773 59.208 ;
     RECT  207.904 50.352 210.845 50.616 ;
     RECT  209.977 68.352 210.877 70.296 ;
     RECT  210.485 55.008 210.953 57.864 ;
     RECT  210.053 66.288 210.953 66.792 ;
     RECT  210.877 67.776 211.097 70.296 ;
     RECT  210.953 55.008 211.529 57.048 ;
     RECT  210.053 64.992 211.529 65.304 ;
     RECT  209.977 62.64 211.601 63.816 ;
     RECT  211.601 63.072 211.705 63.816 ;
     RECT  210.953 66.48 211.741 66.792 ;
     RECT  211.097 67.776 211.741 70.104 ;
     RECT  211.705 63.072 211.781 64.44 ;
     RECT  210.773 59.04 211.813 59.064 ;
     RECT  210.485 53.856 211.849 53.88 ;
     RECT  211.813 59.04 211.853 59.832 ;
     RECT  211.529 55.872 211.957 57.048 ;
     RECT  211.853 59.808 211.993 59.832 ;
     RECT  211.993 59.808 212.005 60.408 ;
     RECT  210.337 61.584 212.005 61.608 ;
     RECT  211.957 55.872 212.137 57.336 ;
     RECT  211.741 66.48 212.209 70.104 ;
     RECT  212.209 66.192 212.245 70.104 ;
     RECT  212.137 55.872 212.396 57.384 ;
     RECT  211.993 58.656 212.396 58.68 ;
     RECT  212.245 66.192 212.808 70.536 ;
     RECT  211.781 63.36 212.929 64.44 ;
     RECT  211.849 53.856 212.965 54.744 ;
     RECT  212.396 55.872 212.965 58.68 ;
     RECT  207.904 47.136 213.008 47.16 ;
     RECT  210.845 50.352 213.008 50.376 ;
     RECT  209.333 52.8 213.008 52.824 ;
     RECT  212.965 53.856 213.008 58.68 ;
     RECT  212.005 59.808 213.008 61.608 ;
     RECT  212.929 63.264 213.008 64.44 ;
     RECT  212.808 66.096 213.008 70.536 ;
     RECT  213.008 2.148 213.112 174.972 ;
     RECT  213.112 2.418 213.304 174.702 ;
     RECT  213.304 54.72 213.437 55.272 ;
     RECT  213.304 56.496 213.653 56.52 ;
     RECT  213.437 55.152 214.049 55.272 ;
     RECT  213.304 59.808 214.157 59.832 ;
     RECT  213.304 63.216 214.265 70.344 ;
     RECT  214.265 69.456 214.337 70.344 ;
     RECT  214.049 55.152 214.409 55.176 ;
     RECT  214.513 62.112 214.549 62.136 ;
     RECT  214.549 62.112 214.657 62.232 ;
     RECT  214.265 63.216 214.657 68.088 ;
     RECT  214.657 62.112 214.873 68.088 ;
     RECT  214.337 69.456 215.093 69.528 ;
     RECT  215.053 59.472 215.165 59.496 ;
     RECT  215.093 69.456 215.413 69.48 ;
     RECT  214.873 61.776 215.449 68.088 ;
     RECT  215.449 61.776 215.521 68.28 ;
     RECT  215.521 61.728 215.737 68.28 ;
     RECT  215.413 69.408 215.737 69.48 ;
     RECT  215.485 56.928 215.881 56.952 ;
     RECT  215.737 61.728 216.061 69.48 ;
     RECT  215.809 59.664 216.065 60.36 ;
     RECT  215.881 56.928 216.277 57.816 ;
     RECT  216.061 61.728 216.313 69.576 ;
     RECT  216.277 56.928 216.425 58.632 ;
     RECT  216.313 61.056 216.641 69.576 ;
     RECT  216.853 55.344 217.033 55.368 ;
     RECT  216.425 56.928 217.033 56.952 ;
     RECT  216.425 58.608 217.177 58.632 ;
     RECT  216.065 59.664 217.177 60.072 ;
     RECT  217.033 55.344 217.465 56.952 ;
     RECT  217.465 55.344 217.609 57.384 ;
     RECT  216.641 61.728 217.717 64.392 ;
     RECT  216.641 65.376 217.717 69.576 ;
     RECT  217.609 54.672 217.753 57.384 ;
     RECT  217.177 58.608 217.753 60.072 ;
     RECT  217.753 54.672 218.005 60.072 ;
     RECT  218.005 54.576 218.365 60.072 ;
     RECT  217.717 61.728 218.365 70.248 ;
     RECT  218.365 61.68 218.617 70.248 ;
     RECT  218.617 61.68 218.869 70.44 ;
     RECT  218.869 61.392 220.165 70.44 ;
     RECT  218.365 54.48 220.284 60.072 ;
     RECT  220.165 61.392 220.284 70.536 ;
    LAYER M5 ;
     RECT  6.864 0.016 7.176 0.611 ;
     RECT  7.152 0.611 7.176 1.187 ;
     RECT  16.08 0.016 19.08 1.907 ;
     RECT  2.4 2.137 2.52 2.151 ;
     RECT  7.8 2.137 7.92 2.151 ;
     RECT  13.2 2.137 13.32 2.151 ;
     RECT  24 2.137 24.12 2.151 ;
     RECT  29.4 2.137 29.52 2.151 ;
     RECT  34.8 2.137 34.92 2.151 ;
     RECT  40.2 2.137 40.32 2.151 ;
     RECT  45.6 2.137 45.72 2.151 ;
     RECT  51 2.137 51.12 2.151 ;
     RECT  56.4 2.137 56.52 2.151 ;
     RECT  61.8 2.137 61.92 2.151 ;
     RECT  67.2 2.137 67.32 2.151 ;
     RECT  72.6 2.137 72.72 2.151 ;
     RECT  78 2.137 78.12 2.151 ;
     RECT  83.4 2.137 83.52 2.151 ;
     RECT  88.8 2.137 88.92 2.151 ;
     RECT  94.2 2.137 94.32 2.151 ;
     RECT  99.6 2.137 99.72 2.151 ;
     RECT  105 2.137 105.12 2.151 ;
     RECT  110.4 2.137 110.52 2.151 ;
     RECT  115.8 2.137 115.92 2.151 ;
     RECT  121.2 2.137 121.32 2.151 ;
     RECT  126.6 2.137 126.72 2.151 ;
     RECT  132 2.137 132.12 2.151 ;
     RECT  137.4 2.137 137.52 2.151 ;
     RECT  142.8 2.137 142.92 2.151 ;
     RECT  148.2 2.137 148.32 2.151 ;
     RECT  153.6 2.137 153.72 2.151 ;
     RECT  159 2.137 159.12 2.151 ;
     RECT  164.4 2.137 164.52 2.151 ;
     RECT  169.8 2.137 169.92 2.151 ;
     RECT  175.2 2.137 175.32 2.151 ;
     RECT  180.6 2.137 180.72 2.151 ;
     RECT  186 2.137 186.12 2.151 ;
     RECT  191.4 2.137 191.52 2.151 ;
     RECT  196.8 2.137 196.92 2.151 ;
     RECT  202.2 2.137 202.32 2.151 ;
     RECT  207.6 2.137 207.72 2.151 ;
     RECT  213 2.137 213.12 2.151 ;
     RECT  14.784 2.197 14.808 2.915 ;
     RECT  21.264 2.821 21.288 3.157 ;
     RECT  16.08 1.907 18.912 3.829 ;
     RECT  21.168 3.157 21.288 3.925 ;
     RECT  21.12 3.925 21.288 4.019 ;
     RECT  16.08 3.829 19.512 4.261 ;
     RECT  15.648 4.261 19.512 4.357 ;
     RECT  15.648 4.357 19.56 4.453 ;
     RECT  15.648 4.453 19.944 5.077 ;
     RECT  21.12 4.019 21.192 5.077 ;
     RECT  15.648 5.077 21.192 5.171 ;
     RECT  15.648 5.171 21.144 5.987 ;
     RECT  15.648 5.987 16.728 6.083 ;
     RECT  17.712 5.987 21.144 6.323 ;
     RECT  19.92 6.323 21.144 6.851 ;
     RECT  19.92 6.851 20.376 7.187 ;
     RECT  14.544 6.709 14.568 7.381 ;
     RECT  15.744 6.083 16.728 7.381 ;
     RECT  10.8 6.805 10.824 7.955 ;
     RECT  6.288 6.229 6.312 8.003 ;
     RECT  14.544 7.381 16.728 8.003 ;
     RECT  14.784 8.003 16.728 8.051 ;
     RECT  20.352 7.187 20.376 8.243 ;
     RECT  13.2 2.151 13.512 8.437 ;
     RECT  9.264 5.077 9.288 8.723 ;
     RECT  12.528 8.437 13.512 9.395 ;
     RECT  21.072 9.349 21.096 9.685 ;
     RECT  14.784 8.051 15.96 9.731 ;
     RECT  18.24 6.323 18.912 9.731 ;
     RECT  20.448 9.685 21.096 10.355 ;
     RECT  20.544 10.355 21.096 10.403 ;
     RECT  13.2 9.395 13.512 10.789 ;
     RECT  13.2 10.789 13.944 11.221 ;
     RECT  15.36 9.731 15.96 11.363 ;
     RECT  9.12 10.693 9.144 11.459 ;
     RECT  20.544 10.403 20.568 11.459 ;
     RECT  13.2 11.221 14.232 12.035 ;
     RECT  10.608 11.557 10.632 12.227 ;
     RECT  13.2 12.035 13.512 33.829 ;
     RECT  126.6 2.151 126.912 33.973 ;
     RECT  13.2 33.829 13.896 34.787 ;
     RECT  126.384 33.973 126.912 35.027 ;
     RECT  13.2 34.787 13.656 38.531 ;
     RECT  83.4 2.151 83.712 39.205 ;
     RECT  200.64 35.125 200.664 39.205 ;
     RECT  88.8 2.151 89.112 39.253 ;
     RECT  200.64 39.205 200.904 39.253 ;
     RECT  202.2 2.151 202.512 39.253 ;
     RECT  18.6 9.731 18.912 39.589 ;
     RECT  83.28 39.205 83.712 39.733 ;
     RECT  200.64 39.253 202.512 39.781 ;
     RECT  51 2.151 51.312 40.021 ;
     RECT  18.096 39.589 18.912 40.117 ;
     RECT  78 2.151 78.312 40.309 ;
     RECT  4.848 40.309 4.872 40.357 ;
     RECT  5.904 40.261 5.928 40.357 ;
     RECT  45.6 2.151 45.912 40.357 ;
     RECT  88.464 39.253 89.112 40.357 ;
     RECT  196.8 2.151 197.112 40.357 ;
     RECT  15.36 11.363 15.576 40.405 ;
     RECT  17.472 40.117 18.912 40.405 ;
     RECT  14.976 40.405 18.912 40.693 ;
     RECT  82.944 39.733 83.712 40.837 ;
     RECT  200.304 39.781 202.512 40.837 ;
     RECT  7.8 2.151 8.112 40.885 ;
     RECT  24 2.151 24.312 40.933 ;
     RECT  110.4 2.151 110.712 40.933 ;
     RECT  88.464 40.357 89.784 41.365 ;
     RECT  20.208 40.645 20.232 41.509 ;
     RECT  72.6 2.151 72.912 41.557 ;
     RECT  61.8 2.151 62.112 41.989 ;
     RECT  137.4 2.151 137.712 42.469 ;
     RECT  7.44 40.885 8.112 42.517 ;
     RECT  153.6 2.151 153.912 42.517 ;
     RECT  20.16 41.509 20.232 42.997 ;
     RECT  148.2 2.151 148.512 42.997 ;
     RECT  71.712 41.557 72.912 43.045 ;
     RECT  88.464 41.365 89.832 43.045 ;
     RECT  198.624 40.021 198.648 43.045 ;
     RECT  199.632 40.837 202.512 43.045 ;
     RECT  21.6 42.997 21.624 43.237 ;
     RECT  21.6 43.237 22.488 43.285 ;
     RECT  142.8 2.151 143.112 43.621 ;
     RECT  71.712 43.045 73.224 44.053 ;
     RECT  7.008 42.517 8.112 44.341 ;
     RECT  153.6 42.517 154.152 44.341 ;
     RECT  9.36 39.301 9.384 44.389 ;
     RECT  61.8 41.989 62.424 44.389 ;
     RECT  24 40.933 24.456 44.437 ;
     RECT  14.976 40.693 19.032 44.677 ;
     RECT  20.16 42.997 20.52 44.677 ;
     RECT  61.8 44.389 62.472 44.725 ;
     RECT  61.536 44.725 62.472 44.917 ;
     RECT  196.8 40.357 197.496 44.917 ;
     RECT  14.976 44.677 20.52 45.157 ;
     RECT  21.504 43.285 22.488 45.157 ;
     RECT  6.912 44.341 8.112 45.397 ;
     RECT  9.168 44.389 9.384 45.397 ;
     RECT  148.2 42.997 149.064 45.397 ;
     RECT  67.2 2.151 67.512 45.445 ;
     RECT  66.864 45.445 67.512 45.493 ;
     RECT  13.2 38.531 13.608 45.733 ;
     RECT  13.104 45.733 13.608 45.779 ;
     RECT  13.104 45.779 13.512 45.875 ;
     RECT  94.2 2.151 94.512 46.117 ;
     RECT  80.064 40.597 80.088 46.213 ;
     RECT  196.8 44.917 197.64 46.213 ;
     RECT  198.624 43.045 202.512 46.213 ;
     RECT  82.944 40.837 84.072 46.883 ;
     RECT  83.28 46.883 84.072 47.795 ;
     RECT  133.68 45.157 133.704 47.939 ;
     RECT  4.848 40.357 5.928 48.515 ;
     RECT  23.76 44.437 24.456 48.997 ;
     RECT  25.584 44.341 25.608 48.997 ;
     RECT  5.472 48.515 5.496 49.043 ;
     RECT  14.976 45.157 22.488 49.093 ;
     RECT  14.976 49.093 22.68 49.141 ;
     RECT  23.76 48.997 25.608 49.235 ;
     RECT  49.008 49.093 49.032 49.235 ;
     RECT  78 40.309 78.936 49.283 ;
     RECT  10.848 47.845 10.872 49.331 ;
     RECT  14.976 49.141 22.776 49.381 ;
     RECT  23.76 49.235 24.408 49.381 ;
     RECT  186 2.151 186.312 49.477 ;
     RECT  182.4 49.285 182.424 49.523 ;
     RECT  105 2.151 105.312 49.525 ;
     RECT  6.912 45.397 9.384 49.619 ;
     RECT  110.4 40.933 111.432 49.619 ;
     RECT  31.008 41.461 31.032 49.715 ;
     RECT  65.232 41.413 65.256 49.715 ;
     RECT  76.992 41.461 77.016 49.715 ;
     RECT  83.4 47.795 84.072 49.715 ;
     RECT  87.984 43.045 89.832 49.715 ;
     RECT  71.712 44.053 73.32 49.763 ;
     RECT  25.584 49.235 25.608 50.053 ;
     RECT  2.4 2.151 2.712 50.101 ;
     RECT  14.976 49.381 24.408 50.195 ;
     RECT  58.416 44.869 58.44 50.197 ;
     RECT  14.976 50.195 15 50.387 ;
     RECT  58.416 50.197 58.728 50.437 ;
     RECT  109.296 40.885 109.32 50.533 ;
     RECT  105 49.525 105.48 50.579 ;
     RECT  78 49.283 78.312 50.581 ;
     RECT  7.008 49.619 9.384 50.771 ;
     RECT  27.6 41.893 27.624 50.771 ;
     RECT  2.4 50.101 3.432 50.819 ;
     RECT  40.2 2.151 40.512 50.869 ;
     RECT  91.152 44.965 91.176 50.869 ;
     RECT  133.344 48.373 133.656 50.869 ;
     RECT  60.912 44.917 62.472 50.915 ;
     RECT  51 40.021 52.056 50.917 ;
     RECT  72.6 49.763 73.32 50.917 ;
     RECT  121.2 2.151 121.512 50.917 ;
     RECT  122.496 50.869 122.52 50.917 ;
     RECT  133.344 50.869 133.752 50.917 ;
     RECT  58.416 50.437 59.256 51.011 ;
     RECT  66.864 45.493 68.088 51.011 ;
     RECT  108.816 50.533 109.32 51.013 ;
     RECT  110.4 49.619 110.952 51.013 ;
     RECT  16.032 50.195 24.408 51.059 ;
     RECT  50.736 50.917 52.056 51.059 ;
     RECT  53.088 50.917 53.112 51.059 ;
     RECT  121.2 50.917 122.52 51.059 ;
     RECT  25.584 50.053 25.656 51.107 ;
     RECT  58.416 51.011 58.728 51.107 ;
     RECT  60.912 50.915 62.328 51.107 ;
     RECT  101.184 50.437 101.208 51.107 ;
     RECT  108.816 51.013 110.952 51.107 ;
     RECT  77.376 50.581 78.312 51.155 ;
     RECT  90.624 50.869 91.176 51.155 ;
     RECT  109.296 51.107 110.952 51.155 ;
     RECT  118.56 51.013 118.584 51.155 ;
     RECT  121.2 51.059 121.704 51.155 ;
     RECT  133.344 50.917 133.848 51.155 ;
     RECT  109.296 51.155 109.32 51.203 ;
     RECT  72.6 50.917 73.944 51.251 ;
     RECT  83.4 49.715 83.832 51.251 ;
     RECT  110.4 51.155 110.952 51.251 ;
     RECT  130.56 50.869 130.584 51.299 ;
     RECT  25.584 51.107 25.608 51.347 ;
     RECT  44.688 40.357 45.912 51.347 ;
     RECT  48.432 49.237 48.456 51.347 ;
     RECT  51 51.059 52.056 51.347 ;
     RECT  58.416 51.107 58.44 51.347 ;
     RECT  80.064 46.213 80.712 51.347 ;
     RECT  87.984 49.715 89.112 51.347 ;
     RECT  91.152 51.155 91.176 51.347 ;
     RECT  142.8 43.621 143.352 51.347 ;
     RECT  137.4 42.469 138.216 51.395 ;
     RECT  40.2 50.869 41.016 51.397 ;
     RECT  67.2 51.011 68.088 51.491 ;
     RECT  70.704 51.349 70.728 51.491 ;
     RECT  94.2 46.117 94.872 51.491 ;
     RECT  75.264 49.957 75.288 51.493 ;
     RECT  153.6 44.341 154.248 51.539 ;
     RECT  186 49.477 186.408 51.539 ;
     RECT  24 51.059 24.408 51.541 ;
     RECT  60.912 51.107 62.112 51.587 ;
     RECT  148.2 45.397 149.16 51.587 ;
     RECT  45.024 51.347 45.912 51.635 ;
     RECT  148.2 51.587 149.064 51.635 ;
     RECT  78 51.155 78.312 51.637 ;
     RECT  74.688 51.493 75.288 51.683 ;
     RECT  133.344 51.155 133.368 51.683 ;
     RECT  24 51.541 25.128 51.731 ;
     RECT  38.784 51.253 38.808 51.779 ;
     RECT  40.2 51.397 41.16 51.779 ;
     RECT  42.768 51.397 42.792 51.779 ;
     RECT  54.72 51.397 54.744 51.779 ;
     RECT  72.6 51.251 73.32 51.779 ;
     RECT  78 51.637 78.744 51.779 ;
     RECT  134.592 51.445 134.616 51.779 ;
     RECT  72.6 51.779 73.224 51.827 ;
     RECT  132 2.151 132.312 51.877 ;
     RECT  11.424 49.429 11.448 51.971 ;
     RECT  131.904 51.877 132.312 52.019 ;
     RECT  13.2 45.875 13.512 52.645 ;
     RECT  11.616 52.213 11.64 52.739 ;
     RECT  24 51.731 24.552 52.739 ;
     RECT  111.696 51.253 111.72 52.883 ;
     RECT  16.032 51.059 22.776 52.981 ;
     RECT  15.36 52.981 22.776 53.317 ;
     RECT  24 52.739 24.312 53.317 ;
     RECT  74.688 51.683 74.712 53.363 ;
     RECT  13.2 52.645 13.608 53.699 ;
     RECT  15.36 53.317 24.312 53.843 ;
     RECT  40.2 51.779 41.016 53.891 ;
     RECT  4.848 53.941 4.872 54.517 ;
     RECT  4.272 54.517 4.872 54.709 ;
     RECT  15.36 53.843 22.776 54.803 ;
     RECT  15.36 54.803 22.728 54.851 ;
     RECT  4.272 54.709 5.304 55.237 ;
     RECT  13.2 53.699 13.512 55.237 ;
     RECT  3.744 55.237 5.304 55.283 ;
     RECT  11.856 54.661 11.88 55.283 ;
     RECT  4.848 55.283 5.304 55.331 ;
     RECT  3.744 55.283 3.768 55.859 ;
     RECT  5.28 55.331 5.304 55.955 ;
     RECT  209.424 51.637 209.448 55.957 ;
     RECT  209.28 55.957 209.448 56.003 ;
     RECT  16.224 54.851 22.728 56.435 ;
     RECT  206.016 50.821 206.04 56.533 ;
     RECT  207.6 2.151 207.912 56.533 ;
     RECT  7.056 50.771 9.384 56.677 ;
     RECT  13.2 55.237 13.656 56.723 ;
     RECT  213 2.151 213.312 56.917 ;
     RECT  6.192 56.677 9.384 57.635 ;
     RECT  16.224 56.435 22.68 58.117 ;
     RECT  206.016 56.533 207.912 58.163 ;
     RECT  6.192 57.635 8.112 58.645 ;
     RECT  9.168 57.635 9.384 58.645 ;
     RECT  207.6 58.163 207.912 58.645 ;
     RECT  209.28 56.003 209.304 58.645 ;
     RECT  212.448 56.917 213.312 58.691 ;
     RECT  6.192 58.645 9.384 58.739 ;
     RECT  15.984 58.117 22.68 58.981 ;
     RECT  15.12 58.981 22.68 59.027 ;
     RECT  207.6 58.645 209.304 59.459 ;
     RECT  7.68 58.739 9.384 59.891 ;
     RECT  7.68 59.891 8.112 60.035 ;
     RECT  209.28 59.459 209.304 60.373 ;
     RECT  213 58.691 213.312 60.373 ;
     RECT  209.28 60.373 209.496 60.419 ;
     RECT  4.128 59.077 4.152 60.467 ;
     RECT  15.12 59.027 15.144 60.707 ;
     RECT  9.168 59.891 9.384 61.043 ;
     RECT  196.8 46.213 202.512 61.427 ;
     RECT  212.016 60.373 213.312 61.619 ;
     RECT  6.192 58.739 6.216 62.677 ;
     RECT  7.8 60.035 8.112 62.677 ;
     RECT  207.6 59.459 207.912 62.725 ;
     RECT  6.192 62.677 8.112 62.819 ;
     RECT  13.2 56.723 13.512 63.061 ;
     RECT  6.192 62.819 6.216 63.205 ;
     RECT  216.288 63.109 216.312 63.251 ;
     RECT  5.424 63.205 6.216 63.299 ;
     RECT  9.36 61.043 9.384 63.299 ;
     RECT  16.224 59.027 22.68 63.299 ;
     RECT  207.456 62.725 207.912 63.299 ;
     RECT  210.576 62.629 210.6 63.299 ;
     RECT  209.472 60.419 209.496 63.781 ;
     RECT  5.424 63.299 5.448 63.827 ;
     RECT  209.472 63.781 209.736 63.827 ;
     RECT  16.224 63.299 21.432 63.875 ;
     RECT  22.416 63.299 22.68 64.307 ;
     RECT  16.224 63.875 21.384 64.355 ;
     RECT  207.6 63.299 207.912 64.597 ;
     RECT  209.712 63.827 209.736 64.643 ;
     RECT  16.896 64.355 21.384 65.027 ;
     RECT  22.464 64.307 22.68 65.555 ;
     RECT  198.384 61.427 202.512 65.651 ;
     RECT  13.2 63.061 14.28 65.699 ;
     RECT  213 61.619 213.312 66.085 ;
     RECT  4.464 65.509 4.488 66.227 ;
     RECT  198.384 65.651 199.896 66.227 ;
     RECT  217.824 66.133 217.848 66.515 ;
     RECT  16.896 65.027 21.096 66.613 ;
     RECT  16.512 66.613 21.096 66.755 ;
     RECT  17.472 66.755 21.096 66.899 ;
     RECT  200.88 65.651 202.512 66.899 ;
     RECT  220.128 66.853 220.152 67.043 ;
     RECT  17.472 66.899 21 67.283 ;
     RECT  207.6 64.597 208.728 67.715 ;
     RECT  206.016 58.163 206.04 67.765 ;
     RECT  206.016 67.765 206.328 67.811 ;
     RECT  212.88 66.085 213.312 67.859 ;
     RECT  17.568 67.283 19.176 67.955 ;
     RECT  22.464 65.555 22.488 68.051 ;
     RECT  200.928 66.899 202.512 68.195 ;
     RECT  206.304 67.811 206.328 68.675 ;
     RECT  216.48 68.821 216.504 68.963 ;
     RECT  207.6 67.715 208.488 69.203 ;
     RECT  18 67.955 19.176 69.829 ;
     RECT  20.16 67.283 21 69.829 ;
     RECT  13.2 65.699 13.512 70.021 ;
     RECT  14.832 68.917 14.856 70.021 ;
     RECT  13.2 70.021 14.856 70.067 ;
     RECT  18 69.829 21 70.163 ;
     RECT  201.168 68.195 202.512 70.163 ;
     RECT  4.512 66.661 4.536 70.595 ;
     RECT  20.976 70.163 21 70.739 ;
     RECT  13.2 70.067 13.944 70.787 ;
     RECT  18 70.163 19.368 73.811 ;
     RECT  18 73.811 19.176 75.013 ;
     RECT  14.976 74.485 15 75.971 ;
     RECT  18 75.013 19.848 78.083 ;
     RECT  18.6 78.083 19.848 78.179 ;
     RECT  199.872 66.227 199.896 80.435 ;
     RECT  5.616 78.037 5.64 82.115 ;
     RECT  0.144 82.261 0.168 82.451 ;
     RECT  18.6 78.179 19.176 83.363 ;
     RECT  7.8 62.819 8.112 83.461 ;
     RECT  5.088 83.077 5.112 84.179 ;
     RECT  201.792 70.163 202.512 84.995 ;
     RECT  17.328 80.965 17.352 85.235 ;
     RECT  7.8 83.461 8.856 85.523 ;
     RECT  2.4 50.819 2.712 86.293 ;
     RECT  2.4 86.293 2.856 86.579 ;
     RECT  5.136 86.005 5.16 86.675 ;
     RECT  0.144 88.069 0.168 88.259 ;
     RECT  198.384 66.227 198.648 93.539 ;
     RECT  7.8 85.523 8.808 94.021 ;
     RECT  198.384 93.539 198.408 94.691 ;
     RECT  7.536 94.021 8.808 94.979 ;
     RECT  7.584 94.979 8.808 95.411 ;
     RECT  7.584 95.411 8.112 95.891 ;
     RECT  5.664 95.365 5.688 97.523 ;
     RECT  2.4 86.579 2.712 174.969 ;
     RECT  7.8 95.891 8.112 174.969 ;
     RECT  13.2 70.787 13.512 174.969 ;
     RECT  18.6 83.363 18.912 174.969 ;
     RECT  24 53.843 24.312 174.969 ;
     RECT  29.4 2.151 29.712 174.969 ;
     RECT  34.8 2.151 35.112 174.969 ;
     RECT  40.2 53.891 40.512 174.969 ;
     RECT  45.6 51.635 45.912 174.969 ;
     RECT  51 51.347 51.312 174.969 ;
     RECT  56.4 2.151 56.712 174.969 ;
     RECT  61.8 51.587 62.112 174.969 ;
     RECT  67.2 51.491 67.512 174.969 ;
     RECT  72.6 51.827 72.912 174.969 ;
     RECT  78 51.779 78.312 174.969 ;
     RECT  83.4 51.251 83.712 174.969 ;
     RECT  88.8 51.347 89.112 174.969 ;
     RECT  94.2 51.491 94.512 174.969 ;
     RECT  99.6 2.151 99.912 174.969 ;
     RECT  105 50.579 105.312 174.969 ;
     RECT  110.4 51.251 110.712 174.969 ;
     RECT  115.8 2.151 116.112 174.969 ;
     RECT  121.2 51.155 121.512 174.969 ;
     RECT  126.6 35.027 126.912 174.969 ;
     RECT  132 52.019 132.312 174.969 ;
     RECT  137.4 51.395 137.712 174.969 ;
     RECT  142.8 51.347 143.112 174.969 ;
     RECT  148.2 51.635 148.512 174.969 ;
     RECT  153.6 51.539 153.912 174.969 ;
     RECT  159 2.151 159.312 174.969 ;
     RECT  164.4 2.151 164.712 174.969 ;
     RECT  169.8 2.151 170.112 174.969 ;
     RECT  175.2 2.151 175.512 174.969 ;
     RECT  180.6 2.151 180.912 174.969 ;
     RECT  186 51.539 186.312 174.969 ;
     RECT  191.4 2.151 191.712 174.969 ;
     RECT  196.8 61.427 197.112 174.969 ;
     RECT  202.2 84.995 202.512 174.969 ;
     RECT  207.6 69.203 207.912 174.969 ;
     RECT  213 67.859 213.312 174.969 ;
     RECT  2.4 174.969 2.52 174.983 ;
     RECT  7.8 174.969 7.92 174.983 ;
     RECT  13.2 174.969 13.32 174.983 ;
     RECT  18.6 174.969 18.72 174.983 ;
     RECT  24 174.969 24.12 174.983 ;
     RECT  29.4 174.969 29.52 174.983 ;
     RECT  34.8 174.969 34.92 174.983 ;
     RECT  40.2 174.969 40.32 174.983 ;
     RECT  45.6 174.969 45.72 174.983 ;
     RECT  51 174.969 51.12 174.983 ;
     RECT  56.4 174.969 56.52 174.983 ;
     RECT  61.8 174.969 61.92 174.983 ;
     RECT  67.2 174.969 67.32 174.983 ;
     RECT  72.6 174.969 72.72 174.983 ;
     RECT  78 174.969 78.12 174.983 ;
     RECT  83.4 174.969 83.52 174.983 ;
     RECT  88.8 174.969 88.92 174.983 ;
     RECT  94.2 174.969 94.32 174.983 ;
     RECT  99.6 174.969 99.72 174.983 ;
     RECT  105 174.969 105.12 174.983 ;
     RECT  110.4 174.969 110.52 174.983 ;
     RECT  115.8 174.969 115.92 174.983 ;
     RECT  121.2 174.969 121.32 174.983 ;
     RECT  126.6 174.969 126.72 174.983 ;
     RECT  132 174.969 132.12 174.983 ;
     RECT  137.4 174.969 137.52 174.983 ;
     RECT  142.8 174.969 142.92 174.983 ;
     RECT  148.2 174.969 148.32 174.983 ;
     RECT  153.6 174.969 153.72 174.983 ;
     RECT  159 174.969 159.12 174.983 ;
     RECT  164.4 174.969 164.52 174.983 ;
     RECT  169.8 174.969 169.92 174.983 ;
     RECT  175.2 174.969 175.32 174.983 ;
     RECT  180.6 174.969 180.72 174.983 ;
     RECT  186 174.969 186.12 174.983 ;
     RECT  191.4 174.969 191.52 174.983 ;
     RECT  196.8 174.969 196.92 174.983 ;
     RECT  202.2 174.969 202.32 174.983 ;
     RECT  207.6 174.969 207.72 174.983 ;
     RECT  213 174.969 213.12 174.983 ;
     RECT  13.512 2.197 14.784 2.915 ;
     RECT  14.808 2.197 16.08 2.915 ;
     RECT  15.648 2.915 16.08 4.261 ;
     RECT  19.944 4.453 21.12 5.077 ;
     RECT  8.112 5.077 9.264 8.723 ;
     RECT  16.728 5.987 17.712 6.323 ;
     RECT  15.648 6.083 15.744 6.709 ;
     RECT  6.312 6.229 7.8 8.003 ;
     RECT  16.728 6.323 18.24 8.051 ;
     RECT  18.912 6.323 19.92 7.187 ;
     RECT  13.512 6.709 14.544 8.003 ;
     RECT  14.568 6.709 15.744 7.381 ;
     RECT  9.288 6.805 10.8 7.955 ;
     RECT  18.912 7.187 20.352 8.243 ;
     RECT  13.512 8.003 14.784 9.731 ;
     RECT  13.512 9.731 15.36 10.789 ;
     RECT  8.112 10.693 9.12 11.459 ;
     RECT  13.944 10.789 15.36 11.221 ;
     RECT  14.232 11.221 15.36 12.035 ;
     RECT  13.896 33.829 15.36 34.787 ;
     RECT  200.904 39.205 202.2 39.253 ;
     RECT  8.112 39.301 9.36 44.389 ;
     RECT  197.112 40.021 198.624 40.357 ;
     RECT  4.872 40.309 5.904 40.357 ;
     RECT  197.496 40.357 198.624 44.917 ;
     RECT  13.608 40.405 14.976 45.779 ;
     RECT  78.936 40.597 80.064 49.283 ;
     RECT  18.912 40.645 20.208 40.693 ;
     RECT  19.032 40.693 20.208 41.509 ;
     RECT  198.648 40.837 199.632 43.045 ;
     RECT  5.928 40.885 7.44 42.517 ;
     RECT  109.32 40.885 110.4 51.013 ;
     RECT  29.712 41.461 31.008 49.715 ;
     RECT  77.016 41.461 78 49.715 ;
     RECT  19.032 41.509 20.16 44.677 ;
     RECT  5.928 42.517 7.008 44.341 ;
     RECT  20.52 42.997 21.6 43.285 ;
     RECT  22.488 43.237 24 44.437 ;
     RECT  20.52 43.285 21.504 45.157 ;
     RECT  5.928 44.341 6.912 48.515 ;
     RECT  24.456 44.341 25.584 48.997 ;
     RECT  8.112 44.389 9.168 45.397 ;
     RECT  22.488 44.437 23.76 49.093 ;
     RECT  197.64 44.917 198.624 46.213 ;
     RECT  89.832 44.965 91.152 49.715 ;
     RECT  132.312 45.157 133.68 47.939 ;
     RECT  13.512 45.779 14.976 50.387 ;
     RECT  9.384 47.845 10.848 49.331 ;
     RECT  132.312 47.939 133.656 48.373 ;
     RECT  132.312 48.373 133.344 51.683 ;
     RECT  5.496 48.515 6.912 49.043 ;
     RECT  22.68 49.093 23.76 49.141 ;
     RECT  22.776 49.141 23.76 49.381 ;
     RECT  24.408 49.235 25.584 51.347 ;
     RECT  180.912 49.285 182.4 49.523 ;
     RECT  77.376 49.715 78 50.581 ;
     RECT  89.112 49.715 91.152 50.869 ;
     RECT  15 50.195 16.032 50.387 ;
     RECT  99.912 50.437 101.184 51.107 ;
     RECT  89.112 50.869 90.624 51.155 ;
     RECT  121.512 50.869 122.496 50.917 ;
     RECT  130.584 50.869 132 51.299 ;
     RECT  52.056 50.917 53.088 51.059 ;
     RECT  73.944 50.917 75.264 51.251 ;
     RECT  22.776 51.059 24 53.317 ;
     RECT  109.32 51.155 110.4 51.203 ;
     RECT  133.368 51.155 133.848 51.445 ;
     RECT  73.32 51.251 75.264 51.493 ;
     RECT  110.712 51.251 110.952 51.253 ;
     RECT  38.808 51.253 40.2 51.779 ;
     RECT  110.712 51.253 111.696 52.883 ;
     RECT  131.904 51.299 132 51.877 ;
     RECT  24.408 51.347 25.128 51.541 ;
     RECT  133.368 51.445 134.592 51.683 ;
     RECT  73.32 51.493 74.688 51.779 ;
     RECT  207.912 51.637 209.424 55.957 ;
     RECT  73.224 51.779 74.688 51.827 ;
     RECT  22.776 53.843 24 54.803 ;
     RECT  11.88 54.661 13.2 55.283 ;
     RECT  22.728 54.803 24 56.435 ;
     RECT  2.712 55.237 3.744 55.859 ;
     RECT  3.768 55.283 4.848 55.331 ;
     RECT  3.768 55.331 5.28 55.859 ;
     RECT  207.912 55.957 209.28 58.645 ;
     RECT  22.68 56.435 24 65.555 ;
     RECT  8.112 57.635 9.168 58.645 ;
     RECT  6.216 58.739 7.68 60.035 ;
     RECT  15.144 59.027 16.224 60.707 ;
     RECT  2.712 59.077 4.128 60.467 ;
     RECT  207.912 59.459 209.28 60.419 ;
     RECT  8.112 59.891 9.168 61.043 ;
     RECT  8.112 61.043 9.36 63.299 ;
     RECT  197.112 61.427 198.384 94.691 ;
     RECT  209.496 62.629 210.576 63.299 ;
     RECT  206.04 62.725 207.456 63.299 ;
     RECT  21.432 63.299 22.416 63.875 ;
     RECT  209.496 63.299 209.736 63.781 ;
     RECT  209.472 63.827 209.712 64.597 ;
     RECT  21.384 63.875 22.416 64.307 ;
     RECT  21.384 64.307 22.464 65.027 ;
     RECT  208.728 64.597 209.712 64.643 ;
     RECT  21.096 65.027 22.464 66.899 ;
     RECT  22.488 65.555 24 68.051 ;
     RECT  199.896 65.651 200.88 66.899 ;
     RECT  198.648 66.227 199.872 80.435 ;
     RECT  21 66.899 22.464 68.051 ;
     RECT  199.896 66.899 200.928 68.195 ;
     RECT  19.176 67.283 20.16 69.829 ;
     RECT  206.328 67.765 207.6 68.675 ;
     RECT  199.896 68.195 201.168 70.163 ;
     RECT  13.512 68.917 14.832 70.021 ;
     RECT  19.176 73.811 19.368 75.013 ;
     RECT  13.512 74.485 14.976 75.971 ;
     RECT  17.352 80.965 18.6 85.235 ;
  END
END hfd_hgi_vm_calendar_NE
END LIBRARY
